VERSION 5.7 ;
  NOWIREEXTENSIONATPIN ON ;
  DIVIDERCHAR "/" ;
  BUSBITCHARS "[]" ;
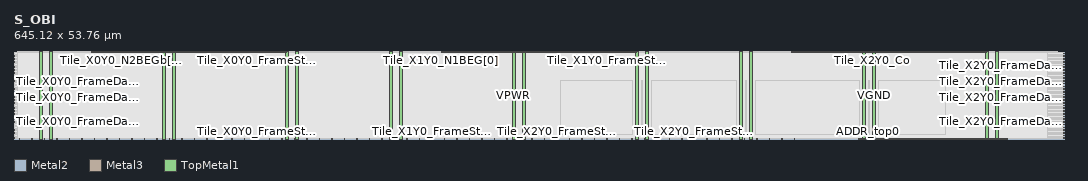
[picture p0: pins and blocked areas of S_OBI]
MACRO S_OBI
  CLASS BLOCK ;
  FOREIGN S_OBI ;
  ORIGIN 0.000 0.000 ;
  SIZE 645.120 BY 53.760 ;
  PIN ADDR_top0
    DIRECTION INPUT ;
    USE SIGNAL ;
    ANTENNAGATEAREA 1.684800 ;
    ANTENNADIFFAREA 4.030800 ;
    PORT
      LAYER Metal2 ;
        RECT 524.440 0.000 524.840 0.400 ;
    END
  END ADDR_top0
  PIN ADDR_top1
    DIRECTION INPUT ;
    USE SIGNAL ;
    ANTENNAGATEAREA 0.468000 ;
    PORT
      LAYER Metal2 ;
        RECT 525.400 0.000 525.800 0.400 ;
    END
  END ADDR_top1
  PIN ADDR_top10
    DIRECTION INPUT ;
    USE SIGNAL ;
    ANTENNAGATEAREA 0.468000 ;
    PORT
      LAYER Metal2 ;
        RECT 534.040 0.000 534.440 0.400 ;
    END
  END ADDR_top10
  PIN ADDR_top11
    DIRECTION INPUT ;
    USE SIGNAL ;
    ANTENNAGATEAREA 0.468000 ;
    PORT
      LAYER Metal2 ;
        RECT 535.000 0.000 535.400 0.400 ;
    END
  END ADDR_top11
  PIN ADDR_top12
    DIRECTION INPUT ;
    USE SIGNAL ;
    ANTENNAGATEAREA 0.468000 ;
    PORT
      LAYER Metal2 ;
        RECT 535.960 0.000 536.360 0.400 ;
    END
  END ADDR_top12
  PIN ADDR_top13
    DIRECTION INPUT ;
    USE SIGNAL ;
    ANTENNAGATEAREA 0.468000 ;
    PORT
      LAYER Metal2 ;
        RECT 536.920 0.000 537.320 0.400 ;
    END
  END ADDR_top13
  PIN ADDR_top14
    DIRECTION INPUT ;
    USE SIGNAL ;
    ANTENNAGATEAREA 0.452400 ;
    PORT
      LAYER Metal2 ;
        RECT 537.880 0.000 538.280 0.400 ;
    END
  END ADDR_top14
  PIN ADDR_top15
    DIRECTION INPUT ;
    USE SIGNAL ;
    ANTENNAGATEAREA 0.452400 ;
    PORT
      LAYER Metal2 ;
        RECT 538.840 0.000 539.240 0.400 ;
    END
  END ADDR_top15
  PIN ADDR_top16
    DIRECTION INPUT ;
    USE SIGNAL ;
    ANTENNAGATEAREA 0.452400 ;
    PORT
      LAYER Metal2 ;
        RECT 539.800 0.000 540.200 0.400 ;
    END
  END ADDR_top16
  PIN ADDR_top17
    DIRECTION INPUT ;
    USE SIGNAL ;
    ANTENNAGATEAREA 0.452400 ;
    PORT
      LAYER Metal2 ;
        RECT 540.760 0.000 541.160 0.400 ;
    END
  END ADDR_top17
  PIN ADDR_top18
    DIRECTION INPUT ;
    USE SIGNAL ;
    ANTENNAGATEAREA 0.452400 ;
    PORT
      LAYER Metal2 ;
        RECT 541.720 0.000 542.120 0.400 ;
    END
  END ADDR_top18
  PIN ADDR_top19
    DIRECTION INPUT ;
    USE SIGNAL ;
    ANTENNAGATEAREA 0.452400 ;
    PORT
      LAYER Metal2 ;
        RECT 542.680 0.000 543.080 0.400 ;
    END
  END ADDR_top19
  PIN ADDR_top2
    DIRECTION INPUT ;
    USE SIGNAL ;
    ANTENNAGATEAREA 0.468000 ;
    PORT
      LAYER Metal2 ;
        RECT 526.360 0.000 526.760 0.400 ;
    END
  END ADDR_top2
  PIN ADDR_top20
    DIRECTION INPUT ;
    USE SIGNAL ;
    ANTENNAGATEAREA 0.904800 ;
    PORT
      LAYER Metal2 ;
        RECT 543.640 0.000 544.040 0.400 ;
    END
  END ADDR_top20
  PIN ADDR_top21
    DIRECTION INPUT ;
    USE SIGNAL ;
    ANTENNAGATEAREA 0.904800 ;
    PORT
      LAYER Metal2 ;
        RECT 544.600 0.000 545.000 0.400 ;
    END
  END ADDR_top21
  PIN ADDR_top22
    DIRECTION INPUT ;
    USE SIGNAL ;
    ANTENNAGATEAREA 0.904800 ;
    PORT
      LAYER Metal2 ;
        RECT 545.560 0.000 545.960 0.400 ;
    END
  END ADDR_top22
  PIN ADDR_top23
    DIRECTION INPUT ;
    USE SIGNAL ;
    ANTENNAGATEAREA 3.946800 ;
    ANTENNADIFFAREA 10.077000 ;
    PORT
      LAYER Metal2 ;
        RECT 546.520 0.000 546.920 0.400 ;
    END
  END ADDR_top23
  PIN ADDR_top3
    DIRECTION INPUT ;
    USE SIGNAL ;
    ANTENNAGATEAREA 0.468000 ;
    PORT
      LAYER Metal2 ;
        RECT 527.320 0.000 527.720 0.400 ;
    END
  END ADDR_top3
  PIN ADDR_top4
    DIRECTION INPUT ;
    USE SIGNAL ;
    ANTENNAGATEAREA 0.452400 ;
    PORT
      LAYER Metal2 ;
        RECT 528.280 0.000 528.680 0.400 ;
    END
  END ADDR_top4
  PIN ADDR_top5
    DIRECTION INPUT ;
    USE SIGNAL ;
    ANTENNAGATEAREA 0.452400 ;
    PORT
      LAYER Metal2 ;
        RECT 529.240 0.000 529.640 0.400 ;
    END
  END ADDR_top5
  PIN ADDR_top6
    DIRECTION INPUT ;
    USE SIGNAL ;
    ANTENNAGATEAREA 0.452400 ;
    PORT
      LAYER Metal2 ;
        RECT 530.200 0.000 530.600 0.400 ;
    END
  END ADDR_top6
  PIN ADDR_top7
    DIRECTION INPUT ;
    USE SIGNAL ;
    ANTENNAGATEAREA 0.452400 ;
    PORT
      LAYER Metal2 ;
        RECT 531.160 0.000 531.560 0.400 ;
    END
  END ADDR_top7
  PIN ADDR_top8
    DIRECTION INPUT ;
    USE SIGNAL ;
    ANTENNAGATEAREA 0.452400 ;
    PORT
      LAYER Metal2 ;
        RECT 532.120 0.000 532.520 0.400 ;
    END
  END ADDR_top8
  PIN ADDR_top9
    DIRECTION INPUT ;
    USE SIGNAL ;
    ANTENNAGATEAREA 0.452400 ;
    PORT
      LAYER Metal2 ;
        RECT 533.080 0.000 533.480 0.400 ;
    END
  END ADDR_top9
  PIN BE_top0
    DIRECTION INPUT ;
    USE SIGNAL ;
    ANTENNAGATEAREA 0.665600 ;
    PORT
      LAYER Metal2 ;
        RECT 520.600 0.000 521.000 0.400 ;
    END
  END BE_top0
  PIN BE_top1
    DIRECTION INPUT ;
    USE SIGNAL ;
    ANTENNAGATEAREA 0.681200 ;
    PORT
      LAYER Metal2 ;
        RECT 521.560 0.000 521.960 0.400 ;
    END
  END BE_top1
  PIN BE_top2
    DIRECTION INPUT ;
    USE SIGNAL ;
    ANTENNAGATEAREA 0.665600 ;
    PORT
      LAYER Metal2 ;
        RECT 522.520 0.000 522.920 0.400 ;
    END
  END BE_top2
  PIN BE_top3
    DIRECTION INPUT ;
    USE SIGNAL ;
    ANTENNAGATEAREA 0.681200 ;
    PORT
      LAYER Metal2 ;
        RECT 523.480 0.000 523.880 0.400 ;
    END
  END BE_top3
  PIN GNT_top
    DIRECTION OUTPUT ;
    USE SIGNAL ;
    ANTENNADIFFAREA 0.615900 ;
    PORT
      LAYER Metal2 ;
        RECT 578.200 0.000 578.600 0.400 ;
    END
  END GNT_top
  PIN RDATA_top0
    DIRECTION OUTPUT ;
    USE SIGNAL ;
    ANTENNADIFFAREA 0.615900 ;
    PORT
      LAYER Metal2 ;
        RECT 580.120 0.000 580.520 0.400 ;
    END
  END RDATA_top0
  PIN RDATA_top1
    DIRECTION OUTPUT ;
    USE SIGNAL ;
    ANTENNADIFFAREA 0.615900 ;
    PORT
      LAYER Metal2 ;
        RECT 581.080 0.000 581.480 0.400 ;
    END
  END RDATA_top1
  PIN RDATA_top10
    DIRECTION OUTPUT ;
    USE SIGNAL ;
    ANTENNADIFFAREA 0.615900 ;
    PORT
      LAYER Metal2 ;
        RECT 589.720 0.000 590.120 0.400 ;
    END
  END RDATA_top10
  PIN RDATA_top11
    DIRECTION OUTPUT ;
    USE SIGNAL ;
    ANTENNADIFFAREA 0.615900 ;
    PORT
      LAYER Metal2 ;
        RECT 590.680 0.000 591.080 0.400 ;
    END
  END RDATA_top11
  PIN RDATA_top12
    DIRECTION OUTPUT ;
    USE SIGNAL ;
    ANTENNADIFFAREA 0.615900 ;
    PORT
      LAYER Metal2 ;
        RECT 591.640 0.000 592.040 0.400 ;
    END
  END RDATA_top12
  PIN RDATA_top13
    DIRECTION OUTPUT ;
    USE SIGNAL ;
    ANTENNADIFFAREA 0.615900 ;
    PORT
      LAYER Metal2 ;
        RECT 592.600 0.000 593.000 0.400 ;
    END
  END RDATA_top13
  PIN RDATA_top14
    DIRECTION OUTPUT ;
    USE SIGNAL ;
    ANTENNADIFFAREA 0.615900 ;
    PORT
      LAYER Metal2 ;
        RECT 593.560 0.000 593.960 0.400 ;
    END
  END RDATA_top14
  PIN RDATA_top15
    DIRECTION OUTPUT ;
    USE SIGNAL ;
    ANTENNADIFFAREA 0.615900 ;
    PORT
      LAYER Metal2 ;
        RECT 594.520 0.000 594.920 0.400 ;
    END
  END RDATA_top15
  PIN RDATA_top16
    DIRECTION OUTPUT ;
    USE SIGNAL ;
    ANTENNADIFFAREA 0.615900 ;
    PORT
      LAYER Metal2 ;
        RECT 595.480 0.000 595.880 0.400 ;
    END
  END RDATA_top16
  PIN RDATA_top17
    DIRECTION OUTPUT ;
    USE SIGNAL ;
    ANTENNADIFFAREA 0.615900 ;
    PORT
      LAYER Metal2 ;
        RECT 596.440 0.000 596.840 0.400 ;
    END
  END RDATA_top17
  PIN RDATA_top18
    DIRECTION OUTPUT ;
    USE SIGNAL ;
    ANTENNADIFFAREA 0.615900 ;
    PORT
      LAYER Metal2 ;
        RECT 597.400 0.000 597.800 0.400 ;
    END
  END RDATA_top18
  PIN RDATA_top19
    DIRECTION OUTPUT ;
    USE SIGNAL ;
    ANTENNADIFFAREA 0.615900 ;
    PORT
      LAYER Metal2 ;
        RECT 598.360 0.000 598.760 0.400 ;
    END
  END RDATA_top19
  PIN RDATA_top2
    DIRECTION OUTPUT ;
    USE SIGNAL ;
    ANTENNADIFFAREA 0.615900 ;
    PORT
      LAYER Metal2 ;
        RECT 582.040 0.000 582.440 0.400 ;
    END
  END RDATA_top2
  PIN RDATA_top20
    DIRECTION OUTPUT ;
    USE SIGNAL ;
    ANTENNADIFFAREA 0.677200 ;
    PORT
      LAYER Metal2 ;
        RECT 599.320 0.000 599.720 0.400 ;
    END
  END RDATA_top20
  PIN RDATA_top21
    DIRECTION OUTPUT ;
    USE SIGNAL ;
    ANTENNADIFFAREA 0.677200 ;
    PORT
      LAYER Metal2 ;
        RECT 600.280 0.000 600.680 0.400 ;
    END
  END RDATA_top21
  PIN RDATA_top22
    DIRECTION OUTPUT ;
    USE SIGNAL ;
    ANTENNADIFFAREA 0.677200 ;
    PORT
      LAYER Metal2 ;
        RECT 601.240 0.000 601.640 0.400 ;
    END
  END RDATA_top22
  PIN RDATA_top23
    DIRECTION OUTPUT ;
    USE SIGNAL ;
    ANTENNADIFFAREA 0.677200 ;
    PORT
      LAYER Metal2 ;
        RECT 602.200 0.000 602.600 0.400 ;
    END
  END RDATA_top23
  PIN RDATA_top24
    DIRECTION OUTPUT ;
    USE SIGNAL ;
    ANTENNADIFFAREA 0.677200 ;
    PORT
      LAYER Metal2 ;
        RECT 603.160 0.000 603.560 0.400 ;
    END
  END RDATA_top24
  PIN RDATA_top25
    DIRECTION OUTPUT ;
    USE SIGNAL ;
    ANTENNADIFFAREA 0.677200 ;
    PORT
      LAYER Metal2 ;
        RECT 604.120 0.000 604.520 0.400 ;
    END
  END RDATA_top25
  PIN RDATA_top26
    DIRECTION OUTPUT ;
    USE SIGNAL ;
    ANTENNADIFFAREA 0.677200 ;
    PORT
      LAYER Metal2 ;
        RECT 605.080 0.000 605.480 0.400 ;
    END
  END RDATA_top26
  PIN RDATA_top27
    DIRECTION OUTPUT ;
    USE SIGNAL ;
    ANTENNADIFFAREA 0.677200 ;
    PORT
      LAYER Metal2 ;
        RECT 606.040 0.000 606.440 0.400 ;
    END
  END RDATA_top27
  PIN RDATA_top28
    DIRECTION OUTPUT ;
    USE SIGNAL ;
    ANTENNADIFFAREA 0.677200 ;
    PORT
      LAYER Metal2 ;
        RECT 607.000 0.000 607.400 0.400 ;
    END
  END RDATA_top28
  PIN RDATA_top29
    DIRECTION OUTPUT ;
    USE SIGNAL ;
    ANTENNADIFFAREA 0.677200 ;
    PORT
      LAYER Metal2 ;
        RECT 607.960 0.000 608.360 0.400 ;
    END
  END RDATA_top29
  PIN RDATA_top3
    DIRECTION OUTPUT ;
    USE SIGNAL ;
    ANTENNADIFFAREA 0.615900 ;
    PORT
      LAYER Metal2 ;
        RECT 583.000 0.000 583.400 0.400 ;
    END
  END RDATA_top3
  PIN RDATA_top30
    DIRECTION OUTPUT ;
    USE SIGNAL ;
    ANTENNADIFFAREA 0.677200 ;
    PORT
      LAYER Metal2 ;
        RECT 608.920 0.000 609.320 0.400 ;
    END
  END RDATA_top30
  PIN RDATA_top31
    DIRECTION OUTPUT ;
    USE SIGNAL ;
    ANTENNADIFFAREA 0.677200 ;
    PORT
      LAYER Metal2 ;
        RECT 609.880 0.000 610.280 0.400 ;
    END
  END RDATA_top31
  PIN RDATA_top4
    DIRECTION OUTPUT ;
    USE SIGNAL ;
    ANTENNADIFFAREA 0.615900 ;
    PORT
      LAYER Metal2 ;
        RECT 583.960 0.000 584.360 0.400 ;
    END
  END RDATA_top4
  PIN RDATA_top5
    DIRECTION OUTPUT ;
    USE SIGNAL ;
    ANTENNADIFFAREA 0.615900 ;
    PORT
      LAYER Metal2 ;
        RECT 584.920 0.000 585.320 0.400 ;
    END
  END RDATA_top5
  PIN RDATA_top6
    DIRECTION OUTPUT ;
    USE SIGNAL ;
    ANTENNADIFFAREA 0.615900 ;
    PORT
      LAYER Metal2 ;
        RECT 585.880 0.000 586.280 0.400 ;
    END
  END RDATA_top6
  PIN RDATA_top7
    DIRECTION OUTPUT ;
    USE SIGNAL ;
    ANTENNADIFFAREA 0.615900 ;
    PORT
      LAYER Metal2 ;
        RECT 586.840 0.000 587.240 0.400 ;
    END
  END RDATA_top7
  PIN RDATA_top8
    DIRECTION OUTPUT ;
    USE SIGNAL ;
    ANTENNADIFFAREA 0.615900 ;
    PORT
      LAYER Metal2 ;
        RECT 587.800 0.000 588.200 0.400 ;
    END
  END RDATA_top8
  PIN RDATA_top9
    DIRECTION OUTPUT ;
    USE SIGNAL ;
    ANTENNADIFFAREA 0.615900 ;
    PORT
      LAYER Metal2 ;
        RECT 588.760 0.000 589.160 0.400 ;
    END
  END RDATA_top9
  PIN REQ_top
    DIRECTION INPUT ;
    USE SIGNAL ;
    ANTENNAGATEAREA 0.852800 ;
    PORT
      LAYER Metal2 ;
        RECT 518.680 0.000 519.080 0.400 ;
    END
  END REQ_top
  PIN RVALID_top
    DIRECTION OUTPUT ;
    USE SIGNAL ;
    ANTENNADIFFAREA 0.615900 ;
    PORT
      LAYER Metal2 ;
        RECT 579.160 0.000 579.560 0.400 ;
    END
  END RVALID_top
  PIN Tile_X0Y0_Co
    DIRECTION OUTPUT ;
    USE SIGNAL ;
    ANTENNADIFFAREA 0.299200 ;
    PORT
      LAYER Metal2 ;
        RECT 97.240 53.360 97.640 53.760 ;
    END
  END Tile_X0Y0_Co
  PIN Tile_X0Y0_FrameData[0]
    DIRECTION INPUT ;
    USE SIGNAL ;
    ANTENNAGATEAREA 5.523700 ;
    ANTENNADIFFAREA 14.107800 ;
    PORT
      LAYER Metal3 ;
        RECT 0.000 0.220 0.400 0.620 ;
    END
  END Tile_X0Y0_FrameData[0]
  PIN Tile_X0Y0_FrameData[10]
    DIRECTION INPUT ;
    USE SIGNAL ;
    ANTENNAGATEAREA 1.445600 ;
    PORT
      LAYER Metal3 ;
        RECT 0.000 17.020 0.400 17.420 ;
    END
  END Tile_X0Y0_FrameData[10]
  PIN Tile_X0Y0_FrameData[11]
    DIRECTION INPUT ;
    USE SIGNAL ;
    ANTENNAGATEAREA 1.445600 ;
    PORT
      LAYER Metal3 ;
        RECT 0.000 18.700 0.400 19.100 ;
    END
  END Tile_X0Y0_FrameData[11]
  PIN Tile_X0Y0_FrameData[12]
    DIRECTION INPUT ;
    USE SIGNAL ;
    ANTENNAGATEAREA 1.445600 ;
    PORT
      LAYER Metal3 ;
        RECT 0.000 20.380 0.400 20.780 ;
    END
  END Tile_X0Y0_FrameData[12]
  PIN Tile_X0Y0_FrameData[13]
    DIRECTION INPUT ;
    USE SIGNAL ;
    ANTENNAGATEAREA 1.445600 ;
    PORT
      LAYER Metal3 ;
        RECT 0.000 22.060 0.400 22.460 ;
    END
  END Tile_X0Y0_FrameData[13]
  PIN Tile_X0Y0_FrameData[14]
    DIRECTION INPUT ;
    USE SIGNAL ;
    ANTENNAGATEAREA 6.312800 ;
    ANTENNADIFFAREA 16.123199 ;
    PORT
      LAYER Metal3 ;
        RECT 0.000 23.740 0.400 24.140 ;
    END
  END Tile_X0Y0_FrameData[14]
  PIN Tile_X0Y0_FrameData[15]
    DIRECTION INPUT ;
    USE SIGNAL ;
    ANTENNAGATEAREA 1.445600 ;
    PORT
      LAYER Metal3 ;
        RECT 0.000 25.420 0.400 25.820 ;
    END
  END Tile_X0Y0_FrameData[15]
  PIN Tile_X0Y0_FrameData[16]
    DIRECTION INPUT ;
    USE SIGNAL ;
    ANTENNAGATEAREA 1.445600 ;
    PORT
      LAYER Metal3 ;
        RECT 0.000 27.100 0.400 27.500 ;
    END
  END Tile_X0Y0_FrameData[16]
  PIN Tile_X0Y0_FrameData[17]
    DIRECTION INPUT ;
    USE SIGNAL ;
    ANTENNAGATEAREA 1.445600 ;
    PORT
      LAYER Metal3 ;
        RECT 0.000 28.780 0.400 29.180 ;
    END
  END Tile_X0Y0_FrameData[17]
  PIN Tile_X0Y0_FrameData[18]
    DIRECTION INPUT ;
    USE SIGNAL ;
    ANTENNAGATEAREA 11.179999 ;
    ANTENNADIFFAREA 32.246399 ;
    PORT
      LAYER Metal3 ;
        RECT 0.000 30.460 0.400 30.860 ;
    END
  END Tile_X0Y0_FrameData[18]
  PIN Tile_X0Y0_FrameData[19]
    DIRECTION INPUT ;
    USE SIGNAL ;
    ANTENNAGATEAREA 1.445600 ;
    PORT
      LAYER Metal3 ;
        RECT 0.000 32.140 0.400 32.540 ;
    END
  END Tile_X0Y0_FrameData[19]
  PIN Tile_X0Y0_FrameData[1]
    DIRECTION INPUT ;
    USE SIGNAL ;
    ANTENNAGATEAREA 6.132100 ;
    ANTENNADIFFAREA 16.123199 ;
    PORT
      LAYER Metal3 ;
        RECT 0.000 1.900 0.400 2.300 ;
    END
  END Tile_X0Y0_FrameData[1]
  PIN Tile_X0Y0_FrameData[20]
    DIRECTION INPUT ;
    USE SIGNAL ;
    ANTENNAGATEAREA 8.138000 ;
    ANTENNADIFFAREA 22.169399 ;
    PORT
      LAYER Metal3 ;
        RECT 0.000 33.820 0.400 34.220 ;
    END
  END Tile_X0Y0_FrameData[20]
  PIN Tile_X0Y0_FrameData[21]
    DIRECTION INPUT ;
    USE SIGNAL ;
    ANTENNAGATEAREA 1.445600 ;
    PORT
      LAYER Metal3 ;
        RECT 0.000 35.500 0.400 35.900 ;
    END
  END Tile_X0Y0_FrameData[21]
  PIN Tile_X0Y0_FrameData[22]
    DIRECTION INPUT ;
    USE SIGNAL ;
    ANTENNAGATEAREA 6.312800 ;
    ANTENNADIFFAREA 16.123199 ;
    PORT
      LAYER Metal3 ;
        RECT 0.000 37.180 0.400 37.580 ;
    END
  END Tile_X0Y0_FrameData[22]
  PIN Tile_X0Y0_FrameData[23]
    DIRECTION INPUT ;
    USE SIGNAL ;
    ANTENNAGATEAREA 6.312800 ;
    ANTENNADIFFAREA 16.123199 ;
    PORT
      LAYER Metal3 ;
        RECT 0.000 38.860 0.400 39.260 ;
    END
  END Tile_X0Y0_FrameData[23]
  PIN Tile_X0Y0_FrameData[24]
    DIRECTION INPUT ;
    USE SIGNAL ;
    ANTENNAGATEAREA 1.445600 ;
    PORT
      LAYER Metal3 ;
        RECT 0.000 40.540 0.400 40.940 ;
    END
  END Tile_X0Y0_FrameData[24]
  PIN Tile_X0Y0_FrameData[25]
    DIRECTION INPUT ;
    USE SIGNAL ;
    ANTENNAGATEAREA 1.445600 ;
    PORT
      LAYER Metal3 ;
        RECT 0.000 42.220 0.400 42.620 ;
    END
  END Tile_X0Y0_FrameData[25]
  PIN Tile_X0Y0_FrameData[26]
    DIRECTION INPUT ;
    USE SIGNAL ;
    ANTENNAGATEAREA 1.807000 ;
    PORT
      LAYER Metal3 ;
        RECT 0.000 43.900 0.400 44.300 ;
    END
  END Tile_X0Y0_FrameData[26]
  PIN Tile_X0Y0_FrameData[27]
    DIRECTION INPUT ;
    USE SIGNAL ;
    ANTENNAGATEAREA 1.807000 ;
    PORT
      LAYER Metal3 ;
        RECT 0.000 45.580 0.400 45.980 ;
    END
  END Tile_X0Y0_FrameData[27]
  PIN Tile_X0Y0_FrameData[28]
    DIRECTION INPUT ;
    USE SIGNAL ;
    ANTENNAGATEAREA 1.807000 ;
    PORT
      LAYER Metal3 ;
        RECT 0.000 47.260 0.400 47.660 ;
    END
  END Tile_X0Y0_FrameData[28]
  PIN Tile_X0Y0_FrameData[29]
    DIRECTION INPUT ;
    USE SIGNAL ;
    ANTENNAGATEAREA 1.807000 ;
    PORT
      LAYER Metal3 ;
        RECT 0.000 48.940 0.400 49.340 ;
    END
  END Tile_X0Y0_FrameData[29]
  PIN Tile_X0Y0_FrameData[2]
    DIRECTION INPUT ;
    USE SIGNAL ;
    ANTENNAGATEAREA 7.957300 ;
    ANTENNADIFFAREA 22.169399 ;
    PORT
      LAYER Metal3 ;
        RECT 0.000 3.580 0.400 3.980 ;
    END
  END Tile_X0Y0_FrameData[2]
  PIN Tile_X0Y0_FrameData[30]
    DIRECTION INPUT ;
    USE SIGNAL ;
    ANTENNAGATEAREA 13.366600 ;
    ANTENNADIFFAREA 38.292599 ;
    PORT
      LAYER Metal3 ;
        RECT 0.000 50.620 0.400 51.020 ;
    END
  END Tile_X0Y0_FrameData[30]
  PIN Tile_X0Y0_FrameData[31]
    DIRECTION INPUT ;
    USE SIGNAL ;
    ANTENNAGATEAREA 1.807000 ;
    PORT
      LAYER Metal3 ;
        RECT 0.000 52.300 0.400 52.700 ;
    END
  END Tile_X0Y0_FrameData[31]
  PIN Tile_X0Y0_FrameData[3]
    DIRECTION INPUT ;
    USE SIGNAL ;
    ANTENNAGATEAREA 1.264900 ;
    PORT
      LAYER Metal3 ;
        RECT 0.000 5.260 0.400 5.660 ;
    END
  END Tile_X0Y0_FrameData[3]
  PIN Tile_X0Y0_FrameData[4]
    DIRECTION INPUT ;
    USE SIGNAL ;
    ANTENNAGATEAREA 1.264900 ;
    PORT
      LAYER Metal3 ;
        RECT 0.000 6.940 0.400 7.340 ;
    END
  END Tile_X0Y0_FrameData[4]
  PIN Tile_X0Y0_FrameData[5]
    DIRECTION INPUT ;
    USE SIGNAL ;
    ANTENNAGATEAREA 6.132100 ;
    ANTENNADIFFAREA 16.123199 ;
    PORT
      LAYER Metal3 ;
        RECT 0.000 8.620 0.400 9.020 ;
    END
  END Tile_X0Y0_FrameData[5]
  PIN Tile_X0Y0_FrameData[6]
    DIRECTION INPUT ;
    USE SIGNAL ;
    ANTENNAGATEAREA 5.523700 ;
    ANTENNADIFFAREA 14.107800 ;
    PORT
      LAYER Metal3 ;
        RECT 0.000 10.300 0.400 10.700 ;
    END
  END Tile_X0Y0_FrameData[6]
  PIN Tile_X0Y0_FrameData[7]
    DIRECTION INPUT ;
    USE SIGNAL ;
    ANTENNAGATEAREA 1.264900 ;
    PORT
      LAYER Metal3 ;
        RECT 0.000 11.980 0.400 12.380 ;
    END
  END Tile_X0Y0_FrameData[7]
  PIN Tile_X0Y0_FrameData[8]
    DIRECTION INPUT ;
    USE SIGNAL ;
    ANTENNAGATEAREA 1.264900 ;
    PORT
      LAYER Metal3 ;
        RECT 0.000 13.660 0.400 14.060 ;
    END
  END Tile_X0Y0_FrameData[8]
  PIN Tile_X0Y0_FrameData[9]
    DIRECTION INPUT ;
    USE SIGNAL ;
    ANTENNAGATEAREA 5.523700 ;
    ANTENNADIFFAREA 14.107800 ;
    PORT
      LAYER Metal3 ;
        RECT 0.000 15.340 0.400 15.740 ;
    END
  END Tile_X0Y0_FrameData[9]
  PIN Tile_X0Y0_FrameStrobe[0]
    DIRECTION INPUT ;
    USE SIGNAL ;
    ANTENNAGATEAREA 6.753500 ;
    PORT
      LAYER Metal2 ;
        RECT 10.840 0.000 11.240 0.400 ;
    END
  END Tile_X0Y0_FrameStrobe[0]
  PIN Tile_X0Y0_FrameStrobe[10]
    DIRECTION INPUT ;
    USE SIGNAL ;
    ANTENNAGATEAREA 0.180700 ;
    PORT
      LAYER Metal2 ;
        RECT 87.640 0.000 88.040 0.400 ;
    END
  END Tile_X0Y0_FrameStrobe[10]
  PIN Tile_X0Y0_FrameStrobe[11]
    DIRECTION INPUT ;
    USE SIGNAL ;
    ANTENNAGATEAREA 0.180700 ;
    PORT
      LAYER Metal2 ;
        RECT 95.320 0.000 95.720 0.400 ;
    END
  END Tile_X0Y0_FrameStrobe[11]
  PIN Tile_X0Y0_FrameStrobe[12]
    DIRECTION INPUT ;
    USE SIGNAL ;
    ANTENNAGATEAREA 0.180700 ;
    PORT
      LAYER Metal2 ;
        RECT 103.000 0.000 103.400 0.400 ;
    END
  END Tile_X0Y0_FrameStrobe[12]
  PIN Tile_X0Y0_FrameStrobe[13]
    DIRECTION INPUT ;
    USE SIGNAL ;
    ANTENNAGATEAREA 0.180700 ;
    PORT
      LAYER Metal2 ;
        RECT 110.680 0.000 111.080 0.400 ;
    END
  END Tile_X0Y0_FrameStrobe[13]
  PIN Tile_X0Y0_FrameStrobe[14]
    DIRECTION INPUT ;
    USE SIGNAL ;
    ANTENNAGATEAREA 0.180700 ;
    PORT
      LAYER Metal2 ;
        RECT 118.360 0.000 118.760 0.400 ;
    END
  END Tile_X0Y0_FrameStrobe[14]
  PIN Tile_X0Y0_FrameStrobe[15]
    DIRECTION INPUT ;
    USE SIGNAL ;
    ANTENNAGATEAREA 0.180700 ;
    PORT
      LAYER Metal2 ;
        RECT 126.040 0.000 126.440 0.400 ;
    END
  END Tile_X0Y0_FrameStrobe[15]
  PIN Tile_X0Y0_FrameStrobe[16]
    DIRECTION INPUT ;
    USE SIGNAL ;
    ANTENNAGATEAREA 0.180700 ;
    PORT
      LAYER Metal2 ;
        RECT 133.720 0.000 134.120 0.400 ;
    END
  END Tile_X0Y0_FrameStrobe[16]
  PIN Tile_X0Y0_FrameStrobe[17]
    DIRECTION INPUT ;
    USE SIGNAL ;
    ANTENNAGATEAREA 0.180700 ;
    PORT
      LAYER Metal2 ;
        RECT 141.400 0.000 141.800 0.400 ;
    END
  END Tile_X0Y0_FrameStrobe[17]
  PIN Tile_X0Y0_FrameStrobe[18]
    DIRECTION INPUT ;
    USE SIGNAL ;
    ANTENNAGATEAREA 0.180700 ;
    PORT
      LAYER Metal2 ;
        RECT 149.080 0.000 149.480 0.400 ;
    END
  END Tile_X0Y0_FrameStrobe[18]
  PIN Tile_X0Y0_FrameStrobe[19]
    DIRECTION INPUT ;
    USE SIGNAL ;
    ANTENNAGATEAREA 0.180700 ;
    PORT
      LAYER Metal2 ;
        RECT 156.760 0.000 157.160 0.400 ;
    END
  END Tile_X0Y0_FrameStrobe[19]
  PIN Tile_X0Y0_FrameStrobe[1]
    DIRECTION INPUT ;
    USE SIGNAL ;
    ANTENNAGATEAREA 6.753500 ;
    PORT
      LAYER Metal2 ;
        RECT 18.520 0.000 18.920 0.400 ;
    END
  END Tile_X0Y0_FrameStrobe[1]
  PIN Tile_X0Y0_FrameStrobe[2]
    DIRECTION INPUT ;
    USE SIGNAL ;
    ANTENNAGATEAREA 1.413100 ;
    PORT
      LAYER Metal2 ;
        RECT 26.200 0.000 26.600 0.400 ;
    END
  END Tile_X0Y0_FrameStrobe[2]
  PIN Tile_X0Y0_FrameStrobe[3]
    DIRECTION INPUT ;
    USE SIGNAL ;
    ANTENNAGATEAREA 0.180700 ;
    PORT
      LAYER Metal2 ;
        RECT 33.880 0.000 34.280 0.400 ;
    END
  END Tile_X0Y0_FrameStrobe[3]
  PIN Tile_X0Y0_FrameStrobe[4]
    DIRECTION INPUT ;
    USE SIGNAL ;
    ANTENNAGATEAREA 0.180700 ;
    PORT
      LAYER Metal2 ;
        RECT 41.560 0.000 41.960 0.400 ;
    END
  END Tile_X0Y0_FrameStrobe[4]
  PIN Tile_X0Y0_FrameStrobe[5]
    DIRECTION INPUT ;
    USE SIGNAL ;
    ANTENNAGATEAREA 0.180700 ;
    PORT
      LAYER Metal2 ;
        RECT 49.240 0.000 49.640 0.400 ;
    END
  END Tile_X0Y0_FrameStrobe[5]
  PIN Tile_X0Y0_FrameStrobe[6]
    DIRECTION INPUT ;
    USE SIGNAL ;
    ANTENNAGATEAREA 0.180700 ;
    PORT
      LAYER Metal2 ;
        RECT 56.920 0.000 57.320 0.400 ;
    END
  END Tile_X0Y0_FrameStrobe[6]
  PIN Tile_X0Y0_FrameStrobe[7]
    DIRECTION INPUT ;
    USE SIGNAL ;
    ANTENNAGATEAREA 0.180700 ;
    PORT
      LAYER Metal2 ;
        RECT 64.600 0.000 65.000 0.400 ;
    END
  END Tile_X0Y0_FrameStrobe[7]
  PIN Tile_X0Y0_FrameStrobe[8]
    DIRECTION INPUT ;
    USE SIGNAL ;
    ANTENNAGATEAREA 0.180700 ;
    PORT
      LAYER Metal2 ;
        RECT 72.280 0.000 72.680 0.400 ;
    END
  END Tile_X0Y0_FrameStrobe[8]
  PIN Tile_X0Y0_FrameStrobe[9]
    DIRECTION INPUT ;
    USE SIGNAL ;
    ANTENNAGATEAREA 0.180700 ;
    PORT
      LAYER Metal2 ;
        RECT 79.960 0.000 80.360 0.400 ;
    END
  END Tile_X0Y0_FrameStrobe[9]
  PIN Tile_X0Y0_FrameStrobe_O[0]
    DIRECTION OUTPUT ;
    USE SIGNAL ;
    ANTENNADIFFAREA 0.708600 ;
    PORT
      LAYER Metal2 ;
        RECT 149.080 53.360 149.480 53.760 ;
    END
  END Tile_X0Y0_FrameStrobe_O[0]
  PIN Tile_X0Y0_FrameStrobe_O[10]
    DIRECTION OUTPUT ;
    USE SIGNAL ;
    ANTENNADIFFAREA 0.708600 ;
    PORT
      LAYER Metal2 ;
        RECT 158.680 53.360 159.080 53.760 ;
    END
  END Tile_X0Y0_FrameStrobe_O[10]
  PIN Tile_X0Y0_FrameStrobe_O[11]
    DIRECTION OUTPUT ;
    USE SIGNAL ;
    ANTENNADIFFAREA 0.708600 ;
    PORT
      LAYER Metal2 ;
        RECT 159.640 53.360 160.040 53.760 ;
    END
  END Tile_X0Y0_FrameStrobe_O[11]
  PIN Tile_X0Y0_FrameStrobe_O[12]
    DIRECTION OUTPUT ;
    USE SIGNAL ;
    ANTENNADIFFAREA 0.708600 ;
    PORT
      LAYER Metal2 ;
        RECT 160.600 53.360 161.000 53.760 ;
    END
  END Tile_X0Y0_FrameStrobe_O[12]
  PIN Tile_X0Y0_FrameStrobe_O[13]
    DIRECTION OUTPUT ;
    USE SIGNAL ;
    ANTENNADIFFAREA 0.708600 ;
    PORT
      LAYER Metal2 ;
        RECT 161.560 53.360 161.960 53.760 ;
    END
  END Tile_X0Y0_FrameStrobe_O[13]
  PIN Tile_X0Y0_FrameStrobe_O[14]
    DIRECTION OUTPUT ;
    USE SIGNAL ;
    ANTENNADIFFAREA 0.708600 ;
    PORT
      LAYER Metal2 ;
        RECT 162.520 53.360 162.920 53.760 ;
    END
  END Tile_X0Y0_FrameStrobe_O[14]
  PIN Tile_X0Y0_FrameStrobe_O[15]
    DIRECTION OUTPUT ;
    USE SIGNAL ;
    ANTENNADIFFAREA 0.708600 ;
    PORT
      LAYER Metal2 ;
        RECT 163.480 53.360 163.880 53.760 ;
    END
  END Tile_X0Y0_FrameStrobe_O[15]
  PIN Tile_X0Y0_FrameStrobe_O[16]
    DIRECTION OUTPUT ;
    USE SIGNAL ;
    ANTENNADIFFAREA 0.708600 ;
    PORT
      LAYER Metal2 ;
        RECT 164.440 53.360 164.840 53.760 ;
    END
  END Tile_X0Y0_FrameStrobe_O[16]
  PIN Tile_X0Y0_FrameStrobe_O[17]
    DIRECTION OUTPUT ;
    USE SIGNAL ;
    ANTENNADIFFAREA 0.708600 ;
    PORT
      LAYER Metal2 ;
        RECT 165.400 53.360 165.800 53.760 ;
    END
  END Tile_X0Y0_FrameStrobe_O[17]
  PIN Tile_X0Y0_FrameStrobe_O[18]
    DIRECTION OUTPUT ;
    USE SIGNAL ;
    ANTENNADIFFAREA 0.708600 ;
    PORT
      LAYER Metal2 ;
        RECT 166.360 53.360 166.760 53.760 ;
    END
  END Tile_X0Y0_FrameStrobe_O[18]
  PIN Tile_X0Y0_FrameStrobe_O[19]
    DIRECTION OUTPUT ;
    USE SIGNAL ;
    ANTENNADIFFAREA 0.708600 ;
    PORT
      LAYER Metal2 ;
        RECT 167.320 53.360 167.720 53.760 ;
    END
  END Tile_X0Y0_FrameStrobe_O[19]
  PIN Tile_X0Y0_FrameStrobe_O[1]
    DIRECTION OUTPUT ;
    USE SIGNAL ;
    ANTENNADIFFAREA 0.708600 ;
    PORT
      LAYER Metal2 ;
        RECT 150.040 53.360 150.440 53.760 ;
    END
  END Tile_X0Y0_FrameStrobe_O[1]
  PIN Tile_X0Y0_FrameStrobe_O[2]
    DIRECTION OUTPUT ;
    USE SIGNAL ;
    ANTENNADIFFAREA 0.708600 ;
    PORT
      LAYER Metal2 ;
        RECT 151.000 53.360 151.400 53.760 ;
    END
  END Tile_X0Y0_FrameStrobe_O[2]
  PIN Tile_X0Y0_FrameStrobe_O[3]
    DIRECTION OUTPUT ;
    USE SIGNAL ;
    ANTENNADIFFAREA 0.708600 ;
    PORT
      LAYER Metal2 ;
        RECT 151.960 53.360 152.360 53.760 ;
    END
  END Tile_X0Y0_FrameStrobe_O[3]
  PIN Tile_X0Y0_FrameStrobe_O[4]
    DIRECTION OUTPUT ;
    USE SIGNAL ;
    ANTENNADIFFAREA 0.708600 ;
    PORT
      LAYER Metal2 ;
        RECT 152.920 53.360 153.320 53.760 ;
    END
  END Tile_X0Y0_FrameStrobe_O[4]
  PIN Tile_X0Y0_FrameStrobe_O[5]
    DIRECTION OUTPUT ;
    USE SIGNAL ;
    ANTENNADIFFAREA 0.708600 ;
    PORT
      LAYER Metal2 ;
        RECT 153.880 53.360 154.280 53.760 ;
    END
  END Tile_X0Y0_FrameStrobe_O[5]
  PIN Tile_X0Y0_FrameStrobe_O[6]
    DIRECTION OUTPUT ;
    USE SIGNAL ;
    ANTENNADIFFAREA 0.708600 ;
    PORT
      LAYER Metal2 ;
        RECT 154.840 53.360 155.240 53.760 ;
    END
  END Tile_X0Y0_FrameStrobe_O[6]
  PIN Tile_X0Y0_FrameStrobe_O[7]
    DIRECTION OUTPUT ;
    USE SIGNAL ;
    ANTENNADIFFAREA 0.708600 ;
    PORT
      LAYER Metal2 ;
        RECT 155.800 53.360 156.200 53.760 ;
    END
  END Tile_X0Y0_FrameStrobe_O[7]
  PIN Tile_X0Y0_FrameStrobe_O[8]
    DIRECTION OUTPUT ;
    USE SIGNAL ;
    ANTENNADIFFAREA 0.708600 ;
    PORT
      LAYER Metal2 ;
        RECT 156.760 53.360 157.160 53.760 ;
    END
  END Tile_X0Y0_FrameStrobe_O[8]
  PIN Tile_X0Y0_FrameStrobe_O[9]
    DIRECTION OUTPUT ;
    USE SIGNAL ;
    ANTENNADIFFAREA 0.708600 ;
    PORT
      LAYER Metal2 ;
        RECT 157.720 53.360 158.120 53.760 ;
    END
  END Tile_X0Y0_FrameStrobe_O[9]
  PIN Tile_X0Y0_N1BEG[0]
    DIRECTION OUTPUT ;
    USE SIGNAL ;
    ANTENNADIFFAREA 0.708600 ;
    PORT
      LAYER Metal2 ;
        RECT 47.320 53.360 47.720 53.760 ;
    END
  END Tile_X0Y0_N1BEG[0]
  PIN Tile_X0Y0_N1BEG[1]
    DIRECTION OUTPUT ;
    USE SIGNAL ;
    ANTENNADIFFAREA 0.708600 ;
    PORT
      LAYER Metal2 ;
        RECT 48.280 53.360 48.680 53.760 ;
    END
  END Tile_X0Y0_N1BEG[1]
  PIN Tile_X0Y0_N1BEG[2]
    DIRECTION OUTPUT ;
    USE SIGNAL ;
    ANTENNADIFFAREA 0.708600 ;
    PORT
      LAYER Metal2 ;
        RECT 49.240 53.360 49.640 53.760 ;
    END
  END Tile_X0Y0_N1BEG[2]
  PIN Tile_X0Y0_N1BEG[3]
    DIRECTION OUTPUT ;
    USE SIGNAL ;
    ANTENNADIFFAREA 0.708600 ;
    PORT
      LAYER Metal2 ;
        RECT 50.200 53.360 50.600 53.760 ;
    END
  END Tile_X0Y0_N1BEG[3]
  PIN Tile_X0Y0_N2BEG[0]
    DIRECTION OUTPUT ;
    USE SIGNAL ;
    ANTENNADIFFAREA 0.708600 ;
    PORT
      LAYER Metal2 ;
        RECT 51.160 53.360 51.560 53.760 ;
    END
  END Tile_X0Y0_N2BEG[0]
  PIN Tile_X0Y0_N2BEG[1]
    DIRECTION OUTPUT ;
    USE SIGNAL ;
    ANTENNADIFFAREA 0.708600 ;
    PORT
      LAYER Metal2 ;
        RECT 52.120 53.360 52.520 53.760 ;
    END
  END Tile_X0Y0_N2BEG[1]
  PIN Tile_X0Y0_N2BEG[2]
    DIRECTION OUTPUT ;
    USE SIGNAL ;
    ANTENNADIFFAREA 0.708600 ;
    PORT
      LAYER Metal2 ;
        RECT 53.080 53.360 53.480 53.760 ;
    END
  END Tile_X0Y0_N2BEG[2]
  PIN Tile_X0Y0_N2BEG[3]
    DIRECTION OUTPUT ;
    USE SIGNAL ;
    ANTENNADIFFAREA 0.708600 ;
    PORT
      LAYER Metal2 ;
        RECT 54.040 53.360 54.440 53.760 ;
    END
  END Tile_X0Y0_N2BEG[3]
  PIN Tile_X0Y0_N2BEG[4]
    DIRECTION OUTPUT ;
    USE SIGNAL ;
    ANTENNADIFFAREA 0.708600 ;
    PORT
      LAYER Metal2 ;
        RECT 55.000 53.360 55.400 53.760 ;
    END
  END Tile_X0Y0_N2BEG[4]
  PIN Tile_X0Y0_N2BEG[5]
    DIRECTION OUTPUT ;
    USE SIGNAL ;
    ANTENNADIFFAREA 0.708600 ;
    PORT
      LAYER Metal2 ;
        RECT 55.960 53.360 56.360 53.760 ;
    END
  END Tile_X0Y0_N2BEG[5]
  PIN Tile_X0Y0_N2BEG[6]
    DIRECTION OUTPUT ;
    USE SIGNAL ;
    ANTENNADIFFAREA 0.708600 ;
    PORT
      LAYER Metal2 ;
        RECT 56.920 53.360 57.320 53.760 ;
    END
  END Tile_X0Y0_N2BEG[6]
  PIN Tile_X0Y0_N2BEG[7]
    DIRECTION OUTPUT ;
    USE SIGNAL ;
    ANTENNADIFFAREA 0.708600 ;
    PORT
      LAYER Metal2 ;
        RECT 57.880 53.360 58.280 53.760 ;
    END
  END Tile_X0Y0_N2BEG[7]
  PIN Tile_X0Y0_N2BEGb[0]
    DIRECTION OUTPUT ;
    USE SIGNAL ;
    ANTENNADIFFAREA 0.708600 ;
    PORT
      LAYER Metal2 ;
        RECT 58.840 53.360 59.240 53.760 ;
    END
  END Tile_X0Y0_N2BEGb[0]
  PIN Tile_X0Y0_N2BEGb[1]
    DIRECTION OUTPUT ;
    USE SIGNAL ;
    ANTENNADIFFAREA 0.708600 ;
    PORT
      LAYER Metal2 ;
        RECT 59.800 53.360 60.200 53.760 ;
    END
  END Tile_X0Y0_N2BEGb[1]
  PIN Tile_X0Y0_N2BEGb[2]
    DIRECTION OUTPUT ;
    USE SIGNAL ;
    ANTENNADIFFAREA 0.708600 ;
    PORT
      LAYER Metal2 ;
        RECT 60.760 53.360 61.160 53.760 ;
    END
  END Tile_X0Y0_N2BEGb[2]
  PIN Tile_X0Y0_N2BEGb[3]
    DIRECTION OUTPUT ;
    USE SIGNAL ;
    ANTENNADIFFAREA 0.708600 ;
    PORT
      LAYER Metal2 ;
        RECT 61.720 53.360 62.120 53.760 ;
    END
  END Tile_X0Y0_N2BEGb[3]
  PIN Tile_X0Y0_N2BEGb[4]
    DIRECTION OUTPUT ;
    USE SIGNAL ;
    ANTENNADIFFAREA 0.708600 ;
    PORT
      LAYER Metal2 ;
        RECT 62.680 53.360 63.080 53.760 ;
    END
  END Tile_X0Y0_N2BEGb[4]
  PIN Tile_X0Y0_N2BEGb[5]
    DIRECTION OUTPUT ;
    USE SIGNAL ;
    ANTENNADIFFAREA 0.708600 ;
    PORT
      LAYER Metal2 ;
        RECT 63.640 53.360 64.040 53.760 ;
    END
  END Tile_X0Y0_N2BEGb[5]
  PIN Tile_X0Y0_N2BEGb[6]
    DIRECTION OUTPUT ;
    USE SIGNAL ;
    ANTENNADIFFAREA 0.708600 ;
    PORT
      LAYER Metal2 ;
        RECT 64.600 53.360 65.000 53.760 ;
    END
  END Tile_X0Y0_N2BEGb[6]
  PIN Tile_X0Y0_N2BEGb[7]
    DIRECTION OUTPUT ;
    USE SIGNAL ;
    ANTENNADIFFAREA 0.708600 ;
    PORT
      LAYER Metal2 ;
        RECT 65.560 53.360 65.960 53.760 ;
    END
  END Tile_X0Y0_N2BEGb[7]
  PIN Tile_X0Y0_N4BEG[0]
    DIRECTION OUTPUT ;
    USE SIGNAL ;
    ANTENNADIFFAREA 0.708600 ;
    PORT
      LAYER Metal2 ;
        RECT 66.520 53.360 66.920 53.760 ;
    END
  END Tile_X0Y0_N4BEG[0]
  PIN Tile_X0Y0_N4BEG[10]
    DIRECTION OUTPUT ;
    USE SIGNAL ;
    ANTENNADIFFAREA 0.708600 ;
    PORT
      LAYER Metal2 ;
        RECT 76.120 53.360 76.520 53.760 ;
    END
  END Tile_X0Y0_N4BEG[10]
  PIN Tile_X0Y0_N4BEG[11]
    DIRECTION OUTPUT ;
    USE SIGNAL ;
    ANTENNADIFFAREA 0.708600 ;
    PORT
      LAYER Metal2 ;
        RECT 77.080 53.360 77.480 53.760 ;
    END
  END Tile_X0Y0_N4BEG[11]
  PIN Tile_X0Y0_N4BEG[12]
    DIRECTION OUTPUT ;
    USE SIGNAL ;
    ANTENNADIFFAREA 0.708600 ;
    PORT
      LAYER Metal2 ;
        RECT 78.040 53.360 78.440 53.760 ;
    END
  END Tile_X0Y0_N4BEG[12]
  PIN Tile_X0Y0_N4BEG[13]
    DIRECTION OUTPUT ;
    USE SIGNAL ;
    ANTENNADIFFAREA 0.708600 ;
    PORT
      LAYER Metal2 ;
        RECT 79.000 53.360 79.400 53.760 ;
    END
  END Tile_X0Y0_N4BEG[13]
  PIN Tile_X0Y0_N4BEG[14]
    DIRECTION OUTPUT ;
    USE SIGNAL ;
    ANTENNADIFFAREA 0.708600 ;
    PORT
      LAYER Metal2 ;
        RECT 79.960 53.360 80.360 53.760 ;
    END
  END Tile_X0Y0_N4BEG[14]
  PIN Tile_X0Y0_N4BEG[15]
    DIRECTION OUTPUT ;
    USE SIGNAL ;
    ANTENNADIFFAREA 0.708600 ;
    PORT
      LAYER Metal2 ;
        RECT 80.920 53.360 81.320 53.760 ;
    END
  END Tile_X0Y0_N4BEG[15]
  PIN Tile_X0Y0_N4BEG[1]
    DIRECTION OUTPUT ;
    USE SIGNAL ;
    ANTENNADIFFAREA 0.708600 ;
    PORT
      LAYER Metal2 ;
        RECT 67.480 53.360 67.880 53.760 ;
    END
  END Tile_X0Y0_N4BEG[1]
  PIN Tile_X0Y0_N4BEG[2]
    DIRECTION OUTPUT ;
    USE SIGNAL ;
    ANTENNADIFFAREA 0.708600 ;
    PORT
      LAYER Metal2 ;
        RECT 68.440 53.360 68.840 53.760 ;
    END
  END Tile_X0Y0_N4BEG[2]
  PIN Tile_X0Y0_N4BEG[3]
    DIRECTION OUTPUT ;
    USE SIGNAL ;
    ANTENNADIFFAREA 0.708600 ;
    PORT
      LAYER Metal2 ;
        RECT 69.400 53.360 69.800 53.760 ;
    END
  END Tile_X0Y0_N4BEG[3]
  PIN Tile_X0Y0_N4BEG[4]
    DIRECTION OUTPUT ;
    USE SIGNAL ;
    ANTENNADIFFAREA 0.708600 ;
    PORT
      LAYER Metal2 ;
        RECT 70.360 53.360 70.760 53.760 ;
    END
  END Tile_X0Y0_N4BEG[4]
  PIN Tile_X0Y0_N4BEG[5]
    DIRECTION OUTPUT ;
    USE SIGNAL ;
    ANTENNADIFFAREA 0.708600 ;
    PORT
      LAYER Metal2 ;
        RECT 71.320 53.360 71.720 53.760 ;
    END
  END Tile_X0Y0_N4BEG[5]
  PIN Tile_X0Y0_N4BEG[6]
    DIRECTION OUTPUT ;
    USE SIGNAL ;
    ANTENNADIFFAREA 0.708600 ;
    PORT
      LAYER Metal2 ;
        RECT 72.280 53.360 72.680 53.760 ;
    END
  END Tile_X0Y0_N4BEG[6]
  PIN Tile_X0Y0_N4BEG[7]
    DIRECTION OUTPUT ;
    USE SIGNAL ;
    ANTENNADIFFAREA 0.708600 ;
    PORT
      LAYER Metal2 ;
        RECT 73.240 53.360 73.640 53.760 ;
    END
  END Tile_X0Y0_N4BEG[7]
  PIN Tile_X0Y0_N4BEG[8]
    DIRECTION OUTPUT ;
    USE SIGNAL ;
    ANTENNADIFFAREA 0.708600 ;
    PORT
      LAYER Metal2 ;
        RECT 74.200 53.360 74.600 53.760 ;
    END
  END Tile_X0Y0_N4BEG[8]
  PIN Tile_X0Y0_N4BEG[9]
    DIRECTION OUTPUT ;
    USE SIGNAL ;
    ANTENNADIFFAREA 0.708600 ;
    PORT
      LAYER Metal2 ;
        RECT 75.160 53.360 75.560 53.760 ;
    END
  END Tile_X0Y0_N4BEG[9]
  PIN Tile_X0Y0_NN4BEG[0]
    DIRECTION OUTPUT ;
    USE SIGNAL ;
    ANTENNADIFFAREA 0.708600 ;
    PORT
      LAYER Metal2 ;
        RECT 81.880 53.360 82.280 53.760 ;
    END
  END Tile_X0Y0_NN4BEG[0]
  PIN Tile_X0Y0_NN4BEG[10]
    DIRECTION OUTPUT ;
    USE SIGNAL ;
    ANTENNADIFFAREA 0.708600 ;
    PORT
      LAYER Metal2 ;
        RECT 91.480 53.360 91.880 53.760 ;
    END
  END Tile_X0Y0_NN4BEG[10]
  PIN Tile_X0Y0_NN4BEG[11]
    DIRECTION OUTPUT ;
    USE SIGNAL ;
    ANTENNADIFFAREA 0.708600 ;
    PORT
      LAYER Metal2 ;
        RECT 92.440 53.360 92.840 53.760 ;
    END
  END Tile_X0Y0_NN4BEG[11]
  PIN Tile_X0Y0_NN4BEG[12]
    DIRECTION OUTPUT ;
    USE SIGNAL ;
    ANTENNADIFFAREA 0.708600 ;
    PORT
      LAYER Metal2 ;
        RECT 93.400 53.360 93.800 53.760 ;
    END
  END Tile_X0Y0_NN4BEG[12]
  PIN Tile_X0Y0_NN4BEG[13]
    DIRECTION OUTPUT ;
    USE SIGNAL ;
    ANTENNADIFFAREA 0.708600 ;
    PORT
      LAYER Metal2 ;
        RECT 94.360 53.360 94.760 53.760 ;
    END
  END Tile_X0Y0_NN4BEG[13]
  PIN Tile_X0Y0_NN4BEG[14]
    DIRECTION OUTPUT ;
    USE SIGNAL ;
    ANTENNADIFFAREA 0.708600 ;
    PORT
      LAYER Metal2 ;
        RECT 95.320 53.360 95.720 53.760 ;
    END
  END Tile_X0Y0_NN4BEG[14]
  PIN Tile_X0Y0_NN4BEG[15]
    DIRECTION OUTPUT ;
    USE SIGNAL ;
    ANTENNADIFFAREA 0.708600 ;
    PORT
      LAYER Metal2 ;
        RECT 96.280 53.360 96.680 53.760 ;
    END
  END Tile_X0Y0_NN4BEG[15]
  PIN Tile_X0Y0_NN4BEG[1]
    DIRECTION OUTPUT ;
    USE SIGNAL ;
    ANTENNADIFFAREA 0.708600 ;
    PORT
      LAYER Metal2 ;
        RECT 82.840 53.360 83.240 53.760 ;
    END
  END Tile_X0Y0_NN4BEG[1]
  PIN Tile_X0Y0_NN4BEG[2]
    DIRECTION OUTPUT ;
    USE SIGNAL ;
    ANTENNADIFFAREA 0.708600 ;
    PORT
      LAYER Metal2 ;
        RECT 83.800 53.360 84.200 53.760 ;
    END
  END Tile_X0Y0_NN4BEG[2]
  PIN Tile_X0Y0_NN4BEG[3]
    DIRECTION OUTPUT ;
    USE SIGNAL ;
    ANTENNADIFFAREA 0.708600 ;
    PORT
      LAYER Metal2 ;
        RECT 84.760 53.360 85.160 53.760 ;
    END
  END Tile_X0Y0_NN4BEG[3]
  PIN Tile_X0Y0_NN4BEG[4]
    DIRECTION OUTPUT ;
    USE SIGNAL ;
    ANTENNADIFFAREA 0.708600 ;
    PORT
      LAYER Metal2 ;
        RECT 85.720 53.360 86.120 53.760 ;
    END
  END Tile_X0Y0_NN4BEG[4]
  PIN Tile_X0Y0_NN4BEG[5]
    DIRECTION OUTPUT ;
    USE SIGNAL ;
    ANTENNADIFFAREA 0.708600 ;
    PORT
      LAYER Metal2 ;
        RECT 86.680 53.360 87.080 53.760 ;
    END
  END Tile_X0Y0_NN4BEG[5]
  PIN Tile_X0Y0_NN4BEG[6]
    DIRECTION OUTPUT ;
    USE SIGNAL ;
    ANTENNADIFFAREA 0.708600 ;
    PORT
      LAYER Metal2 ;
        RECT 87.640 53.360 88.040 53.760 ;
    END
  END Tile_X0Y0_NN4BEG[6]
  PIN Tile_X0Y0_NN4BEG[7]
    DIRECTION OUTPUT ;
    USE SIGNAL ;
    ANTENNADIFFAREA 0.708600 ;
    PORT
      LAYER Metal2 ;
        RECT 88.600 53.360 89.000 53.760 ;
    END
  END Tile_X0Y0_NN4BEG[7]
  PIN Tile_X0Y0_NN4BEG[8]
    DIRECTION OUTPUT ;
    USE SIGNAL ;
    ANTENNADIFFAREA 0.708600 ;
    PORT
      LAYER Metal2 ;
        RECT 89.560 53.360 89.960 53.760 ;
    END
  END Tile_X0Y0_NN4BEG[8]
  PIN Tile_X0Y0_NN4BEG[9]
    DIRECTION OUTPUT ;
    USE SIGNAL ;
    ANTENNADIFFAREA 0.708600 ;
    PORT
      LAYER Metal2 ;
        RECT 90.520 53.360 90.920 53.760 ;
    END
  END Tile_X0Y0_NN4BEG[9]
  PIN Tile_X0Y0_S1END[0]
    DIRECTION INPUT ;
    USE SIGNAL ;
    ANTENNAGATEAREA 0.471900 ;
    PORT
      LAYER Metal2 ;
        RECT 98.200 53.360 98.600 53.760 ;
    END
  END Tile_X0Y0_S1END[0]
  PIN Tile_X0Y0_S1END[1]
    DIRECTION INPUT ;
    USE SIGNAL ;
    ANTENNAGATEAREA 0.471900 ;
    PORT
      LAYER Metal2 ;
        RECT 99.160 53.360 99.560 53.760 ;
    END
  END Tile_X0Y0_S1END[1]
  PIN Tile_X0Y0_S1END[2]
    DIRECTION INPUT ;
    USE SIGNAL ;
    ANTENNAGATEAREA 0.468000 ;
    PORT
      LAYER Metal2 ;
        RECT 100.120 53.360 100.520 53.760 ;
    END
  END Tile_X0Y0_S1END[2]
  PIN Tile_X0Y0_S1END[3]
    DIRECTION INPUT ;
    USE SIGNAL ;
    ANTENNAGATEAREA 0.468000 ;
    PORT
      LAYER Metal2 ;
        RECT 101.080 53.360 101.480 53.760 ;
    END
  END Tile_X0Y0_S1END[3]
  PIN Tile_X0Y0_S2END[0]
    DIRECTION INPUT ;
    USE SIGNAL ;
    ANTENNAGATEAREA 0.468000 ;
    PORT
      LAYER Metal2 ;
        RECT 109.720 53.360 110.120 53.760 ;
    END
  END Tile_X0Y0_S2END[0]
  PIN Tile_X0Y0_S2END[1]
    DIRECTION INPUT ;
    USE SIGNAL ;
    ANTENNAGATEAREA 0.468000 ;
    PORT
      LAYER Metal2 ;
        RECT 110.680 53.360 111.080 53.760 ;
    END
  END Tile_X0Y0_S2END[1]
  PIN Tile_X0Y0_S2END[2]
    DIRECTION INPUT ;
    USE SIGNAL ;
    ANTENNAGATEAREA 0.468000 ;
    PORT
      LAYER Metal2 ;
        RECT 111.640 53.360 112.040 53.760 ;
    END
  END Tile_X0Y0_S2END[2]
  PIN Tile_X0Y0_S2END[3]
    DIRECTION INPUT ;
    USE SIGNAL ;
    ANTENNAGATEAREA 0.468000 ;
    PORT
      LAYER Metal2 ;
        RECT 112.600 53.360 113.000 53.760 ;
    END
  END Tile_X0Y0_S2END[3]
  PIN Tile_X0Y0_S2END[4]
    DIRECTION INPUT ;
    USE SIGNAL ;
    ANTENNAGATEAREA 0.468000 ;
    PORT
      LAYER Metal2 ;
        RECT 113.560 53.360 113.960 53.760 ;
    END
  END Tile_X0Y0_S2END[4]
  PIN Tile_X0Y0_S2END[5]
    DIRECTION INPUT ;
    USE SIGNAL ;
    ANTENNAGATEAREA 0.468000 ;
    PORT
      LAYER Metal2 ;
        RECT 114.520 53.360 114.920 53.760 ;
    END
  END Tile_X0Y0_S2END[5]
  PIN Tile_X0Y0_S2END[6]
    DIRECTION INPUT ;
    USE SIGNAL ;
    ANTENNAGATEAREA 0.468000 ;
    PORT
      LAYER Metal2 ;
        RECT 115.480 53.360 115.880 53.760 ;
    END
  END Tile_X0Y0_S2END[6]
  PIN Tile_X0Y0_S2END[7]
    DIRECTION INPUT ;
    USE SIGNAL ;
    ANTENNAGATEAREA 0.468000 ;
    PORT
      LAYER Metal2 ;
        RECT 116.440 53.360 116.840 53.760 ;
    END
  END Tile_X0Y0_S2END[7]
  PIN Tile_X0Y0_S2MID[0]
    DIRECTION INPUT ;
    USE SIGNAL ;
    ANTENNAGATEAREA 0.471900 ;
    PORT
      LAYER Metal2 ;
        RECT 102.040 53.360 102.440 53.760 ;
    END
  END Tile_X0Y0_S2MID[0]
  PIN Tile_X0Y0_S2MID[1]
    DIRECTION INPUT ;
    USE SIGNAL ;
    ANTENNAGATEAREA 0.471900 ;
    PORT
      LAYER Metal2 ;
        RECT 103.000 53.360 103.400 53.760 ;
    END
  END Tile_X0Y0_S2MID[1]
  PIN Tile_X0Y0_S2MID[2]
    DIRECTION INPUT ;
    USE SIGNAL ;
    ANTENNAGATEAREA 0.471900 ;
    PORT
      LAYER Metal2 ;
        RECT 103.960 53.360 104.360 53.760 ;
    END
  END Tile_X0Y0_S2MID[2]
  PIN Tile_X0Y0_S2MID[3]
    DIRECTION INPUT ;
    USE SIGNAL ;
    ANTENNAGATEAREA 0.471900 ;
    PORT
      LAYER Metal2 ;
        RECT 104.920 53.360 105.320 53.760 ;
    END
  END Tile_X0Y0_S2MID[3]
  PIN Tile_X0Y0_S2MID[4]
    DIRECTION INPUT ;
    USE SIGNAL ;
    ANTENNAGATEAREA 0.471900 ;
    PORT
      LAYER Metal2 ;
        RECT 105.880 53.360 106.280 53.760 ;
    END
  END Tile_X0Y0_S2MID[4]
  PIN Tile_X0Y0_S2MID[5]
    DIRECTION INPUT ;
    USE SIGNAL ;
    ANTENNAGATEAREA 0.471900 ;
    PORT
      LAYER Metal2 ;
        RECT 106.840 53.360 107.240 53.760 ;
    END
  END Tile_X0Y0_S2MID[5]
  PIN Tile_X0Y0_S2MID[6]
    DIRECTION INPUT ;
    USE SIGNAL ;
    ANTENNAGATEAREA 0.471900 ;
    PORT
      LAYER Metal2 ;
        RECT 107.800 53.360 108.200 53.760 ;
    END
  END Tile_X0Y0_S2MID[6]
  PIN Tile_X0Y0_S2MID[7]
    DIRECTION INPUT ;
    USE SIGNAL ;
    ANTENNAGATEAREA 0.471900 ;
    PORT
      LAYER Metal2 ;
        RECT 108.760 53.360 109.160 53.760 ;
    END
  END Tile_X0Y0_S2MID[7]
  PIN Tile_X0Y0_S4END[0]
    DIRECTION INPUT ;
    USE SIGNAL ;
    ANTENNAGATEAREA 0.422500 ;
    PORT
      LAYER Metal2 ;
        RECT 117.400 53.360 117.800 53.760 ;
    END
  END Tile_X0Y0_S4END[0]
  PIN Tile_X0Y0_S4END[10]
    DIRECTION INPUT ;
    USE SIGNAL ;
    ANTENNAGATEAREA 0.468000 ;
    PORT
      LAYER Metal2 ;
        RECT 127.000 53.360 127.400 53.760 ;
    END
  END Tile_X0Y0_S4END[10]
  PIN Tile_X0Y0_S4END[11]
    DIRECTION INPUT ;
    USE SIGNAL ;
    ANTENNAGATEAREA 0.468000 ;
    PORT
      LAYER Metal2 ;
        RECT 127.960 53.360 128.360 53.760 ;
    END
  END Tile_X0Y0_S4END[11]
  PIN Tile_X0Y0_S4END[12]
    DIRECTION INPUT ;
    USE SIGNAL ;
    ANTENNAGATEAREA 0.468000 ;
    PORT
      LAYER Metal2 ;
        RECT 128.920 53.360 129.320 53.760 ;
    END
  END Tile_X0Y0_S4END[12]
  PIN Tile_X0Y0_S4END[13]
    DIRECTION INPUT ;
    USE SIGNAL ;
    ANTENNAGATEAREA 0.468000 ;
    PORT
      LAYER Metal2 ;
        RECT 129.880 53.360 130.280 53.760 ;
    END
  END Tile_X0Y0_S4END[13]
  PIN Tile_X0Y0_S4END[14]
    DIRECTION INPUT ;
    USE SIGNAL ;
    ANTENNAGATEAREA 0.468000 ;
    PORT
      LAYER Metal2 ;
        RECT 130.840 53.360 131.240 53.760 ;
    END
  END Tile_X0Y0_S4END[14]
  PIN Tile_X0Y0_S4END[15]
    DIRECTION INPUT ;
    USE SIGNAL ;
    ANTENNAGATEAREA 0.468000 ;
    PORT
      LAYER Metal2 ;
        RECT 131.800 53.360 132.200 53.760 ;
    END
  END Tile_X0Y0_S4END[15]
  PIN Tile_X0Y0_S4END[1]
    DIRECTION INPUT ;
    USE SIGNAL ;
    ANTENNAGATEAREA 0.422500 ;
    PORT
      LAYER Metal2 ;
        RECT 118.360 53.360 118.760 53.760 ;
    END
  END Tile_X0Y0_S4END[1]
  PIN Tile_X0Y0_S4END[2]
    DIRECTION INPUT ;
    USE SIGNAL ;
    ANTENNAGATEAREA 0.422500 ;
    PORT
      LAYER Metal2 ;
        RECT 119.320 53.360 119.720 53.760 ;
    END
  END Tile_X0Y0_S4END[2]
  PIN Tile_X0Y0_S4END[3]
    DIRECTION INPUT ;
    USE SIGNAL ;
    ANTENNAGATEAREA 0.422500 ;
    PORT
      LAYER Metal2 ;
        RECT 120.280 53.360 120.680 53.760 ;
    END
  END Tile_X0Y0_S4END[3]
  PIN Tile_X0Y0_S4END[4]
    DIRECTION INPUT ;
    USE SIGNAL ;
    ANTENNAGATEAREA 0.422500 ;
    PORT
      LAYER Metal2 ;
        RECT 121.240 53.360 121.640 53.760 ;
    END
  END Tile_X0Y0_S4END[4]
  PIN Tile_X0Y0_S4END[5]
    DIRECTION INPUT ;
    USE SIGNAL ;
    ANTENNAGATEAREA 0.422500 ;
    PORT
      LAYER Metal2 ;
        RECT 122.200 53.360 122.600 53.760 ;
    END
  END Tile_X0Y0_S4END[5]
  PIN Tile_X0Y0_S4END[6]
    DIRECTION INPUT ;
    USE SIGNAL ;
    ANTENNAGATEAREA 0.709800 ;
    PORT
      LAYER Metal2 ;
        RECT 123.160 53.360 123.560 53.760 ;
    END
  END Tile_X0Y0_S4END[6]
  PIN Tile_X0Y0_S4END[7]
    DIRECTION INPUT ;
    USE SIGNAL ;
    ANTENNAGATEAREA 0.709800 ;
    PORT
      LAYER Metal2 ;
        RECT 124.120 53.360 124.520 53.760 ;
    END
  END Tile_X0Y0_S4END[7]
  PIN Tile_X0Y0_S4END[8]
    DIRECTION INPUT ;
    USE SIGNAL ;
    ANTENNAGATEAREA 0.709800 ;
    PORT
      LAYER Metal2 ;
        RECT 125.080 53.360 125.480 53.760 ;
    END
  END Tile_X0Y0_S4END[8]
  PIN Tile_X0Y0_S4END[9]
    DIRECTION INPUT ;
    USE SIGNAL ;
    ANTENNAGATEAREA 0.709800 ;
    PORT
      LAYER Metal2 ;
        RECT 126.040 53.360 126.440 53.760 ;
    END
  END Tile_X0Y0_S4END[9]
  PIN Tile_X0Y0_SS4END[0]
    DIRECTION INPUT ;
    USE SIGNAL ;
    ANTENNAGATEAREA 0.422500 ;
    PORT
      LAYER Metal2 ;
        RECT 132.760 53.360 133.160 53.760 ;
    END
  END Tile_X0Y0_SS4END[0]
  PIN Tile_X0Y0_SS4END[10]
    DIRECTION INPUT ;
    USE SIGNAL ;
    ANTENNAGATEAREA 0.468000 ;
    PORT
      LAYER Metal2 ;
        RECT 142.360 53.360 142.760 53.760 ;
    END
  END Tile_X0Y0_SS4END[10]
  PIN Tile_X0Y0_SS4END[11]
    DIRECTION INPUT ;
    USE SIGNAL ;
    ANTENNAGATEAREA 0.468000 ;
    PORT
      LAYER Metal2 ;
        RECT 143.320 53.360 143.720 53.760 ;
    END
  END Tile_X0Y0_SS4END[11]
  PIN Tile_X0Y0_SS4END[12]
    DIRECTION INPUT ;
    USE SIGNAL ;
    ANTENNAGATEAREA 0.468000 ;
    PORT
      LAYER Metal2 ;
        RECT 144.280 53.360 144.680 53.760 ;
    END
  END Tile_X0Y0_SS4END[12]
  PIN Tile_X0Y0_SS4END[13]
    DIRECTION INPUT ;
    USE SIGNAL ;
    ANTENNAGATEAREA 0.468000 ;
    PORT
      LAYER Metal2 ;
        RECT 145.240 53.360 145.640 53.760 ;
    END
  END Tile_X0Y0_SS4END[13]
  PIN Tile_X0Y0_SS4END[14]
    DIRECTION INPUT ;
    USE SIGNAL ;
    ANTENNAGATEAREA 0.468000 ;
    PORT
      LAYER Metal2 ;
        RECT 146.200 53.360 146.600 53.760 ;
    END
  END Tile_X0Y0_SS4END[14]
  PIN Tile_X0Y0_SS4END[15]
    DIRECTION INPUT ;
    USE SIGNAL ;
    ANTENNAGATEAREA 0.468000 ;
    PORT
      LAYER Metal2 ;
        RECT 147.160 53.360 147.560 53.760 ;
    END
  END Tile_X0Y0_SS4END[15]
  PIN Tile_X0Y0_SS4END[1]
    DIRECTION INPUT ;
    USE SIGNAL ;
    ANTENNAGATEAREA 0.422500 ;
    PORT
      LAYER Metal2 ;
        RECT 133.720 53.360 134.120 53.760 ;
    END
  END Tile_X0Y0_SS4END[1]
  PIN Tile_X0Y0_SS4END[2]
    DIRECTION INPUT ;
    USE SIGNAL ;
    ANTENNAGATEAREA 0.422500 ;
    PORT
      LAYER Metal2 ;
        RECT 134.680 53.360 135.080 53.760 ;
    END
  END Tile_X0Y0_SS4END[2]
  PIN Tile_X0Y0_SS4END[3]
    DIRECTION INPUT ;
    USE SIGNAL ;
    ANTENNAGATEAREA 0.422500 ;
    PORT
      LAYER Metal2 ;
        RECT 135.640 53.360 136.040 53.760 ;
    END
  END Tile_X0Y0_SS4END[3]
  PIN Tile_X0Y0_SS4END[4]
    DIRECTION INPUT ;
    USE SIGNAL ;
    ANTENNAGATEAREA 0.422500 ;
    PORT
      LAYER Metal2 ;
        RECT 136.600 53.360 137.000 53.760 ;
    END
  END Tile_X0Y0_SS4END[4]
  PIN Tile_X0Y0_SS4END[5]
    DIRECTION INPUT ;
    USE SIGNAL ;
    ANTENNAGATEAREA 0.422500 ;
    PORT
      LAYER Metal2 ;
        RECT 137.560 53.360 137.960 53.760 ;
    END
  END Tile_X0Y0_SS4END[5]
  PIN Tile_X0Y0_SS4END[6]
    DIRECTION INPUT ;
    USE SIGNAL ;
    ANTENNAGATEAREA 0.483600 ;
    PORT
      LAYER Metal2 ;
        RECT 138.520 53.360 138.920 53.760 ;
    END
  END Tile_X0Y0_SS4END[6]
  PIN Tile_X0Y0_SS4END[7]
    DIRECTION INPUT ;
    USE SIGNAL ;
    ANTENNAGATEAREA 0.483600 ;
    PORT
      LAYER Metal2 ;
        RECT 139.480 53.360 139.880 53.760 ;
    END
  END Tile_X0Y0_SS4END[7]
  PIN Tile_X0Y0_SS4END[8]
    DIRECTION INPUT ;
    USE SIGNAL ;
    ANTENNAGATEAREA 0.483600 ;
    PORT
      LAYER Metal2 ;
        RECT 140.440 53.360 140.840 53.760 ;
    END
  END Tile_X0Y0_SS4END[8]
  PIN Tile_X0Y0_SS4END[9]
    DIRECTION INPUT ;
    USE SIGNAL ;
    ANTENNAGATEAREA 0.483600 ;
    PORT
      LAYER Metal2 ;
        RECT 141.400 53.360 141.800 53.760 ;
    END
  END Tile_X0Y0_SS4END[9]
  PIN Tile_X0Y0_UserCLK
    DIRECTION INPUT ;
    USE SIGNAL ;
    ANTENNAGATEAREA 0.180700 ;
    PORT
      LAYER Metal2 ;
        RECT 3.160 0.000 3.560 0.400 ;
    END
  END Tile_X0Y0_UserCLK
  PIN Tile_X0Y0_UserCLKo
    DIRECTION OUTPUT ;
    USE SIGNAL ;
    ANTENNADIFFAREA 0.708600 ;
    PORT
      LAYER Metal2 ;
        RECT 148.120 53.360 148.520 53.760 ;
    END
  END Tile_X0Y0_UserCLKo
  PIN Tile_X1Y0_Co
    DIRECTION OUTPUT ;
    USE SIGNAL ;
    ANTENNADIFFAREA 0.299200 ;
    PORT
      LAYER Metal2 ;
        RECT 312.280 53.360 312.680 53.760 ;
    END
  END Tile_X1Y0_Co
  PIN Tile_X1Y0_FrameStrobe[0]
    DIRECTION INPUT ;
    USE SIGNAL ;
    ANTENNAGATEAREA 6.753500 ;
    PORT
      LAYER Metal2 ;
        RECT 172.120 0.000 172.520 0.400 ;
    END
  END Tile_X1Y0_FrameStrobe[0]
  PIN Tile_X1Y0_FrameStrobe[10]
    DIRECTION INPUT ;
    USE SIGNAL ;
    ANTENNAGATEAREA 0.180700 ;
    PORT
      LAYER Metal2 ;
        RECT 248.920 0.000 249.320 0.400 ;
    END
  END Tile_X1Y0_FrameStrobe[10]
  PIN Tile_X1Y0_FrameStrobe[11]
    DIRECTION INPUT ;
    USE SIGNAL ;
    ANTENNAGATEAREA 0.180700 ;
    PORT
      LAYER Metal2 ;
        RECT 256.600 0.000 257.000 0.400 ;
    END
  END Tile_X1Y0_FrameStrobe[11]
  PIN Tile_X1Y0_FrameStrobe[12]
    DIRECTION INPUT ;
    USE SIGNAL ;
    ANTENNAGATEAREA 0.180700 ;
    PORT
      LAYER Metal2 ;
        RECT 264.280 0.000 264.680 0.400 ;
    END
  END Tile_X1Y0_FrameStrobe[12]
  PIN Tile_X1Y0_FrameStrobe[13]
    DIRECTION INPUT ;
    USE SIGNAL ;
    ANTENNAGATEAREA 0.180700 ;
    PORT
      LAYER Metal2 ;
        RECT 271.960 0.000 272.360 0.400 ;
    END
  END Tile_X1Y0_FrameStrobe[13]
  PIN Tile_X1Y0_FrameStrobe[14]
    DIRECTION INPUT ;
    USE SIGNAL ;
    ANTENNAGATEAREA 0.180700 ;
    PORT
      LAYER Metal2 ;
        RECT 279.640 0.000 280.040 0.400 ;
    END
  END Tile_X1Y0_FrameStrobe[14]
  PIN Tile_X1Y0_FrameStrobe[15]
    DIRECTION INPUT ;
    USE SIGNAL ;
    ANTENNAGATEAREA 0.180700 ;
    PORT
      LAYER Metal2 ;
        RECT 287.320 0.000 287.720 0.400 ;
    END
  END Tile_X1Y0_FrameStrobe[15]
  PIN Tile_X1Y0_FrameStrobe[16]
    DIRECTION INPUT ;
    USE SIGNAL ;
    ANTENNAGATEAREA 0.180700 ;
    PORT
      LAYER Metal2 ;
        RECT 295.000 0.000 295.400 0.400 ;
    END
  END Tile_X1Y0_FrameStrobe[16]
  PIN Tile_X1Y0_FrameStrobe[17]
    DIRECTION INPUT ;
    USE SIGNAL ;
    ANTENNAGATEAREA 0.180700 ;
    PORT
      LAYER Metal2 ;
        RECT 302.680 0.000 303.080 0.400 ;
    END
  END Tile_X1Y0_FrameStrobe[17]
  PIN Tile_X1Y0_FrameStrobe[18]
    DIRECTION INPUT ;
    USE SIGNAL ;
    ANTENNAGATEAREA 0.180700 ;
    PORT
      LAYER Metal2 ;
        RECT 310.360 0.000 310.760 0.400 ;
    END
  END Tile_X1Y0_FrameStrobe[18]
  PIN Tile_X1Y0_FrameStrobe[19]
    DIRECTION INPUT ;
    USE SIGNAL ;
    ANTENNAGATEAREA 0.180700 ;
    PORT
      LAYER Metal2 ;
        RECT 318.040 0.000 318.440 0.400 ;
    END
  END Tile_X1Y0_FrameStrobe[19]
  PIN Tile_X1Y0_FrameStrobe[1]
    DIRECTION INPUT ;
    USE SIGNAL ;
    ANTENNAGATEAREA 6.753500 ;
    PORT
      LAYER Metal2 ;
        RECT 179.800 0.000 180.200 0.400 ;
    END
  END Tile_X1Y0_FrameStrobe[1]
  PIN Tile_X1Y0_FrameStrobe[2]
    DIRECTION INPUT ;
    USE SIGNAL ;
    ANTENNAGATEAREA 4.699500 ;
    PORT
      LAYER Metal2 ;
        RECT 187.480 0.000 187.880 0.400 ;
    END
  END Tile_X1Y0_FrameStrobe[2]
  PIN Tile_X1Y0_FrameStrobe[3]
    DIRECTION INPUT ;
    USE SIGNAL ;
    ANTENNAGATEAREA 0.180700 ;
    PORT
      LAYER Metal2 ;
        RECT 195.160 0.000 195.560 0.400 ;
    END
  END Tile_X1Y0_FrameStrobe[3]
  PIN Tile_X1Y0_FrameStrobe[4]
    DIRECTION INPUT ;
    USE SIGNAL ;
    ANTENNAGATEAREA 0.180700 ;
    PORT
      LAYER Metal2 ;
        RECT 202.840 0.000 203.240 0.400 ;
    END
  END Tile_X1Y0_FrameStrobe[4]
  PIN Tile_X1Y0_FrameStrobe[5]
    DIRECTION INPUT ;
    USE SIGNAL ;
    ANTENNAGATEAREA 0.180700 ;
    PORT
      LAYER Metal2 ;
        RECT 210.520 0.000 210.920 0.400 ;
    END
  END Tile_X1Y0_FrameStrobe[5]
  PIN Tile_X1Y0_FrameStrobe[6]
    DIRECTION INPUT ;
    USE SIGNAL ;
    ANTENNAGATEAREA 0.180700 ;
    PORT
      LAYER Metal2 ;
        RECT 218.200 0.000 218.600 0.400 ;
    END
  END Tile_X1Y0_FrameStrobe[6]
  PIN Tile_X1Y0_FrameStrobe[7]
    DIRECTION INPUT ;
    USE SIGNAL ;
    ANTENNAGATEAREA 0.180700 ;
    PORT
      LAYER Metal2 ;
        RECT 225.880 0.000 226.280 0.400 ;
    END
  END Tile_X1Y0_FrameStrobe[7]
  PIN Tile_X1Y0_FrameStrobe[8]
    DIRECTION INPUT ;
    USE SIGNAL ;
    ANTENNAGATEAREA 0.180700 ;
    PORT
      LAYER Metal2 ;
        RECT 233.560 0.000 233.960 0.400 ;
    END
  END Tile_X1Y0_FrameStrobe[8]
  PIN Tile_X1Y0_FrameStrobe[9]
    DIRECTION INPUT ;
    USE SIGNAL ;
    ANTENNAGATEAREA 0.180700 ;
    PORT
      LAYER Metal2 ;
        RECT 241.240 0.000 241.640 0.400 ;
    END
  END Tile_X1Y0_FrameStrobe[9]
  PIN Tile_X1Y0_FrameStrobe_O[0]
    DIRECTION OUTPUT ;
    USE SIGNAL ;
    ANTENNADIFFAREA 0.708600 ;
    PORT
      LAYER Metal2 ;
        RECT 364.120 53.360 364.520 53.760 ;
    END
  END Tile_X1Y0_FrameStrobe_O[0]
  PIN Tile_X1Y0_FrameStrobe_O[10]
    DIRECTION OUTPUT ;
    USE SIGNAL ;
    ANTENNADIFFAREA 0.708600 ;
    PORT
      LAYER Metal2 ;
        RECT 373.720 53.360 374.120 53.760 ;
    END
  END Tile_X1Y0_FrameStrobe_O[10]
  PIN Tile_X1Y0_FrameStrobe_O[11]
    DIRECTION OUTPUT ;
    USE SIGNAL ;
    ANTENNADIFFAREA 0.708600 ;
    PORT
      LAYER Metal2 ;
        RECT 374.680 53.360 375.080 53.760 ;
    END
  END Tile_X1Y0_FrameStrobe_O[11]
  PIN Tile_X1Y0_FrameStrobe_O[12]
    DIRECTION OUTPUT ;
    USE SIGNAL ;
    ANTENNADIFFAREA 0.708600 ;
    PORT
      LAYER Metal2 ;
        RECT 375.640 53.360 376.040 53.760 ;
    END
  END Tile_X1Y0_FrameStrobe_O[12]
  PIN Tile_X1Y0_FrameStrobe_O[13]
    DIRECTION OUTPUT ;
    USE SIGNAL ;
    ANTENNADIFFAREA 0.708600 ;
    PORT
      LAYER Metal2 ;
        RECT 376.600 53.360 377.000 53.760 ;
    END
  END Tile_X1Y0_FrameStrobe_O[13]
  PIN Tile_X1Y0_FrameStrobe_O[14]
    DIRECTION OUTPUT ;
    USE SIGNAL ;
    ANTENNADIFFAREA 0.708600 ;
    PORT
      LAYER Metal2 ;
        RECT 377.560 53.360 377.960 53.760 ;
    END
  END Tile_X1Y0_FrameStrobe_O[14]
  PIN Tile_X1Y0_FrameStrobe_O[15]
    DIRECTION OUTPUT ;
    USE SIGNAL ;
    ANTENNADIFFAREA 0.708600 ;
    PORT
      LAYER Metal2 ;
        RECT 378.520 53.360 378.920 53.760 ;
    END
  END Tile_X1Y0_FrameStrobe_O[15]
  PIN Tile_X1Y0_FrameStrobe_O[16]
    DIRECTION OUTPUT ;
    USE SIGNAL ;
    ANTENNADIFFAREA 0.708600 ;
    PORT
      LAYER Metal2 ;
        RECT 379.480 53.360 379.880 53.760 ;
    END
  END Tile_X1Y0_FrameStrobe_O[16]
  PIN Tile_X1Y0_FrameStrobe_O[17]
    DIRECTION OUTPUT ;
    USE SIGNAL ;
    ANTENNADIFFAREA 0.708600 ;
    PORT
      LAYER Metal2 ;
        RECT 380.440 53.360 380.840 53.760 ;
    END
  END Tile_X1Y0_FrameStrobe_O[17]
  PIN Tile_X1Y0_FrameStrobe_O[18]
    DIRECTION OUTPUT ;
    USE SIGNAL ;
    ANTENNADIFFAREA 0.708600 ;
    PORT
      LAYER Metal2 ;
        RECT 381.400 53.360 381.800 53.760 ;
    END
  END Tile_X1Y0_FrameStrobe_O[18]
  PIN Tile_X1Y0_FrameStrobe_O[19]
    DIRECTION OUTPUT ;
    USE SIGNAL ;
    ANTENNADIFFAREA 0.708600 ;
    PORT
      LAYER Metal2 ;
        RECT 382.360 53.360 382.760 53.760 ;
    END
  END Tile_X1Y0_FrameStrobe_O[19]
  PIN Tile_X1Y0_FrameStrobe_O[1]
    DIRECTION OUTPUT ;
    USE SIGNAL ;
    ANTENNADIFFAREA 0.708600 ;
    PORT
      LAYER Metal2 ;
        RECT 365.080 53.360 365.480 53.760 ;
    END
  END Tile_X1Y0_FrameStrobe_O[1]
  PIN Tile_X1Y0_FrameStrobe_O[2]
    DIRECTION OUTPUT ;
    USE SIGNAL ;
    ANTENNADIFFAREA 0.708600 ;
    PORT
      LAYER Metal2 ;
        RECT 366.040 53.360 366.440 53.760 ;
    END
  END Tile_X1Y0_FrameStrobe_O[2]
  PIN Tile_X1Y0_FrameStrobe_O[3]
    DIRECTION OUTPUT ;
    USE SIGNAL ;
    ANTENNADIFFAREA 0.708600 ;
    PORT
      LAYER Metal2 ;
        RECT 367.000 53.360 367.400 53.760 ;
    END
  END Tile_X1Y0_FrameStrobe_O[3]
  PIN Tile_X1Y0_FrameStrobe_O[4]
    DIRECTION OUTPUT ;
    USE SIGNAL ;
    ANTENNADIFFAREA 0.708600 ;
    PORT
      LAYER Metal2 ;
        RECT 367.960 53.360 368.360 53.760 ;
    END
  END Tile_X1Y0_FrameStrobe_O[4]
  PIN Tile_X1Y0_FrameStrobe_O[5]
    DIRECTION OUTPUT ;
    USE SIGNAL ;
    ANTENNADIFFAREA 0.708600 ;
    PORT
      LAYER Metal2 ;
        RECT 368.920 53.360 369.320 53.760 ;
    END
  END Tile_X1Y0_FrameStrobe_O[5]
  PIN Tile_X1Y0_FrameStrobe_O[6]
    DIRECTION OUTPUT ;
    USE SIGNAL ;
    ANTENNADIFFAREA 0.708600 ;
    PORT
      LAYER Metal2 ;
        RECT 369.880 53.360 370.280 53.760 ;
    END
  END Tile_X1Y0_FrameStrobe_O[6]
  PIN Tile_X1Y0_FrameStrobe_O[7]
    DIRECTION OUTPUT ;
    USE SIGNAL ;
    ANTENNADIFFAREA 0.708600 ;
    PORT
      LAYER Metal2 ;
        RECT 370.840 53.360 371.240 53.760 ;
    END
  END Tile_X1Y0_FrameStrobe_O[7]
  PIN Tile_X1Y0_FrameStrobe_O[8]
    DIRECTION OUTPUT ;
    USE SIGNAL ;
    ANTENNADIFFAREA 0.708600 ;
    PORT
      LAYER Metal2 ;
        RECT 371.800 53.360 372.200 53.760 ;
    END
  END Tile_X1Y0_FrameStrobe_O[8]
  PIN Tile_X1Y0_FrameStrobe_O[9]
    DIRECTION OUTPUT ;
    USE SIGNAL ;
    ANTENNADIFFAREA 0.708600 ;
    PORT
      LAYER Metal2 ;
        RECT 372.760 53.360 373.160 53.760 ;
    END
  END Tile_X1Y0_FrameStrobe_O[9]
  PIN Tile_X1Y0_N1BEG[0]
    DIRECTION OUTPUT ;
    USE SIGNAL ;
    ANTENNADIFFAREA 0.708600 ;
    PORT
      LAYER Metal2 ;
        RECT 262.360 53.360 262.760 53.760 ;
    END
  END Tile_X1Y0_N1BEG[0]
  PIN Tile_X1Y0_N1BEG[1]
    DIRECTION OUTPUT ;
    USE SIGNAL ;
    ANTENNADIFFAREA 0.708600 ;
    PORT
      LAYER Metal2 ;
        RECT 263.320 53.360 263.720 53.760 ;
    END
  END Tile_X1Y0_N1BEG[1]
  PIN Tile_X1Y0_N1BEG[2]
    DIRECTION OUTPUT ;
    USE SIGNAL ;
    ANTENNADIFFAREA 0.708600 ;
    PORT
      LAYER Metal2 ;
        RECT 264.280 53.360 264.680 53.760 ;
    END
  END Tile_X1Y0_N1BEG[2]
  PIN Tile_X1Y0_N1BEG[3]
    DIRECTION OUTPUT ;
    USE SIGNAL ;
    ANTENNADIFFAREA 0.708600 ;
    PORT
      LAYER Metal2 ;
        RECT 265.240 53.360 265.640 53.760 ;
    END
  END Tile_X1Y0_N1BEG[3]
  PIN Tile_X1Y0_N2BEG[0]
    DIRECTION OUTPUT ;
    USE SIGNAL ;
    ANTENNADIFFAREA 0.708600 ;
    PORT
      LAYER Metal2 ;
        RECT 266.200 53.360 266.600 53.760 ;
    END
  END Tile_X1Y0_N2BEG[0]
  PIN Tile_X1Y0_N2BEG[1]
    DIRECTION OUTPUT ;
    USE SIGNAL ;
    ANTENNADIFFAREA 0.708600 ;
    PORT
      LAYER Metal2 ;
        RECT 267.160 53.360 267.560 53.760 ;
    END
  END Tile_X1Y0_N2BEG[1]
  PIN Tile_X1Y0_N2BEG[2]
    DIRECTION OUTPUT ;
    USE SIGNAL ;
    ANTENNADIFFAREA 0.708600 ;
    PORT
      LAYER Metal2 ;
        RECT 268.120 53.360 268.520 53.760 ;
    END
  END Tile_X1Y0_N2BEG[2]
  PIN Tile_X1Y0_N2BEG[3]
    DIRECTION OUTPUT ;
    USE SIGNAL ;
    ANTENNADIFFAREA 0.708600 ;
    PORT
      LAYER Metal2 ;
        RECT 269.080 53.360 269.480 53.760 ;
    END
  END Tile_X1Y0_N2BEG[3]
  PIN Tile_X1Y0_N2BEG[4]
    DIRECTION OUTPUT ;
    USE SIGNAL ;
    ANTENNADIFFAREA 0.708600 ;
    PORT
      LAYER Metal2 ;
        RECT 270.040 53.360 270.440 53.760 ;
    END
  END Tile_X1Y0_N2BEG[4]
  PIN Tile_X1Y0_N2BEG[5]
    DIRECTION OUTPUT ;
    USE SIGNAL ;
    ANTENNADIFFAREA 0.708600 ;
    PORT
      LAYER Metal2 ;
        RECT 271.000 53.360 271.400 53.760 ;
    END
  END Tile_X1Y0_N2BEG[5]
  PIN Tile_X1Y0_N2BEG[6]
    DIRECTION OUTPUT ;
    USE SIGNAL ;
    ANTENNADIFFAREA 0.708600 ;
    PORT
      LAYER Metal2 ;
        RECT 271.960 53.360 272.360 53.760 ;
    END
  END Tile_X1Y0_N2BEG[6]
  PIN Tile_X1Y0_N2BEG[7]
    DIRECTION OUTPUT ;
    USE SIGNAL ;
    ANTENNADIFFAREA 0.708600 ;
    PORT
      LAYER Metal2 ;
        RECT 272.920 53.360 273.320 53.760 ;
    END
  END Tile_X1Y0_N2BEG[7]
  PIN Tile_X1Y0_N2BEGb[0]
    DIRECTION OUTPUT ;
    USE SIGNAL ;
    ANTENNADIFFAREA 0.708600 ;
    PORT
      LAYER Metal2 ;
        RECT 273.880 53.360 274.280 53.760 ;
    END
  END Tile_X1Y0_N2BEGb[0]
  PIN Tile_X1Y0_N2BEGb[1]
    DIRECTION OUTPUT ;
    USE SIGNAL ;
    ANTENNADIFFAREA 0.708600 ;
    PORT
      LAYER Metal2 ;
        RECT 274.840 53.360 275.240 53.760 ;
    END
  END Tile_X1Y0_N2BEGb[1]
  PIN Tile_X1Y0_N2BEGb[2]
    DIRECTION OUTPUT ;
    USE SIGNAL ;
    ANTENNADIFFAREA 0.708600 ;
    PORT
      LAYER Metal2 ;
        RECT 275.800 53.360 276.200 53.760 ;
    END
  END Tile_X1Y0_N2BEGb[2]
  PIN Tile_X1Y0_N2BEGb[3]
    DIRECTION OUTPUT ;
    USE SIGNAL ;
    ANTENNADIFFAREA 0.708600 ;
    PORT
      LAYER Metal2 ;
        RECT 276.760 53.360 277.160 53.760 ;
    END
  END Tile_X1Y0_N2BEGb[3]
  PIN Tile_X1Y0_N2BEGb[4]
    DIRECTION OUTPUT ;
    USE SIGNAL ;
    ANTENNADIFFAREA 0.708600 ;
    PORT
      LAYER Metal2 ;
        RECT 277.720 53.360 278.120 53.760 ;
    END
  END Tile_X1Y0_N2BEGb[4]
  PIN Tile_X1Y0_N2BEGb[5]
    DIRECTION OUTPUT ;
    USE SIGNAL ;
    ANTENNADIFFAREA 0.708600 ;
    PORT
      LAYER Metal2 ;
        RECT 278.680 53.360 279.080 53.760 ;
    END
  END Tile_X1Y0_N2BEGb[5]
  PIN Tile_X1Y0_N2BEGb[6]
    DIRECTION OUTPUT ;
    USE SIGNAL ;
    ANTENNADIFFAREA 0.708600 ;
    PORT
      LAYER Metal2 ;
        RECT 279.640 53.360 280.040 53.760 ;
    END
  END Tile_X1Y0_N2BEGb[6]
  PIN Tile_X1Y0_N2BEGb[7]
    DIRECTION OUTPUT ;
    USE SIGNAL ;
    ANTENNADIFFAREA 0.708600 ;
    PORT
      LAYER Metal2 ;
        RECT 280.600 53.360 281.000 53.760 ;
    END
  END Tile_X1Y0_N2BEGb[7]
  PIN Tile_X1Y0_N4BEG[0]
    DIRECTION OUTPUT ;
    USE SIGNAL ;
    ANTENNADIFFAREA 0.708600 ;
    PORT
      LAYER Metal2 ;
        RECT 281.560 53.360 281.960 53.760 ;
    END
  END Tile_X1Y0_N4BEG[0]
  PIN Tile_X1Y0_N4BEG[10]
    DIRECTION OUTPUT ;
    USE SIGNAL ;
    ANTENNADIFFAREA 0.708600 ;
    PORT
      LAYER Metal2 ;
        RECT 291.160 53.360 291.560 53.760 ;
    END
  END Tile_X1Y0_N4BEG[10]
  PIN Tile_X1Y0_N4BEG[11]
    DIRECTION OUTPUT ;
    USE SIGNAL ;
    ANTENNADIFFAREA 0.708600 ;
    PORT
      LAYER Metal2 ;
        RECT 292.120 53.360 292.520 53.760 ;
    END
  END Tile_X1Y0_N4BEG[11]
  PIN Tile_X1Y0_N4BEG[12]
    DIRECTION OUTPUT ;
    USE SIGNAL ;
    ANTENNADIFFAREA 0.708600 ;
    PORT
      LAYER Metal2 ;
        RECT 293.080 53.360 293.480 53.760 ;
    END
  END Tile_X1Y0_N4BEG[12]
  PIN Tile_X1Y0_N4BEG[13]
    DIRECTION OUTPUT ;
    USE SIGNAL ;
    ANTENNADIFFAREA 0.708600 ;
    PORT
      LAYER Metal2 ;
        RECT 294.040 53.360 294.440 53.760 ;
    END
  END Tile_X1Y0_N4BEG[13]
  PIN Tile_X1Y0_N4BEG[14]
    DIRECTION OUTPUT ;
    USE SIGNAL ;
    ANTENNADIFFAREA 0.708600 ;
    PORT
      LAYER Metal2 ;
        RECT 295.000 53.360 295.400 53.760 ;
    END
  END Tile_X1Y0_N4BEG[14]
  PIN Tile_X1Y0_N4BEG[15]
    DIRECTION OUTPUT ;
    USE SIGNAL ;
    ANTENNADIFFAREA 0.708600 ;
    PORT
      LAYER Metal2 ;
        RECT 295.960 53.360 296.360 53.760 ;
    END
  END Tile_X1Y0_N4BEG[15]
  PIN Tile_X1Y0_N4BEG[1]
    DIRECTION OUTPUT ;
    USE SIGNAL ;
    ANTENNADIFFAREA 0.708600 ;
    PORT
      LAYER Metal2 ;
        RECT 282.520 53.360 282.920 53.760 ;
    END
  END Tile_X1Y0_N4BEG[1]
  PIN Tile_X1Y0_N4BEG[2]
    DIRECTION OUTPUT ;
    USE SIGNAL ;
    ANTENNADIFFAREA 0.708600 ;
    PORT
      LAYER Metal2 ;
        RECT 283.480 53.360 283.880 53.760 ;
    END
  END Tile_X1Y0_N4BEG[2]
  PIN Tile_X1Y0_N4BEG[3]
    DIRECTION OUTPUT ;
    USE SIGNAL ;
    ANTENNADIFFAREA 0.708600 ;
    PORT
      LAYER Metal2 ;
        RECT 284.440 53.360 284.840 53.760 ;
    END
  END Tile_X1Y0_N4BEG[3]
  PIN Tile_X1Y0_N4BEG[4]
    DIRECTION OUTPUT ;
    USE SIGNAL ;
    ANTENNADIFFAREA 0.708600 ;
    PORT
      LAYER Metal2 ;
        RECT 285.400 53.360 285.800 53.760 ;
    END
  END Tile_X1Y0_N4BEG[4]
  PIN Tile_X1Y0_N4BEG[5]
    DIRECTION OUTPUT ;
    USE SIGNAL ;
    ANTENNADIFFAREA 0.708600 ;
    PORT
      LAYER Metal2 ;
        RECT 286.360 53.360 286.760 53.760 ;
    END
  END Tile_X1Y0_N4BEG[5]
  PIN Tile_X1Y0_N4BEG[6]
    DIRECTION OUTPUT ;
    USE SIGNAL ;
    ANTENNADIFFAREA 0.708600 ;
    PORT
      LAYER Metal2 ;
        RECT 287.320 53.360 287.720 53.760 ;
    END
  END Tile_X1Y0_N4BEG[6]
  PIN Tile_X1Y0_N4BEG[7]
    DIRECTION OUTPUT ;
    USE SIGNAL ;
    ANTENNADIFFAREA 0.708600 ;
    PORT
      LAYER Metal2 ;
        RECT 288.280 53.360 288.680 53.760 ;
    END
  END Tile_X1Y0_N4BEG[7]
  PIN Tile_X1Y0_N4BEG[8]
    DIRECTION OUTPUT ;
    USE SIGNAL ;
    ANTENNADIFFAREA 0.708600 ;
    PORT
      LAYER Metal2 ;
        RECT 289.240 53.360 289.640 53.760 ;
    END
  END Tile_X1Y0_N4BEG[8]
  PIN Tile_X1Y0_N4BEG[9]
    DIRECTION OUTPUT ;
    USE SIGNAL ;
    ANTENNADIFFAREA 0.708600 ;
    PORT
      LAYER Metal2 ;
        RECT 290.200 53.360 290.600 53.760 ;
    END
  END Tile_X1Y0_N4BEG[9]
  PIN Tile_X1Y0_NN4BEG[0]
    DIRECTION OUTPUT ;
    USE SIGNAL ;
    ANTENNADIFFAREA 0.708600 ;
    PORT
      LAYER Metal2 ;
        RECT 296.920 53.360 297.320 53.760 ;
    END
  END Tile_X1Y0_NN4BEG[0]
  PIN Tile_X1Y0_NN4BEG[10]
    DIRECTION OUTPUT ;
    USE SIGNAL ;
    ANTENNADIFFAREA 0.708600 ;
    PORT
      LAYER Metal2 ;
        RECT 306.520 53.360 306.920 53.760 ;
    END
  END Tile_X1Y0_NN4BEG[10]
  PIN Tile_X1Y0_NN4BEG[11]
    DIRECTION OUTPUT ;
    USE SIGNAL ;
    ANTENNADIFFAREA 0.708600 ;
    PORT
      LAYER Metal2 ;
        RECT 307.480 53.360 307.880 53.760 ;
    END
  END Tile_X1Y0_NN4BEG[11]
  PIN Tile_X1Y0_NN4BEG[12]
    DIRECTION OUTPUT ;
    USE SIGNAL ;
    ANTENNADIFFAREA 0.708600 ;
    PORT
      LAYER Metal2 ;
        RECT 308.440 53.360 308.840 53.760 ;
    END
  END Tile_X1Y0_NN4BEG[12]
  PIN Tile_X1Y0_NN4BEG[13]
    DIRECTION OUTPUT ;
    USE SIGNAL ;
    ANTENNADIFFAREA 0.708600 ;
    PORT
      LAYER Metal2 ;
        RECT 309.400 53.360 309.800 53.760 ;
    END
  END Tile_X1Y0_NN4BEG[13]
  PIN Tile_X1Y0_NN4BEG[14]
    DIRECTION OUTPUT ;
    USE SIGNAL ;
    ANTENNADIFFAREA 0.708600 ;
    PORT
      LAYER Metal2 ;
        RECT 310.360 53.360 310.760 53.760 ;
    END
  END Tile_X1Y0_NN4BEG[14]
  PIN Tile_X1Y0_NN4BEG[15]
    DIRECTION OUTPUT ;
    USE SIGNAL ;
    ANTENNADIFFAREA 0.708600 ;
    PORT
      LAYER Metal2 ;
        RECT 311.320 53.360 311.720 53.760 ;
    END
  END Tile_X1Y0_NN4BEG[15]
  PIN Tile_X1Y0_NN4BEG[1]
    DIRECTION OUTPUT ;
    USE SIGNAL ;
    ANTENNADIFFAREA 0.708600 ;
    PORT
      LAYER Metal2 ;
        RECT 297.880 53.360 298.280 53.760 ;
    END
  END Tile_X1Y0_NN4BEG[1]
  PIN Tile_X1Y0_NN4BEG[2]
    DIRECTION OUTPUT ;
    USE SIGNAL ;
    ANTENNADIFFAREA 0.708600 ;
    PORT
      LAYER Metal2 ;
        RECT 298.840 53.360 299.240 53.760 ;
    END
  END Tile_X1Y0_NN4BEG[2]
  PIN Tile_X1Y0_NN4BEG[3]
    DIRECTION OUTPUT ;
    USE SIGNAL ;
    ANTENNADIFFAREA 0.708600 ;
    PORT
      LAYER Metal2 ;
        RECT 299.800 53.360 300.200 53.760 ;
    END
  END Tile_X1Y0_NN4BEG[3]
  PIN Tile_X1Y0_NN4BEG[4]
    DIRECTION OUTPUT ;
    USE SIGNAL ;
    ANTENNADIFFAREA 0.708600 ;
    PORT
      LAYER Metal2 ;
        RECT 300.760 53.360 301.160 53.760 ;
    END
  END Tile_X1Y0_NN4BEG[4]
  PIN Tile_X1Y0_NN4BEG[5]
    DIRECTION OUTPUT ;
    USE SIGNAL ;
    ANTENNADIFFAREA 0.708600 ;
    PORT
      LAYER Metal2 ;
        RECT 301.720 53.360 302.120 53.760 ;
    END
  END Tile_X1Y0_NN4BEG[5]
  PIN Tile_X1Y0_NN4BEG[6]
    DIRECTION OUTPUT ;
    USE SIGNAL ;
    ANTENNADIFFAREA 0.708600 ;
    PORT
      LAYER Metal2 ;
        RECT 302.680 53.360 303.080 53.760 ;
    END
  END Tile_X1Y0_NN4BEG[6]
  PIN Tile_X1Y0_NN4BEG[7]
    DIRECTION OUTPUT ;
    USE SIGNAL ;
    ANTENNADIFFAREA 0.708600 ;
    PORT
      LAYER Metal2 ;
        RECT 303.640 53.360 304.040 53.760 ;
    END
  END Tile_X1Y0_NN4BEG[7]
  PIN Tile_X1Y0_NN4BEG[8]
    DIRECTION OUTPUT ;
    USE SIGNAL ;
    ANTENNADIFFAREA 0.708600 ;
    PORT
      LAYER Metal2 ;
        RECT 304.600 53.360 305.000 53.760 ;
    END
  END Tile_X1Y0_NN4BEG[8]
  PIN Tile_X1Y0_NN4BEG[9]
    DIRECTION OUTPUT ;
    USE SIGNAL ;
    ANTENNADIFFAREA 0.708600 ;
    PORT
      LAYER Metal2 ;
        RECT 305.560 53.360 305.960 53.760 ;
    END
  END Tile_X1Y0_NN4BEG[9]
  PIN Tile_X1Y0_S1END[0]
    DIRECTION INPUT ;
    USE SIGNAL ;
    ANTENNAGATEAREA 0.704600 ;
    PORT
      LAYER Metal2 ;
        RECT 313.240 53.360 313.640 53.760 ;
    END
  END Tile_X1Y0_S1END[0]
  PIN Tile_X1Y0_S1END[1]
    DIRECTION INPUT ;
    USE SIGNAL ;
    ANTENNAGATEAREA 0.696800 ;
    PORT
      LAYER Metal2 ;
        RECT 314.200 53.360 314.600 53.760 ;
    END
  END Tile_X1Y0_S1END[1]
  PIN Tile_X1Y0_S1END[2]
    DIRECTION INPUT ;
    USE SIGNAL ;
    ANTENNAGATEAREA 0.696800 ;
    PORT
      LAYER Metal2 ;
        RECT 315.160 53.360 315.560 53.760 ;
    END
  END Tile_X1Y0_S1END[2]
  PIN Tile_X1Y0_S1END[3]
    DIRECTION INPUT ;
    USE SIGNAL ;
    ANTENNAGATEAREA 0.696800 ;
    PORT
      LAYER Metal2 ;
        RECT 316.120 53.360 316.520 53.760 ;
    END
  END Tile_X1Y0_S1END[3]
  PIN Tile_X1Y0_S2END[0]
    DIRECTION INPUT ;
    USE SIGNAL ;
    ANTENNAGATEAREA 0.226200 ;
    PORT
      LAYER Metal2 ;
        RECT 324.760 53.360 325.160 53.760 ;
    END
  END Tile_X1Y0_S2END[0]
  PIN Tile_X1Y0_S2END[1]
    DIRECTION INPUT ;
    USE SIGNAL ;
    ANTENNAGATEAREA 0.226200 ;
    PORT
      LAYER Metal2 ;
        RECT 325.720 53.360 326.120 53.760 ;
    END
  END Tile_X1Y0_S2END[1]
  PIN Tile_X1Y0_S2END[2]
    DIRECTION INPUT ;
    USE SIGNAL ;
    ANTENNAGATEAREA 0.226200 ;
    PORT
      LAYER Metal2 ;
        RECT 326.680 53.360 327.080 53.760 ;
    END
  END Tile_X1Y0_S2END[2]
  PIN Tile_X1Y0_S2END[3]
    DIRECTION INPUT ;
    USE SIGNAL ;
    ANTENNAGATEAREA 0.226200 ;
    PORT
      LAYER Metal2 ;
        RECT 327.640 53.360 328.040 53.760 ;
    END
  END Tile_X1Y0_S2END[3]
  PIN Tile_X1Y0_S2END[4]
    DIRECTION INPUT ;
    USE SIGNAL ;
    ANTENNAGATEAREA 0.226200 ;
    PORT
      LAYER Metal2 ;
        RECT 328.600 53.360 329.000 53.760 ;
    END
  END Tile_X1Y0_S2END[4]
  PIN Tile_X1Y0_S2END[5]
    DIRECTION INPUT ;
    USE SIGNAL ;
    ANTENNAGATEAREA 0.226200 ;
    PORT
      LAYER Metal2 ;
        RECT 329.560 53.360 329.960 53.760 ;
    END
  END Tile_X1Y0_S2END[5]
  PIN Tile_X1Y0_S2END[6]
    DIRECTION INPUT ;
    USE SIGNAL ;
    ANTENNAGATEAREA 0.226200 ;
    PORT
      LAYER Metal2 ;
        RECT 330.520 53.360 330.920 53.760 ;
    END
  END Tile_X1Y0_S2END[6]
  PIN Tile_X1Y0_S2END[7]
    DIRECTION INPUT ;
    USE SIGNAL ;
    ANTENNAGATEAREA 0.226200 ;
    PORT
      LAYER Metal2 ;
        RECT 331.480 53.360 331.880 53.760 ;
    END
  END Tile_X1Y0_S2END[7]
  PIN Tile_X1Y0_S2MID[0]
    DIRECTION INPUT ;
    USE SIGNAL ;
    ANTENNAGATEAREA 0.241800 ;
    PORT
      LAYER Metal2 ;
        RECT 317.080 53.360 317.480 53.760 ;
    END
  END Tile_X1Y0_S2MID[0]
  PIN Tile_X1Y0_S2MID[1]
    DIRECTION INPUT ;
    USE SIGNAL ;
    ANTENNAGATEAREA 0.468000 ;
    PORT
      LAYER Metal2 ;
        RECT 318.040 53.360 318.440 53.760 ;
    END
  END Tile_X1Y0_S2MID[1]
  PIN Tile_X1Y0_S2MID[2]
    DIRECTION INPUT ;
    USE SIGNAL ;
    ANTENNAGATEAREA 0.241800 ;
    PORT
      LAYER Metal2 ;
        RECT 319.000 53.360 319.400 53.760 ;
    END
  END Tile_X1Y0_S2MID[2]
  PIN Tile_X1Y0_S2MID[3]
    DIRECTION INPUT ;
    USE SIGNAL ;
    ANTENNAGATEAREA 0.468000 ;
    PORT
      LAYER Metal2 ;
        RECT 319.960 53.360 320.360 53.760 ;
    END
  END Tile_X1Y0_S2MID[3]
  PIN Tile_X1Y0_S2MID[4]
    DIRECTION INPUT ;
    USE SIGNAL ;
    ANTENNAGATEAREA 0.226200 ;
    PORT
      LAYER Metal2 ;
        RECT 320.920 53.360 321.320 53.760 ;
    END
  END Tile_X1Y0_S2MID[4]
  PIN Tile_X1Y0_S2MID[5]
    DIRECTION INPUT ;
    USE SIGNAL ;
    ANTENNAGATEAREA 0.226200 ;
    PORT
      LAYER Metal2 ;
        RECT 321.880 53.360 322.280 53.760 ;
    END
  END Tile_X1Y0_S2MID[5]
  PIN Tile_X1Y0_S2MID[6]
    DIRECTION INPUT ;
    USE SIGNAL ;
    ANTENNAGATEAREA 0.226200 ;
    PORT
      LAYER Metal2 ;
        RECT 322.840 53.360 323.240 53.760 ;
    END
  END Tile_X1Y0_S2MID[6]
  PIN Tile_X1Y0_S2MID[7]
    DIRECTION INPUT ;
    USE SIGNAL ;
    ANTENNAGATEAREA 0.226200 ;
    PORT
      LAYER Metal2 ;
        RECT 323.800 53.360 324.200 53.760 ;
    END
  END Tile_X1Y0_S2MID[7]
  PIN Tile_X1Y0_S4END[0]
    DIRECTION INPUT ;
    USE SIGNAL ;
    ANTENNAGATEAREA 0.468000 ;
    PORT
      LAYER Metal2 ;
        RECT 332.440 53.360 332.840 53.760 ;
    END
  END Tile_X1Y0_S4END[0]
  PIN Tile_X1Y0_S4END[10]
    DIRECTION INPUT ;
    USE SIGNAL ;
    ANTENNAGATEAREA 0.468000 ;
    PORT
      LAYER Metal2 ;
        RECT 342.040 53.360 342.440 53.760 ;
    END
  END Tile_X1Y0_S4END[10]
  PIN Tile_X1Y0_S4END[11]
    DIRECTION INPUT ;
    USE SIGNAL ;
    ANTENNAGATEAREA 0.468000 ;
    PORT
      LAYER Metal2 ;
        RECT 343.000 53.360 343.400 53.760 ;
    END
  END Tile_X1Y0_S4END[11]
  PIN Tile_X1Y0_S4END[12]
    DIRECTION INPUT ;
    USE SIGNAL ;
    ANTENNAGATEAREA 0.226200 ;
    PORT
      LAYER Metal2 ;
        RECT 343.960 53.360 344.360 53.760 ;
    END
  END Tile_X1Y0_S4END[12]
  PIN Tile_X1Y0_S4END[13]
    DIRECTION INPUT ;
    USE SIGNAL ;
    ANTENNAGATEAREA 0.226200 ;
    PORT
      LAYER Metal2 ;
        RECT 344.920 53.360 345.320 53.760 ;
    END
  END Tile_X1Y0_S4END[13]
  PIN Tile_X1Y0_S4END[14]
    DIRECTION INPUT ;
    USE SIGNAL ;
    ANTENNAGATEAREA 0.226200 ;
    PORT
      LAYER Metal2 ;
        RECT 345.880 53.360 346.280 53.760 ;
    END
  END Tile_X1Y0_S4END[14]
  PIN Tile_X1Y0_S4END[15]
    DIRECTION INPUT ;
    USE SIGNAL ;
    ANTENNAGATEAREA 0.226200 ;
    PORT
      LAYER Metal2 ;
        RECT 346.840 53.360 347.240 53.760 ;
    END
  END Tile_X1Y0_S4END[15]
  PIN Tile_X1Y0_S4END[1]
    DIRECTION INPUT ;
    USE SIGNAL ;
    ANTENNAGATEAREA 0.468000 ;
    PORT
      LAYER Metal2 ;
        RECT 333.400 53.360 333.800 53.760 ;
    END
  END Tile_X1Y0_S4END[1]
  PIN Tile_X1Y0_S4END[2]
    DIRECTION INPUT ;
    USE SIGNAL ;
    ANTENNAGATEAREA 0.468000 ;
    PORT
      LAYER Metal2 ;
        RECT 334.360 53.360 334.760 53.760 ;
    END
  END Tile_X1Y0_S4END[2]
  PIN Tile_X1Y0_S4END[3]
    DIRECTION INPUT ;
    USE SIGNAL ;
    ANTENNAGATEAREA 0.468000 ;
    PORT
      LAYER Metal2 ;
        RECT 335.320 53.360 335.720 53.760 ;
    END
  END Tile_X1Y0_S4END[3]
  PIN Tile_X1Y0_S4END[4]
    DIRECTION INPUT ;
    USE SIGNAL ;
    ANTENNAGATEAREA 0.468000 ;
    PORT
      LAYER Metal2 ;
        RECT 336.280 53.360 336.680 53.760 ;
    END
  END Tile_X1Y0_S4END[4]
  PIN Tile_X1Y0_S4END[5]
    DIRECTION INPUT ;
    USE SIGNAL ;
    ANTENNAGATEAREA 0.468000 ;
    PORT
      LAYER Metal2 ;
        RECT 337.240 53.360 337.640 53.760 ;
    END
  END Tile_X1Y0_S4END[5]
  PIN Tile_X1Y0_S4END[6]
    DIRECTION INPUT ;
    USE SIGNAL ;
    ANTENNAGATEAREA 0.468000 ;
    PORT
      LAYER Metal2 ;
        RECT 338.200 53.360 338.600 53.760 ;
    END
  END Tile_X1Y0_S4END[6]
  PIN Tile_X1Y0_S4END[7]
    DIRECTION INPUT ;
    USE SIGNAL ;
    ANTENNAGATEAREA 0.468000 ;
    PORT
      LAYER Metal2 ;
        RECT 339.160 53.360 339.560 53.760 ;
    END
  END Tile_X1Y0_S4END[7]
  PIN Tile_X1Y0_S4END[8]
    DIRECTION INPUT ;
    USE SIGNAL ;
    ANTENNAGATEAREA 0.468000 ;
    PORT
      LAYER Metal2 ;
        RECT 340.120 53.360 340.520 53.760 ;
    END
  END Tile_X1Y0_S4END[8]
  PIN Tile_X1Y0_S4END[9]
    DIRECTION INPUT ;
    USE SIGNAL ;
    ANTENNAGATEAREA 0.468000 ;
    PORT
      LAYER Metal2 ;
        RECT 341.080 53.360 341.480 53.760 ;
    END
  END Tile_X1Y0_S4END[9]
  PIN Tile_X1Y0_SS4END[0]
    DIRECTION INPUT ;
    USE SIGNAL ;
    ANTENNAGATEAREA 0.505200 ;
    PORT
      LAYER Metal2 ;
        RECT 347.800 53.360 348.200 53.760 ;
    END
  END Tile_X1Y0_SS4END[0]
  PIN Tile_X1Y0_SS4END[10]
    DIRECTION INPUT ;
    USE SIGNAL ;
    ANTENNAGATEAREA 0.505200 ;
    PORT
      LAYER Metal2 ;
        RECT 357.400 53.360 357.800 53.760 ;
    END
  END Tile_X1Y0_SS4END[10]
  PIN Tile_X1Y0_SS4END[11]
    DIRECTION INPUT ;
    USE SIGNAL ;
    ANTENNAGATEAREA 0.505200 ;
    PORT
      LAYER Metal2 ;
        RECT 358.360 53.360 358.760 53.760 ;
    END
  END Tile_X1Y0_SS4END[11]
  PIN Tile_X1Y0_SS4END[12]
    DIRECTION INPUT ;
    USE SIGNAL ;
    ANTENNAGATEAREA 0.226200 ;
    PORT
      LAYER Metal2 ;
        RECT 359.320 53.360 359.720 53.760 ;
    END
  END Tile_X1Y0_SS4END[12]
  PIN Tile_X1Y0_SS4END[13]
    DIRECTION INPUT ;
    USE SIGNAL ;
    ANTENNAGATEAREA 0.226200 ;
    PORT
      LAYER Metal2 ;
        RECT 360.280 53.360 360.680 53.760 ;
    END
  END Tile_X1Y0_SS4END[13]
  PIN Tile_X1Y0_SS4END[14]
    DIRECTION INPUT ;
    USE SIGNAL ;
    ANTENNAGATEAREA 0.226200 ;
    PORT
      LAYER Metal2 ;
        RECT 361.240 53.360 361.640 53.760 ;
    END
  END Tile_X1Y0_SS4END[14]
  PIN Tile_X1Y0_SS4END[15]
    DIRECTION INPUT ;
    USE SIGNAL ;
    ANTENNAGATEAREA 0.226200 ;
    PORT
      LAYER Metal2 ;
        RECT 362.200 53.360 362.600 53.760 ;
    END
  END Tile_X1Y0_SS4END[15]
  PIN Tile_X1Y0_SS4END[1]
    DIRECTION INPUT ;
    USE SIGNAL ;
    ANTENNAGATEAREA 0.505200 ;
    PORT
      LAYER Metal2 ;
        RECT 348.760 53.360 349.160 53.760 ;
    END
  END Tile_X1Y0_SS4END[1]
  PIN Tile_X1Y0_SS4END[2]
    DIRECTION INPUT ;
    USE SIGNAL ;
    ANTENNAGATEAREA 0.505200 ;
    PORT
      LAYER Metal2 ;
        RECT 349.720 53.360 350.120 53.760 ;
    END
  END Tile_X1Y0_SS4END[2]
  PIN Tile_X1Y0_SS4END[3]
    DIRECTION INPUT ;
    USE SIGNAL ;
    ANTENNAGATEAREA 0.505200 ;
    PORT
      LAYER Metal2 ;
        RECT 350.680 53.360 351.080 53.760 ;
    END
  END Tile_X1Y0_SS4END[3]
  PIN Tile_X1Y0_SS4END[4]
    DIRECTION INPUT ;
    USE SIGNAL ;
    ANTENNAGATEAREA 0.505200 ;
    PORT
      LAYER Metal2 ;
        RECT 351.640 53.360 352.040 53.760 ;
    END
  END Tile_X1Y0_SS4END[4]
  PIN Tile_X1Y0_SS4END[5]
    DIRECTION INPUT ;
    USE SIGNAL ;
    ANTENNAGATEAREA 0.505200 ;
    PORT
      LAYER Metal2 ;
        RECT 352.600 53.360 353.000 53.760 ;
    END
  END Tile_X1Y0_SS4END[5]
  PIN Tile_X1Y0_SS4END[6]
    DIRECTION INPUT ;
    USE SIGNAL ;
    ANTENNAGATEAREA 0.505200 ;
    PORT
      LAYER Metal2 ;
        RECT 353.560 53.360 353.960 53.760 ;
    END
  END Tile_X1Y0_SS4END[6]
  PIN Tile_X1Y0_SS4END[7]
    DIRECTION INPUT ;
    USE SIGNAL ;
    ANTENNAGATEAREA 0.505200 ;
    PORT
      LAYER Metal2 ;
        RECT 354.520 53.360 354.920 53.760 ;
    END
  END Tile_X1Y0_SS4END[7]
  PIN Tile_X1Y0_SS4END[8]
    DIRECTION INPUT ;
    USE SIGNAL ;
    ANTENNAGATEAREA 0.505200 ;
    PORT
      LAYER Metal2 ;
        RECT 355.480 53.360 355.880 53.760 ;
    END
  END Tile_X1Y0_SS4END[8]
  PIN Tile_X1Y0_SS4END[9]
    DIRECTION INPUT ;
    USE SIGNAL ;
    ANTENNAGATEAREA 0.505200 ;
    PORT
      LAYER Metal2 ;
        RECT 356.440 53.360 356.840 53.760 ;
    END
  END Tile_X1Y0_SS4END[9]
  PIN Tile_X1Y0_UserCLK
    DIRECTION INPUT ;
    USE SIGNAL ;
    ANTENNAGATEAREA 0.180700 ;
    PORT
      LAYER Metal2 ;
        RECT 164.440 0.000 164.840 0.400 ;
    END
  END Tile_X1Y0_UserCLK
  PIN Tile_X1Y0_UserCLKo
    DIRECTION OUTPUT ;
    USE SIGNAL ;
    ANTENNADIFFAREA 0.708600 ;
    PORT
      LAYER Metal2 ;
        RECT 363.160 53.360 363.560 53.760 ;
    END
  END Tile_X1Y0_UserCLKo
  PIN Tile_X2Y0_Co
    DIRECTION OUTPUT ;
    USE SIGNAL ;
    ANTENNADIFFAREA 0.299200 ;
    PORT
      LAYER Metal2 ;
        RECT 527.320 53.360 527.720 53.760 ;
    END
  END Tile_X2Y0_Co
  PIN Tile_X2Y0_FrameData_O[0]
    DIRECTION OUTPUT ;
    USE SIGNAL ;
    ANTENNADIFFAREA 0.708600 ;
    PORT
      LAYER Metal3 ;
        RECT 644.720 0.220 645.120 0.620 ;
    END
  END Tile_X2Y0_FrameData_O[0]
  PIN Tile_X2Y0_FrameData_O[10]
    DIRECTION OUTPUT ;
    USE SIGNAL ;
    ANTENNADIFFAREA 0.708600 ;
    PORT
      LAYER Metal3 ;
        RECT 644.720 17.020 645.120 17.420 ;
    END
  END Tile_X2Y0_FrameData_O[10]
  PIN Tile_X2Y0_FrameData_O[11]
    DIRECTION OUTPUT ;
    USE SIGNAL ;
    ANTENNADIFFAREA 0.708600 ;
    PORT
      LAYER Metal3 ;
        RECT 644.720 18.700 645.120 19.100 ;
    END
  END Tile_X2Y0_FrameData_O[11]
  PIN Tile_X2Y0_FrameData_O[12]
    DIRECTION OUTPUT ;
    USE SIGNAL ;
    ANTENNADIFFAREA 0.708600 ;
    PORT
      LAYER Metal3 ;
        RECT 644.720 20.380 645.120 20.780 ;
    END
  END Tile_X2Y0_FrameData_O[12]
  PIN Tile_X2Y0_FrameData_O[13]
    DIRECTION OUTPUT ;
    USE SIGNAL ;
    ANTENNADIFFAREA 0.708600 ;
    PORT
      LAYER Metal3 ;
        RECT 644.720 22.060 645.120 22.460 ;
    END
  END Tile_X2Y0_FrameData_O[13]
  PIN Tile_X2Y0_FrameData_O[14]
    DIRECTION OUTPUT ;
    USE SIGNAL ;
    ANTENNADIFFAREA 0.708600 ;
    PORT
      LAYER Metal3 ;
        RECT 644.720 23.740 645.120 24.140 ;
    END
  END Tile_X2Y0_FrameData_O[14]
  PIN Tile_X2Y0_FrameData_O[15]
    DIRECTION OUTPUT ;
    USE SIGNAL ;
    ANTENNADIFFAREA 0.708600 ;
    PORT
      LAYER Metal3 ;
        RECT 644.720 25.420 645.120 25.820 ;
    END
  END Tile_X2Y0_FrameData_O[15]
  PIN Tile_X2Y0_FrameData_O[16]
    DIRECTION OUTPUT ;
    USE SIGNAL ;
    ANTENNADIFFAREA 0.708600 ;
    PORT
      LAYER Metal3 ;
        RECT 644.720 27.100 645.120 27.500 ;
    END
  END Tile_X2Y0_FrameData_O[16]
  PIN Tile_X2Y0_FrameData_O[17]
    DIRECTION OUTPUT ;
    USE SIGNAL ;
    ANTENNADIFFAREA 0.708600 ;
    PORT
      LAYER Metal3 ;
        RECT 644.720 28.780 645.120 29.180 ;
    END
  END Tile_X2Y0_FrameData_O[17]
  PIN Tile_X2Y0_FrameData_O[18]
    DIRECTION OUTPUT ;
    USE SIGNAL ;
    ANTENNADIFFAREA 0.708600 ;
    PORT
      LAYER Metal3 ;
        RECT 644.720 30.460 645.120 30.860 ;
    END
  END Tile_X2Y0_FrameData_O[18]
  PIN Tile_X2Y0_FrameData_O[19]
    DIRECTION OUTPUT ;
    USE SIGNAL ;
    ANTENNADIFFAREA 0.708600 ;
    PORT
      LAYER Metal3 ;
        RECT 644.720 32.140 645.120 32.540 ;
    END
  END Tile_X2Y0_FrameData_O[19]
  PIN Tile_X2Y0_FrameData_O[1]
    DIRECTION OUTPUT ;
    USE SIGNAL ;
    ANTENNADIFFAREA 0.708600 ;
    PORT
      LAYER Metal3 ;
        RECT 644.720 1.900 645.120 2.300 ;
    END
  END Tile_X2Y0_FrameData_O[1]
  PIN Tile_X2Y0_FrameData_O[20]
    DIRECTION OUTPUT ;
    USE SIGNAL ;
    ANTENNADIFFAREA 0.708600 ;
    PORT
      LAYER Metal3 ;
        RECT 644.720 33.820 645.120 34.220 ;
    END
  END Tile_X2Y0_FrameData_O[20]
  PIN Tile_X2Y0_FrameData_O[21]
    DIRECTION OUTPUT ;
    USE SIGNAL ;
    ANTENNADIFFAREA 0.708600 ;
    PORT
      LAYER Metal3 ;
        RECT 644.720 35.500 645.120 35.900 ;
    END
  END Tile_X2Y0_FrameData_O[21]
  PIN Tile_X2Y0_FrameData_O[22]
    DIRECTION OUTPUT ;
    USE SIGNAL ;
    ANTENNADIFFAREA 0.708600 ;
    PORT
      LAYER Metal3 ;
        RECT 644.720 37.180 645.120 37.580 ;
    END
  END Tile_X2Y0_FrameData_O[22]
  PIN Tile_X2Y0_FrameData_O[23]
    DIRECTION OUTPUT ;
    USE SIGNAL ;
    ANTENNADIFFAREA 0.708600 ;
    PORT
      LAYER Metal3 ;
        RECT 644.720 38.860 645.120 39.260 ;
    END
  END Tile_X2Y0_FrameData_O[23]
  PIN Tile_X2Y0_FrameData_O[24]
    DIRECTION OUTPUT ;
    USE SIGNAL ;
    ANTENNADIFFAREA 0.708600 ;
    PORT
      LAYER Metal3 ;
        RECT 644.720 40.540 645.120 40.940 ;
    END
  END Tile_X2Y0_FrameData_O[24]
  PIN Tile_X2Y0_FrameData_O[25]
    DIRECTION OUTPUT ;
    USE SIGNAL ;
    ANTENNADIFFAREA 0.708600 ;
    PORT
      LAYER Metal3 ;
        RECT 644.720 42.220 645.120 42.620 ;
    END
  END Tile_X2Y0_FrameData_O[25]
  PIN Tile_X2Y0_FrameData_O[26]
    DIRECTION OUTPUT ;
    USE SIGNAL ;
    ANTENNADIFFAREA 0.708600 ;
    PORT
      LAYER Metal3 ;
        RECT 644.720 43.900 645.120 44.300 ;
    END
  END Tile_X2Y0_FrameData_O[26]
  PIN Tile_X2Y0_FrameData_O[27]
    DIRECTION OUTPUT ;
    USE SIGNAL ;
    ANTENNADIFFAREA 0.708600 ;
    PORT
      LAYER Metal3 ;
        RECT 644.720 45.580 645.120 45.980 ;
    END
  END Tile_X2Y0_FrameData_O[27]
  PIN Tile_X2Y0_FrameData_O[28]
    DIRECTION OUTPUT ;
    USE SIGNAL ;
    ANTENNADIFFAREA 0.708600 ;
    PORT
      LAYER Metal3 ;
        RECT 644.720 47.260 645.120 47.660 ;
    END
  END Tile_X2Y0_FrameData_O[28]
  PIN Tile_X2Y0_FrameData_O[29]
    DIRECTION OUTPUT ;
    USE SIGNAL ;
    ANTENNADIFFAREA 0.708600 ;
    PORT
      LAYER Metal3 ;
        RECT 644.720 48.940 645.120 49.340 ;
    END
  END Tile_X2Y0_FrameData_O[29]
  PIN Tile_X2Y0_FrameData_O[2]
    DIRECTION OUTPUT ;
    USE SIGNAL ;
    ANTENNADIFFAREA 0.708600 ;
    PORT
      LAYER Metal3 ;
        RECT 644.720 3.580 645.120 3.980 ;
    END
  END Tile_X2Y0_FrameData_O[2]
  PIN Tile_X2Y0_FrameData_O[30]
    DIRECTION OUTPUT ;
    USE SIGNAL ;
    ANTENNADIFFAREA 0.708600 ;
    PORT
      LAYER Metal3 ;
        RECT 644.720 50.620 645.120 51.020 ;
    END
  END Tile_X2Y0_FrameData_O[30]
  PIN Tile_X2Y0_FrameData_O[31]
    DIRECTION OUTPUT ;
    USE SIGNAL ;
    ANTENNADIFFAREA 0.708600 ;
    PORT
      LAYER Metal3 ;
        RECT 644.720 52.300 645.120 52.700 ;
    END
  END Tile_X2Y0_FrameData_O[31]
  PIN Tile_X2Y0_FrameData_O[3]
    DIRECTION OUTPUT ;
    USE SIGNAL ;
    ANTENNADIFFAREA 0.708600 ;
    PORT
      LAYER Metal3 ;
        RECT 644.720 5.260 645.120 5.660 ;
    END
  END Tile_X2Y0_FrameData_O[3]
  PIN Tile_X2Y0_FrameData_O[4]
    DIRECTION OUTPUT ;
    USE SIGNAL ;
    ANTENNADIFFAREA 0.708600 ;
    PORT
      LAYER Metal3 ;
        RECT 644.720 6.940 645.120 7.340 ;
    END
  END Tile_X2Y0_FrameData_O[4]
  PIN Tile_X2Y0_FrameData_O[5]
    DIRECTION OUTPUT ;
    USE SIGNAL ;
    ANTENNADIFFAREA 0.708600 ;
    PORT
      LAYER Metal3 ;
        RECT 644.720 8.620 645.120 9.020 ;
    END
  END Tile_X2Y0_FrameData_O[5]
  PIN Tile_X2Y0_FrameData_O[6]
    DIRECTION OUTPUT ;
    USE SIGNAL ;
    ANTENNADIFFAREA 0.708600 ;
    PORT
      LAYER Metal3 ;
        RECT 644.720 10.300 645.120 10.700 ;
    END
  END Tile_X2Y0_FrameData_O[6]
  PIN Tile_X2Y0_FrameData_O[7]
    DIRECTION OUTPUT ;
    USE SIGNAL ;
    ANTENNADIFFAREA 0.708600 ;
    PORT
      LAYER Metal3 ;
        RECT 644.720 11.980 645.120 12.380 ;
    END
  END Tile_X2Y0_FrameData_O[7]
  PIN Tile_X2Y0_FrameData_O[8]
    DIRECTION OUTPUT ;
    USE SIGNAL ;
    ANTENNADIFFAREA 0.708600 ;
    PORT
      LAYER Metal3 ;
        RECT 644.720 13.660 645.120 14.060 ;
    END
  END Tile_X2Y0_FrameData_O[8]
  PIN Tile_X2Y0_FrameData_O[9]
    DIRECTION OUTPUT ;
    USE SIGNAL ;
    ANTENNADIFFAREA 0.708600 ;
    PORT
      LAYER Metal3 ;
        RECT 644.720 15.340 645.120 15.740 ;
    END
  END Tile_X2Y0_FrameData_O[9]
  PIN Tile_X2Y0_FrameStrobe[0]
    DIRECTION INPUT ;
    USE SIGNAL ;
    ANTENNAGATEAREA 6.753500 ;
    PORT
      LAYER Metal2 ;
        RECT 333.400 0.000 333.800 0.400 ;
    END
  END Tile_X2Y0_FrameStrobe[0]
  PIN Tile_X2Y0_FrameStrobe[10]
    DIRECTION INPUT ;
    USE SIGNAL ;
    ANTENNAGATEAREA 0.180700 ;
    PORT
      LAYER Metal2 ;
        RECT 410.200 0.000 410.600 0.400 ;
    END
  END Tile_X2Y0_FrameStrobe[10]
  PIN Tile_X2Y0_FrameStrobe[11]
    DIRECTION INPUT ;
    USE SIGNAL ;
    ANTENNAGATEAREA 0.180700 ;
    PORT
      LAYER Metal2 ;
        RECT 417.880 0.000 418.280 0.400 ;
    END
  END Tile_X2Y0_FrameStrobe[11]
  PIN Tile_X2Y0_FrameStrobe[12]
    DIRECTION INPUT ;
    USE SIGNAL ;
    ANTENNAGATEAREA 0.180700 ;
    PORT
      LAYER Metal2 ;
        RECT 425.560 0.000 425.960 0.400 ;
    END
  END Tile_X2Y0_FrameStrobe[12]
  PIN Tile_X2Y0_FrameStrobe[13]
    DIRECTION INPUT ;
    USE SIGNAL ;
    ANTENNAGATEAREA 0.180700 ;
    PORT
      LAYER Metal2 ;
        RECT 433.240 0.000 433.640 0.400 ;
    END
  END Tile_X2Y0_FrameStrobe[13]
  PIN Tile_X2Y0_FrameStrobe[14]
    DIRECTION INPUT ;
    USE SIGNAL ;
    ANTENNAGATEAREA 0.180700 ;
    PORT
      LAYER Metal2 ;
        RECT 440.920 0.000 441.320 0.400 ;
    END
  END Tile_X2Y0_FrameStrobe[14]
  PIN Tile_X2Y0_FrameStrobe[15]
    DIRECTION INPUT ;
    USE SIGNAL ;
    ANTENNAGATEAREA 0.180700 ;
    PORT
      LAYER Metal2 ;
        RECT 448.600 0.000 449.000 0.400 ;
    END
  END Tile_X2Y0_FrameStrobe[15]
  PIN Tile_X2Y0_FrameStrobe[16]
    DIRECTION INPUT ;
    USE SIGNAL ;
    ANTENNAGATEAREA 0.180700 ;
    PORT
      LAYER Metal2 ;
        RECT 456.280 0.000 456.680 0.400 ;
    END
  END Tile_X2Y0_FrameStrobe[16]
  PIN Tile_X2Y0_FrameStrobe[17]
    DIRECTION INPUT ;
    USE SIGNAL ;
    ANTENNAGATEAREA 0.180700 ;
    PORT
      LAYER Metal2 ;
        RECT 463.960 0.000 464.360 0.400 ;
    END
  END Tile_X2Y0_FrameStrobe[17]
  PIN Tile_X2Y0_FrameStrobe[18]
    DIRECTION INPUT ;
    USE SIGNAL ;
    ANTENNAGATEAREA 0.180700 ;
    PORT
      LAYER Metal2 ;
        RECT 471.640 0.000 472.040 0.400 ;
    END
  END Tile_X2Y0_FrameStrobe[18]
  PIN Tile_X2Y0_FrameStrobe[19]
    DIRECTION INPUT ;
    USE SIGNAL ;
    ANTENNAGATEAREA 0.180700 ;
    PORT
      LAYER Metal2 ;
        RECT 479.320 0.000 479.720 0.400 ;
    END
  END Tile_X2Y0_FrameStrobe[19]
  PIN Tile_X2Y0_FrameStrobe[1]
    DIRECTION INPUT ;
    USE SIGNAL ;
    ANTENNAGATEAREA 6.753500 ;
    PORT
      LAYER Metal2 ;
        RECT 341.080 0.000 341.480 0.400 ;
    END
  END Tile_X2Y0_FrameStrobe[1]
  PIN Tile_X2Y0_FrameStrobe[2]
    DIRECTION INPUT ;
    USE SIGNAL ;
    ANTENNAGATEAREA 1.413100 ;
    PORT
      LAYER Metal2 ;
        RECT 348.760 0.000 349.160 0.400 ;
    END
  END Tile_X2Y0_FrameStrobe[2]
  PIN Tile_X2Y0_FrameStrobe[3]
    DIRECTION INPUT ;
    USE SIGNAL ;
    ANTENNAGATEAREA 0.180700 ;
    PORT
      LAYER Metal2 ;
        RECT 356.440 0.000 356.840 0.400 ;
    END
  END Tile_X2Y0_FrameStrobe[3]
  PIN Tile_X2Y0_FrameStrobe[4]
    DIRECTION INPUT ;
    USE SIGNAL ;
    ANTENNAGATEAREA 0.180700 ;
    PORT
      LAYER Metal2 ;
        RECT 364.120 0.000 364.520 0.400 ;
    END
  END Tile_X2Y0_FrameStrobe[4]
  PIN Tile_X2Y0_FrameStrobe[5]
    DIRECTION INPUT ;
    USE SIGNAL ;
    ANTENNAGATEAREA 0.180700 ;
    PORT
      LAYER Metal2 ;
        RECT 371.800 0.000 372.200 0.400 ;
    END
  END Tile_X2Y0_FrameStrobe[5]
  PIN Tile_X2Y0_FrameStrobe[6]
    DIRECTION INPUT ;
    USE SIGNAL ;
    ANTENNAGATEAREA 0.180700 ;
    PORT
      LAYER Metal2 ;
        RECT 379.480 0.000 379.880 0.400 ;
    END
  END Tile_X2Y0_FrameStrobe[6]
  PIN Tile_X2Y0_FrameStrobe[7]
    DIRECTION INPUT ;
    USE SIGNAL ;
    ANTENNAGATEAREA 0.180700 ;
    PORT
      LAYER Metal2 ;
        RECT 387.160 0.000 387.560 0.400 ;
    END
  END Tile_X2Y0_FrameStrobe[7]
  PIN Tile_X2Y0_FrameStrobe[8]
    DIRECTION INPUT ;
    USE SIGNAL ;
    ANTENNAGATEAREA 0.180700 ;
    PORT
      LAYER Metal2 ;
        RECT 394.840 0.000 395.240 0.400 ;
    END
  END Tile_X2Y0_FrameStrobe[8]
  PIN Tile_X2Y0_FrameStrobe[9]
    DIRECTION INPUT ;
    USE SIGNAL ;
    ANTENNAGATEAREA 0.180700 ;
    PORT
      LAYER Metal2 ;
        RECT 402.520 0.000 402.920 0.400 ;
    END
  END Tile_X2Y0_FrameStrobe[9]
  PIN Tile_X2Y0_FrameStrobe_O[0]
    DIRECTION OUTPUT ;
    USE SIGNAL ;
    ANTENNADIFFAREA 0.708600 ;
    PORT
      LAYER Metal2 ;
        RECT 579.160 53.360 579.560 53.760 ;
    END
  END Tile_X2Y0_FrameStrobe_O[0]
  PIN Tile_X2Y0_FrameStrobe_O[10]
    DIRECTION OUTPUT ;
    USE SIGNAL ;
    ANTENNADIFFAREA 0.708600 ;
    PORT
      LAYER Metal2 ;
        RECT 588.760 53.360 589.160 53.760 ;
    END
  END Tile_X2Y0_FrameStrobe_O[10]
  PIN Tile_X2Y0_FrameStrobe_O[11]
    DIRECTION OUTPUT ;
    USE SIGNAL ;
    ANTENNADIFFAREA 0.708600 ;
    PORT
      LAYER Metal2 ;
        RECT 589.720 53.360 590.120 53.760 ;
    END
  END Tile_X2Y0_FrameStrobe_O[11]
  PIN Tile_X2Y0_FrameStrobe_O[12]
    DIRECTION OUTPUT ;
    USE SIGNAL ;
    ANTENNADIFFAREA 0.708600 ;
    PORT
      LAYER Metal2 ;
        RECT 590.680 53.360 591.080 53.760 ;
    END
  END Tile_X2Y0_FrameStrobe_O[12]
  PIN Tile_X2Y0_FrameStrobe_O[13]
    DIRECTION OUTPUT ;
    USE SIGNAL ;
    ANTENNADIFFAREA 0.708600 ;
    PORT
      LAYER Metal2 ;
        RECT 591.640 53.360 592.040 53.760 ;
    END
  END Tile_X2Y0_FrameStrobe_O[13]
  PIN Tile_X2Y0_FrameStrobe_O[14]
    DIRECTION OUTPUT ;
    USE SIGNAL ;
    ANTENNADIFFAREA 0.708600 ;
    PORT
      LAYER Metal2 ;
        RECT 592.600 53.360 593.000 53.760 ;
    END
  END Tile_X2Y0_FrameStrobe_O[14]
  PIN Tile_X2Y0_FrameStrobe_O[15]
    DIRECTION OUTPUT ;
    USE SIGNAL ;
    ANTENNADIFFAREA 0.708600 ;
    PORT
      LAYER Metal2 ;
        RECT 593.560 53.360 593.960 53.760 ;
    END
  END Tile_X2Y0_FrameStrobe_O[15]
  PIN Tile_X2Y0_FrameStrobe_O[16]
    DIRECTION OUTPUT ;
    USE SIGNAL ;
    ANTENNADIFFAREA 0.708600 ;
    PORT
      LAYER Metal2 ;
        RECT 594.520 53.360 594.920 53.760 ;
    END
  END Tile_X2Y0_FrameStrobe_O[16]
  PIN Tile_X2Y0_FrameStrobe_O[17]
    DIRECTION OUTPUT ;
    USE SIGNAL ;
    ANTENNADIFFAREA 0.708600 ;
    PORT
      LAYER Metal2 ;
        RECT 595.480 53.360 595.880 53.760 ;
    END
  END Tile_X2Y0_FrameStrobe_O[17]
  PIN Tile_X2Y0_FrameStrobe_O[18]
    DIRECTION OUTPUT ;
    USE SIGNAL ;
    ANTENNADIFFAREA 0.708600 ;
    PORT
      LAYER Metal2 ;
        RECT 596.440 53.360 596.840 53.760 ;
    END
  END Tile_X2Y0_FrameStrobe_O[18]
  PIN Tile_X2Y0_FrameStrobe_O[19]
    DIRECTION OUTPUT ;
    USE SIGNAL ;
    ANTENNADIFFAREA 0.708600 ;
    PORT
      LAYER Metal2 ;
        RECT 597.400 53.360 597.800 53.760 ;
    END
  END Tile_X2Y0_FrameStrobe_O[19]
  PIN Tile_X2Y0_FrameStrobe_O[1]
    DIRECTION OUTPUT ;
    USE SIGNAL ;
    ANTENNADIFFAREA 0.708600 ;
    PORT
      LAYER Metal2 ;
        RECT 580.120 53.360 580.520 53.760 ;
    END
  END Tile_X2Y0_FrameStrobe_O[1]
  PIN Tile_X2Y0_FrameStrobe_O[2]
    DIRECTION OUTPUT ;
    USE SIGNAL ;
    ANTENNADIFFAREA 0.708600 ;
    PORT
      LAYER Metal2 ;
        RECT 581.080 53.360 581.480 53.760 ;
    END
  END Tile_X2Y0_FrameStrobe_O[2]
  PIN Tile_X2Y0_FrameStrobe_O[3]
    DIRECTION OUTPUT ;
    USE SIGNAL ;
    ANTENNADIFFAREA 0.708600 ;
    PORT
      LAYER Metal2 ;
        RECT 582.040 53.360 582.440 53.760 ;
    END
  END Tile_X2Y0_FrameStrobe_O[3]
  PIN Tile_X2Y0_FrameStrobe_O[4]
    DIRECTION OUTPUT ;
    USE SIGNAL ;
    ANTENNADIFFAREA 0.708600 ;
    PORT
      LAYER Metal2 ;
        RECT 583.000 53.360 583.400 53.760 ;
    END
  END Tile_X2Y0_FrameStrobe_O[4]
  PIN Tile_X2Y0_FrameStrobe_O[5]
    DIRECTION OUTPUT ;
    USE SIGNAL ;
    ANTENNADIFFAREA 0.708600 ;
    PORT
      LAYER Metal2 ;
        RECT 583.960 53.360 584.360 53.760 ;
    END
  END Tile_X2Y0_FrameStrobe_O[5]
  PIN Tile_X2Y0_FrameStrobe_O[6]
    DIRECTION OUTPUT ;
    USE SIGNAL ;
    ANTENNADIFFAREA 0.708600 ;
    PORT
      LAYER Metal2 ;
        RECT 584.920 53.360 585.320 53.760 ;
    END
  END Tile_X2Y0_FrameStrobe_O[6]
  PIN Tile_X2Y0_FrameStrobe_O[7]
    DIRECTION OUTPUT ;
    USE SIGNAL ;
    ANTENNADIFFAREA 0.708600 ;
    PORT
      LAYER Metal2 ;
        RECT 585.880 53.360 586.280 53.760 ;
    END
  END Tile_X2Y0_FrameStrobe_O[7]
  PIN Tile_X2Y0_FrameStrobe_O[8]
    DIRECTION OUTPUT ;
    USE SIGNAL ;
    ANTENNADIFFAREA 0.708600 ;
    PORT
      LAYER Metal2 ;
        RECT 586.840 53.360 587.240 53.760 ;
    END
  END Tile_X2Y0_FrameStrobe_O[8]
  PIN Tile_X2Y0_FrameStrobe_O[9]
    DIRECTION OUTPUT ;
    USE SIGNAL ;
    ANTENNADIFFAREA 0.708600 ;
    PORT
      LAYER Metal2 ;
        RECT 587.800 53.360 588.200 53.760 ;
    END
  END Tile_X2Y0_FrameStrobe_O[9]
  PIN Tile_X2Y0_N1BEG[0]
    DIRECTION OUTPUT ;
    USE SIGNAL ;
    ANTENNADIFFAREA 0.708600 ;
    PORT
      LAYER Metal2 ;
        RECT 477.400 53.360 477.800 53.760 ;
    END
  END Tile_X2Y0_N1BEG[0]
  PIN Tile_X2Y0_N1BEG[1]
    DIRECTION OUTPUT ;
    USE SIGNAL ;
    ANTENNADIFFAREA 0.708600 ;
    PORT
      LAYER Metal2 ;
        RECT 478.360 53.360 478.760 53.760 ;
    END
  END Tile_X2Y0_N1BEG[1]
  PIN Tile_X2Y0_N1BEG[2]
    DIRECTION OUTPUT ;
    USE SIGNAL ;
    ANTENNADIFFAREA 0.708600 ;
    PORT
      LAYER Metal2 ;
        RECT 479.320 53.360 479.720 53.760 ;
    END
  END Tile_X2Y0_N1BEG[2]
  PIN Tile_X2Y0_N1BEG[3]
    DIRECTION OUTPUT ;
    USE SIGNAL ;
    ANTENNADIFFAREA 0.708600 ;
    PORT
      LAYER Metal2 ;
        RECT 480.280 53.360 480.680 53.760 ;
    END
  END Tile_X2Y0_N1BEG[3]
  PIN Tile_X2Y0_N2BEG[0]
    DIRECTION OUTPUT ;
    USE SIGNAL ;
    ANTENNADIFFAREA 0.708600 ;
    PORT
      LAYER Metal2 ;
        RECT 481.240 53.360 481.640 53.760 ;
    END
  END Tile_X2Y0_N2BEG[0]
  PIN Tile_X2Y0_N2BEG[1]
    DIRECTION OUTPUT ;
    USE SIGNAL ;
    ANTENNADIFFAREA 0.708600 ;
    PORT
      LAYER Metal2 ;
        RECT 482.200 53.360 482.600 53.760 ;
    END
  END Tile_X2Y0_N2BEG[1]
  PIN Tile_X2Y0_N2BEG[2]
    DIRECTION OUTPUT ;
    USE SIGNAL ;
    ANTENNADIFFAREA 0.708600 ;
    PORT
      LAYER Metal2 ;
        RECT 483.160 53.360 483.560 53.760 ;
    END
  END Tile_X2Y0_N2BEG[2]
  PIN Tile_X2Y0_N2BEG[3]
    DIRECTION OUTPUT ;
    USE SIGNAL ;
    ANTENNADIFFAREA 0.708600 ;
    PORT
      LAYER Metal2 ;
        RECT 484.120 53.360 484.520 53.760 ;
    END
  END Tile_X2Y0_N2BEG[3]
  PIN Tile_X2Y0_N2BEG[4]
    DIRECTION OUTPUT ;
    USE SIGNAL ;
    ANTENNADIFFAREA 0.708600 ;
    PORT
      LAYER Metal2 ;
        RECT 485.080 53.360 485.480 53.760 ;
    END
  END Tile_X2Y0_N2BEG[4]
  PIN Tile_X2Y0_N2BEG[5]
    DIRECTION OUTPUT ;
    USE SIGNAL ;
    ANTENNADIFFAREA 0.708600 ;
    PORT
      LAYER Metal2 ;
        RECT 486.040 53.360 486.440 53.760 ;
    END
  END Tile_X2Y0_N2BEG[5]
  PIN Tile_X2Y0_N2BEG[6]
    DIRECTION OUTPUT ;
    USE SIGNAL ;
    ANTENNADIFFAREA 0.708600 ;
    PORT
      LAYER Metal2 ;
        RECT 487.000 53.360 487.400 53.760 ;
    END
  END Tile_X2Y0_N2BEG[6]
  PIN Tile_X2Y0_N2BEG[7]
    DIRECTION OUTPUT ;
    USE SIGNAL ;
    ANTENNADIFFAREA 0.708600 ;
    PORT
      LAYER Metal2 ;
        RECT 487.960 53.360 488.360 53.760 ;
    END
  END Tile_X2Y0_N2BEG[7]
  PIN Tile_X2Y0_N2BEGb[0]
    DIRECTION OUTPUT ;
    USE SIGNAL ;
    ANTENNADIFFAREA 0.708600 ;
    PORT
      LAYER Metal2 ;
        RECT 488.920 53.360 489.320 53.760 ;
    END
  END Tile_X2Y0_N2BEGb[0]
  PIN Tile_X2Y0_N2BEGb[1]
    DIRECTION OUTPUT ;
    USE SIGNAL ;
    ANTENNADIFFAREA 0.708600 ;
    PORT
      LAYER Metal2 ;
        RECT 489.880 53.360 490.280 53.760 ;
    END
  END Tile_X2Y0_N2BEGb[1]
  PIN Tile_X2Y0_N2BEGb[2]
    DIRECTION OUTPUT ;
    USE SIGNAL ;
    ANTENNADIFFAREA 0.708600 ;
    PORT
      LAYER Metal2 ;
        RECT 490.840 53.360 491.240 53.760 ;
    END
  END Tile_X2Y0_N2BEGb[2]
  PIN Tile_X2Y0_N2BEGb[3]
    DIRECTION OUTPUT ;
    USE SIGNAL ;
    ANTENNADIFFAREA 0.708600 ;
    PORT
      LAYER Metal2 ;
        RECT 491.800 53.360 492.200 53.760 ;
    END
  END Tile_X2Y0_N2BEGb[3]
  PIN Tile_X2Y0_N2BEGb[4]
    DIRECTION OUTPUT ;
    USE SIGNAL ;
    ANTENNADIFFAREA 0.708600 ;
    PORT
      LAYER Metal2 ;
        RECT 492.760 53.360 493.160 53.760 ;
    END
  END Tile_X2Y0_N2BEGb[4]
  PIN Tile_X2Y0_N2BEGb[5]
    DIRECTION OUTPUT ;
    USE SIGNAL ;
    ANTENNADIFFAREA 0.708600 ;
    PORT
      LAYER Metal2 ;
        RECT 493.720 53.360 494.120 53.760 ;
    END
  END Tile_X2Y0_N2BEGb[5]
  PIN Tile_X2Y0_N2BEGb[6]
    DIRECTION OUTPUT ;
    USE SIGNAL ;
    ANTENNADIFFAREA 0.708600 ;
    PORT
      LAYER Metal2 ;
        RECT 494.680 53.360 495.080 53.760 ;
    END
  END Tile_X2Y0_N2BEGb[6]
  PIN Tile_X2Y0_N2BEGb[7]
    DIRECTION OUTPUT ;
    USE SIGNAL ;
    ANTENNADIFFAREA 0.708600 ;
    PORT
      LAYER Metal2 ;
        RECT 495.640 53.360 496.040 53.760 ;
    END
  END Tile_X2Y0_N2BEGb[7]
  PIN Tile_X2Y0_N4BEG[0]
    DIRECTION OUTPUT ;
    USE SIGNAL ;
    ANTENNADIFFAREA 0.708600 ;
    PORT
      LAYER Metal2 ;
        RECT 496.600 53.360 497.000 53.760 ;
    END
  END Tile_X2Y0_N4BEG[0]
  PIN Tile_X2Y0_N4BEG[10]
    DIRECTION OUTPUT ;
    USE SIGNAL ;
    ANTENNADIFFAREA 0.708600 ;
    PORT
      LAYER Metal2 ;
        RECT 506.200 53.360 506.600 53.760 ;
    END
  END Tile_X2Y0_N4BEG[10]
  PIN Tile_X2Y0_N4BEG[11]
    DIRECTION OUTPUT ;
    USE SIGNAL ;
    ANTENNADIFFAREA 0.708600 ;
    PORT
      LAYER Metal2 ;
        RECT 507.160 53.360 507.560 53.760 ;
    END
  END Tile_X2Y0_N4BEG[11]
  PIN Tile_X2Y0_N4BEG[12]
    DIRECTION OUTPUT ;
    USE SIGNAL ;
    ANTENNADIFFAREA 0.708600 ;
    PORT
      LAYER Metal2 ;
        RECT 508.120 53.360 508.520 53.760 ;
    END
  END Tile_X2Y0_N4BEG[12]
  PIN Tile_X2Y0_N4BEG[13]
    DIRECTION OUTPUT ;
    USE SIGNAL ;
    ANTENNADIFFAREA 0.708600 ;
    PORT
      LAYER Metal2 ;
        RECT 509.080 53.360 509.480 53.760 ;
    END
  END Tile_X2Y0_N4BEG[13]
  PIN Tile_X2Y0_N4BEG[14]
    DIRECTION OUTPUT ;
    USE SIGNAL ;
    ANTENNADIFFAREA 0.708600 ;
    PORT
      LAYER Metal2 ;
        RECT 510.040 53.360 510.440 53.760 ;
    END
  END Tile_X2Y0_N4BEG[14]
  PIN Tile_X2Y0_N4BEG[15]
    DIRECTION OUTPUT ;
    USE SIGNAL ;
    ANTENNADIFFAREA 0.708600 ;
    PORT
      LAYER Metal2 ;
        RECT 511.000 53.360 511.400 53.760 ;
    END
  END Tile_X2Y0_N4BEG[15]
  PIN Tile_X2Y0_N4BEG[1]
    DIRECTION OUTPUT ;
    USE SIGNAL ;
    ANTENNADIFFAREA 0.708600 ;
    PORT
      LAYER Metal2 ;
        RECT 497.560 53.360 497.960 53.760 ;
    END
  END Tile_X2Y0_N4BEG[1]
  PIN Tile_X2Y0_N4BEG[2]
    DIRECTION OUTPUT ;
    USE SIGNAL ;
    ANTENNADIFFAREA 0.708600 ;
    PORT
      LAYER Metal2 ;
        RECT 498.520 53.360 498.920 53.760 ;
    END
  END Tile_X2Y0_N4BEG[2]
  PIN Tile_X2Y0_N4BEG[3]
    DIRECTION OUTPUT ;
    USE SIGNAL ;
    ANTENNADIFFAREA 0.708600 ;
    PORT
      LAYER Metal2 ;
        RECT 499.480 53.360 499.880 53.760 ;
    END
  END Tile_X2Y0_N4BEG[3]
  PIN Tile_X2Y0_N4BEG[4]
    DIRECTION OUTPUT ;
    USE SIGNAL ;
    ANTENNADIFFAREA 0.708600 ;
    PORT
      LAYER Metal2 ;
        RECT 500.440 53.360 500.840 53.760 ;
    END
  END Tile_X2Y0_N4BEG[4]
  PIN Tile_X2Y0_N4BEG[5]
    DIRECTION OUTPUT ;
    USE SIGNAL ;
    ANTENNADIFFAREA 0.708600 ;
    PORT
      LAYER Metal2 ;
        RECT 501.400 53.360 501.800 53.760 ;
    END
  END Tile_X2Y0_N4BEG[5]
  PIN Tile_X2Y0_N4BEG[6]
    DIRECTION OUTPUT ;
    USE SIGNAL ;
    ANTENNADIFFAREA 0.708600 ;
    PORT
      LAYER Metal2 ;
        RECT 502.360 53.360 502.760 53.760 ;
    END
  END Tile_X2Y0_N4BEG[6]
  PIN Tile_X2Y0_N4BEG[7]
    DIRECTION OUTPUT ;
    USE SIGNAL ;
    ANTENNADIFFAREA 0.708600 ;
    PORT
      LAYER Metal2 ;
        RECT 503.320 53.360 503.720 53.760 ;
    END
  END Tile_X2Y0_N4BEG[7]
  PIN Tile_X2Y0_N4BEG[8]
    DIRECTION OUTPUT ;
    USE SIGNAL ;
    ANTENNADIFFAREA 0.708600 ;
    PORT
      LAYER Metal2 ;
        RECT 504.280 53.360 504.680 53.760 ;
    END
  END Tile_X2Y0_N4BEG[8]
  PIN Tile_X2Y0_N4BEG[9]
    DIRECTION OUTPUT ;
    USE SIGNAL ;
    ANTENNADIFFAREA 0.708600 ;
    PORT
      LAYER Metal2 ;
        RECT 505.240 53.360 505.640 53.760 ;
    END
  END Tile_X2Y0_N4BEG[9]
  PIN Tile_X2Y0_NN4BEG[0]
    DIRECTION OUTPUT ;
    USE SIGNAL ;
    ANTENNADIFFAREA 0.708600 ;
    PORT
      LAYER Metal2 ;
        RECT 511.960 53.360 512.360 53.760 ;
    END
  END Tile_X2Y0_NN4BEG[0]
  PIN Tile_X2Y0_NN4BEG[10]
    DIRECTION OUTPUT ;
    USE SIGNAL ;
    ANTENNADIFFAREA 0.708600 ;
    PORT
      LAYER Metal2 ;
        RECT 521.560 53.360 521.960 53.760 ;
    END
  END Tile_X2Y0_NN4BEG[10]
  PIN Tile_X2Y0_NN4BEG[11]
    DIRECTION OUTPUT ;
    USE SIGNAL ;
    ANTENNADIFFAREA 0.708600 ;
    PORT
      LAYER Metal2 ;
        RECT 522.520 53.360 522.920 53.760 ;
    END
  END Tile_X2Y0_NN4BEG[11]
  PIN Tile_X2Y0_NN4BEG[12]
    DIRECTION OUTPUT ;
    USE SIGNAL ;
    ANTENNADIFFAREA 0.708600 ;
    PORT
      LAYER Metal2 ;
        RECT 523.480 53.360 523.880 53.760 ;
    END
  END Tile_X2Y0_NN4BEG[12]
  PIN Tile_X2Y0_NN4BEG[13]
    DIRECTION OUTPUT ;
    USE SIGNAL ;
    ANTENNADIFFAREA 0.708600 ;
    PORT
      LAYER Metal2 ;
        RECT 524.440 53.360 524.840 53.760 ;
    END
  END Tile_X2Y0_NN4BEG[13]
  PIN Tile_X2Y0_NN4BEG[14]
    DIRECTION OUTPUT ;
    USE SIGNAL ;
    ANTENNADIFFAREA 0.708600 ;
    PORT
      LAYER Metal2 ;
        RECT 525.400 53.360 525.800 53.760 ;
    END
  END Tile_X2Y0_NN4BEG[14]
  PIN Tile_X2Y0_NN4BEG[15]
    DIRECTION OUTPUT ;
    USE SIGNAL ;
    ANTENNADIFFAREA 0.708600 ;
    PORT
      LAYER Metal2 ;
        RECT 526.360 53.360 526.760 53.760 ;
    END
  END Tile_X2Y0_NN4BEG[15]
  PIN Tile_X2Y0_NN4BEG[1]
    DIRECTION OUTPUT ;
    USE SIGNAL ;
    ANTENNADIFFAREA 0.708600 ;
    PORT
      LAYER Metal2 ;
        RECT 512.920 53.360 513.320 53.760 ;
    END
  END Tile_X2Y0_NN4BEG[1]
  PIN Tile_X2Y0_NN4BEG[2]
    DIRECTION OUTPUT ;
    USE SIGNAL ;
    ANTENNADIFFAREA 0.708600 ;
    PORT
      LAYER Metal2 ;
        RECT 513.880 53.360 514.280 53.760 ;
    END
  END Tile_X2Y0_NN4BEG[2]
  PIN Tile_X2Y0_NN4BEG[3]
    DIRECTION OUTPUT ;
    USE SIGNAL ;
    ANTENNADIFFAREA 0.708600 ;
    PORT
      LAYER Metal2 ;
        RECT 514.840 53.360 515.240 53.760 ;
    END
  END Tile_X2Y0_NN4BEG[3]
  PIN Tile_X2Y0_NN4BEG[4]
    DIRECTION OUTPUT ;
    USE SIGNAL ;
    ANTENNADIFFAREA 0.708600 ;
    PORT
      LAYER Metal2 ;
        RECT 515.800 53.360 516.200 53.760 ;
    END
  END Tile_X2Y0_NN4BEG[4]
  PIN Tile_X2Y0_NN4BEG[5]
    DIRECTION OUTPUT ;
    USE SIGNAL ;
    ANTENNADIFFAREA 0.708600 ;
    PORT
      LAYER Metal2 ;
        RECT 516.760 53.360 517.160 53.760 ;
    END
  END Tile_X2Y0_NN4BEG[5]
  PIN Tile_X2Y0_NN4BEG[6]
    DIRECTION OUTPUT ;
    USE SIGNAL ;
    ANTENNADIFFAREA 0.708600 ;
    PORT
      LAYER Metal2 ;
        RECT 517.720 53.360 518.120 53.760 ;
    END
  END Tile_X2Y0_NN4BEG[6]
  PIN Tile_X2Y0_NN4BEG[7]
    DIRECTION OUTPUT ;
    USE SIGNAL ;
    ANTENNADIFFAREA 0.708600 ;
    PORT
      LAYER Metal2 ;
        RECT 518.680 53.360 519.080 53.760 ;
    END
  END Tile_X2Y0_NN4BEG[7]
  PIN Tile_X2Y0_NN4BEG[8]
    DIRECTION OUTPUT ;
    USE SIGNAL ;
    ANTENNADIFFAREA 0.708600 ;
    PORT
      LAYER Metal2 ;
        RECT 519.640 53.360 520.040 53.760 ;
    END
  END Tile_X2Y0_NN4BEG[8]
  PIN Tile_X2Y0_NN4BEG[9]
    DIRECTION OUTPUT ;
    USE SIGNAL ;
    ANTENNADIFFAREA 0.708600 ;
    PORT
      LAYER Metal2 ;
        RECT 520.600 53.360 521.000 53.760 ;
    END
  END Tile_X2Y0_NN4BEG[9]
  PIN Tile_X2Y0_S1END[0]
    DIRECTION INPUT ;
    USE SIGNAL ;
    ANTENNAGATEAREA 0.471900 ;
    PORT
      LAYER Metal2 ;
        RECT 528.280 53.360 528.680 53.760 ;
    END
  END Tile_X2Y0_S1END[0]
  PIN Tile_X2Y0_S1END[1]
    DIRECTION INPUT ;
    USE SIGNAL ;
    ANTENNAGATEAREA 0.471900 ;
    PORT
      LAYER Metal2 ;
        RECT 529.240 53.360 529.640 53.760 ;
    END
  END Tile_X2Y0_S1END[1]
  PIN Tile_X2Y0_S1END[2]
    DIRECTION INPUT ;
    USE SIGNAL ;
    ANTENNAGATEAREA 0.468000 ;
    PORT
      LAYER Metal2 ;
        RECT 530.200 53.360 530.600 53.760 ;
    END
  END Tile_X2Y0_S1END[2]
  PIN Tile_X2Y0_S1END[3]
    DIRECTION INPUT ;
    USE SIGNAL ;
    ANTENNAGATEAREA 0.468000 ;
    PORT
      LAYER Metal2 ;
        RECT 531.160 53.360 531.560 53.760 ;
    END
  END Tile_X2Y0_S1END[3]
  PIN Tile_X2Y0_S2END[0]
    DIRECTION INPUT ;
    USE SIGNAL ;
    ANTENNAGATEAREA 0.468000 ;
    PORT
      LAYER Metal2 ;
        RECT 539.800 53.360 540.200 53.760 ;
    END
  END Tile_X2Y0_S2END[0]
  PIN Tile_X2Y0_S2END[1]
    DIRECTION INPUT ;
    USE SIGNAL ;
    ANTENNAGATEAREA 0.468000 ;
    PORT
      LAYER Metal2 ;
        RECT 540.760 53.360 541.160 53.760 ;
    END
  END Tile_X2Y0_S2END[1]
  PIN Tile_X2Y0_S2END[2]
    DIRECTION INPUT ;
    USE SIGNAL ;
    ANTENNAGATEAREA 0.468000 ;
    PORT
      LAYER Metal2 ;
        RECT 541.720 53.360 542.120 53.760 ;
    END
  END Tile_X2Y0_S2END[2]
  PIN Tile_X2Y0_S2END[3]
    DIRECTION INPUT ;
    USE SIGNAL ;
    ANTENNAGATEAREA 0.468000 ;
    PORT
      LAYER Metal2 ;
        RECT 542.680 53.360 543.080 53.760 ;
    END
  END Tile_X2Y0_S2END[3]
  PIN Tile_X2Y0_S2END[4]
    DIRECTION INPUT ;
    USE SIGNAL ;
    ANTENNAGATEAREA 0.468000 ;
    PORT
      LAYER Metal2 ;
        RECT 543.640 53.360 544.040 53.760 ;
    END
  END Tile_X2Y0_S2END[4]
  PIN Tile_X2Y0_S2END[5]
    DIRECTION INPUT ;
    USE SIGNAL ;
    ANTENNAGATEAREA 0.468000 ;
    PORT
      LAYER Metal2 ;
        RECT 544.600 53.360 545.000 53.760 ;
    END
  END Tile_X2Y0_S2END[5]
  PIN Tile_X2Y0_S2END[6]
    DIRECTION INPUT ;
    USE SIGNAL ;
    ANTENNAGATEAREA 0.468000 ;
    PORT
      LAYER Metal2 ;
        RECT 545.560 53.360 545.960 53.760 ;
    END
  END Tile_X2Y0_S2END[6]
  PIN Tile_X2Y0_S2END[7]
    DIRECTION INPUT ;
    USE SIGNAL ;
    ANTENNAGATEAREA 0.468000 ;
    PORT
      LAYER Metal2 ;
        RECT 546.520 53.360 546.920 53.760 ;
    END
  END Tile_X2Y0_S2END[7]
  PIN Tile_X2Y0_S2MID[0]
    DIRECTION INPUT ;
    USE SIGNAL ;
    ANTENNAGATEAREA 0.471900 ;
    PORT
      LAYER Metal2 ;
        RECT 532.120 53.360 532.520 53.760 ;
    END
  END Tile_X2Y0_S2MID[0]
  PIN Tile_X2Y0_S2MID[1]
    DIRECTION INPUT ;
    USE SIGNAL ;
    ANTENNAGATEAREA 0.471900 ;
    PORT
      LAYER Metal2 ;
        RECT 533.080 53.360 533.480 53.760 ;
    END
  END Tile_X2Y0_S2MID[1]
  PIN Tile_X2Y0_S2MID[2]
    DIRECTION INPUT ;
    USE SIGNAL ;
    ANTENNAGATEAREA 0.471900 ;
    PORT
      LAYER Metal2 ;
        RECT 534.040 53.360 534.440 53.760 ;
    END
  END Tile_X2Y0_S2MID[2]
  PIN Tile_X2Y0_S2MID[3]
    DIRECTION INPUT ;
    USE SIGNAL ;
    ANTENNAGATEAREA 0.471900 ;
    PORT
      LAYER Metal2 ;
        RECT 535.000 53.360 535.400 53.760 ;
    END
  END Tile_X2Y0_S2MID[3]
  PIN Tile_X2Y0_S2MID[4]
    DIRECTION INPUT ;
    USE SIGNAL ;
    ANTENNAGATEAREA 0.471900 ;
    PORT
      LAYER Metal2 ;
        RECT 535.960 53.360 536.360 53.760 ;
    END
  END Tile_X2Y0_S2MID[4]
  PIN Tile_X2Y0_S2MID[5]
    DIRECTION INPUT ;
    USE SIGNAL ;
    ANTENNAGATEAREA 0.471900 ;
    PORT
      LAYER Metal2 ;
        RECT 536.920 53.360 537.320 53.760 ;
    END
  END Tile_X2Y0_S2MID[5]
  PIN Tile_X2Y0_S2MID[6]
    DIRECTION INPUT ;
    USE SIGNAL ;
    ANTENNAGATEAREA 0.471900 ;
    PORT
      LAYER Metal2 ;
        RECT 537.880 53.360 538.280 53.760 ;
    END
  END Tile_X2Y0_S2MID[6]
  PIN Tile_X2Y0_S2MID[7]
    DIRECTION INPUT ;
    USE SIGNAL ;
    ANTENNAGATEAREA 0.471900 ;
    PORT
      LAYER Metal2 ;
        RECT 538.840 53.360 539.240 53.760 ;
    END
  END Tile_X2Y0_S2MID[7]
  PIN Tile_X2Y0_S4END[0]
    DIRECTION INPUT ;
    USE SIGNAL ;
    ANTENNAGATEAREA 0.422500 ;
    PORT
      LAYER Metal2 ;
        RECT 547.480 53.360 547.880 53.760 ;
    END
  END Tile_X2Y0_S4END[0]
  PIN Tile_X2Y0_S4END[10]
    DIRECTION INPUT ;
    USE SIGNAL ;
    ANTENNAGATEAREA 0.468000 ;
    PORT
      LAYER Metal2 ;
        RECT 557.080 53.360 557.480 53.760 ;
    END
  END Tile_X2Y0_S4END[10]
  PIN Tile_X2Y0_S4END[11]
    DIRECTION INPUT ;
    USE SIGNAL ;
    ANTENNAGATEAREA 0.468000 ;
    PORT
      LAYER Metal2 ;
        RECT 558.040 53.360 558.440 53.760 ;
    END
  END Tile_X2Y0_S4END[11]
  PIN Tile_X2Y0_S4END[12]
    DIRECTION INPUT ;
    USE SIGNAL ;
    ANTENNAGATEAREA 0.468000 ;
    PORT
      LAYER Metal2 ;
        RECT 559.000 53.360 559.400 53.760 ;
    END
  END Tile_X2Y0_S4END[12]
  PIN Tile_X2Y0_S4END[13]
    DIRECTION INPUT ;
    USE SIGNAL ;
    ANTENNAGATEAREA 0.468000 ;
    PORT
      LAYER Metal2 ;
        RECT 559.960 53.360 560.360 53.760 ;
    END
  END Tile_X2Y0_S4END[13]
  PIN Tile_X2Y0_S4END[14]
    DIRECTION INPUT ;
    USE SIGNAL ;
    ANTENNAGATEAREA 0.468000 ;
    PORT
      LAYER Metal2 ;
        RECT 560.920 53.360 561.320 53.760 ;
    END
  END Tile_X2Y0_S4END[14]
  PIN Tile_X2Y0_S4END[15]
    DIRECTION INPUT ;
    USE SIGNAL ;
    ANTENNAGATEAREA 0.468000 ;
    PORT
      LAYER Metal2 ;
        RECT 561.880 53.360 562.280 53.760 ;
    END
  END Tile_X2Y0_S4END[15]
  PIN Tile_X2Y0_S4END[1]
    DIRECTION INPUT ;
    USE SIGNAL ;
    ANTENNAGATEAREA 0.422500 ;
    PORT
      LAYER Metal2 ;
        RECT 548.440 53.360 548.840 53.760 ;
    END
  END Tile_X2Y0_S4END[1]
  PIN Tile_X2Y0_S4END[2]
    DIRECTION INPUT ;
    USE SIGNAL ;
    ANTENNAGATEAREA 0.422500 ;
    PORT
      LAYER Metal2 ;
        RECT 549.400 53.360 549.800 53.760 ;
    END
  END Tile_X2Y0_S4END[2]
  PIN Tile_X2Y0_S4END[3]
    DIRECTION INPUT ;
    USE SIGNAL ;
    ANTENNAGATEAREA 0.422500 ;
    PORT
      LAYER Metal2 ;
        RECT 550.360 53.360 550.760 53.760 ;
    END
  END Tile_X2Y0_S4END[3]
  PIN Tile_X2Y0_S4END[4]
    DIRECTION INPUT ;
    USE SIGNAL ;
    ANTENNAGATEAREA 0.422500 ;
    PORT
      LAYER Metal2 ;
        RECT 551.320 53.360 551.720 53.760 ;
    END
  END Tile_X2Y0_S4END[4]
  PIN Tile_X2Y0_S4END[5]
    DIRECTION INPUT ;
    USE SIGNAL ;
    ANTENNAGATEAREA 0.422500 ;
    PORT
      LAYER Metal2 ;
        RECT 552.280 53.360 552.680 53.760 ;
    END
  END Tile_X2Y0_S4END[5]
  PIN Tile_X2Y0_S4END[6]
    DIRECTION INPUT ;
    USE SIGNAL ;
    ANTENNAGATEAREA 0.709800 ;
    PORT
      LAYER Metal2 ;
        RECT 553.240 53.360 553.640 53.760 ;
    END
  END Tile_X2Y0_S4END[6]
  PIN Tile_X2Y0_S4END[7]
    DIRECTION INPUT ;
    USE SIGNAL ;
    ANTENNAGATEAREA 0.709800 ;
    PORT
      LAYER Metal2 ;
        RECT 554.200 53.360 554.600 53.760 ;
    END
  END Tile_X2Y0_S4END[7]
  PIN Tile_X2Y0_S4END[8]
    DIRECTION INPUT ;
    USE SIGNAL ;
    ANTENNAGATEAREA 0.709800 ;
    PORT
      LAYER Metal2 ;
        RECT 555.160 53.360 555.560 53.760 ;
    END
  END Tile_X2Y0_S4END[8]
  PIN Tile_X2Y0_S4END[9]
    DIRECTION INPUT ;
    USE SIGNAL ;
    ANTENNAGATEAREA 0.709800 ;
    PORT
      LAYER Metal2 ;
        RECT 556.120 53.360 556.520 53.760 ;
    END
  END Tile_X2Y0_S4END[9]
  PIN Tile_X2Y0_SS4END[0]
    DIRECTION INPUT ;
    USE SIGNAL ;
    ANTENNAGATEAREA 0.422500 ;
    PORT
      LAYER Metal2 ;
        RECT 562.840 53.360 563.240 53.760 ;
    END
  END Tile_X2Y0_SS4END[0]
  PIN Tile_X2Y0_SS4END[10]
    DIRECTION INPUT ;
    USE SIGNAL ;
    ANTENNAGATEAREA 0.468000 ;
    PORT
      LAYER Metal2 ;
        RECT 572.440 53.360 572.840 53.760 ;
    END
  END Tile_X2Y0_SS4END[10]
  PIN Tile_X2Y0_SS4END[11]
    DIRECTION INPUT ;
    USE SIGNAL ;
    ANTENNAGATEAREA 0.468000 ;
    PORT
      LAYER Metal2 ;
        RECT 573.400 53.360 573.800 53.760 ;
    END
  END Tile_X2Y0_SS4END[11]
  PIN Tile_X2Y0_SS4END[12]
    DIRECTION INPUT ;
    USE SIGNAL ;
    ANTENNAGATEAREA 0.468000 ;
    PORT
      LAYER Metal2 ;
        RECT 574.360 53.360 574.760 53.760 ;
    END
  END Tile_X2Y0_SS4END[12]
  PIN Tile_X2Y0_SS4END[13]
    DIRECTION INPUT ;
    USE SIGNAL ;
    ANTENNAGATEAREA 0.468000 ;
    PORT
      LAYER Metal2 ;
        RECT 575.320 53.360 575.720 53.760 ;
    END
  END Tile_X2Y0_SS4END[13]
  PIN Tile_X2Y0_SS4END[14]
    DIRECTION INPUT ;
    USE SIGNAL ;
    ANTENNAGATEAREA 0.468000 ;
    PORT
      LAYER Metal2 ;
        RECT 576.280 53.360 576.680 53.760 ;
    END
  END Tile_X2Y0_SS4END[14]
  PIN Tile_X2Y0_SS4END[15]
    DIRECTION INPUT ;
    USE SIGNAL ;
    ANTENNAGATEAREA 0.468000 ;
    PORT
      LAYER Metal2 ;
        RECT 577.240 53.360 577.640 53.760 ;
    END
  END Tile_X2Y0_SS4END[15]
  PIN Tile_X2Y0_SS4END[1]
    DIRECTION INPUT ;
    USE SIGNAL ;
    ANTENNAGATEAREA 0.422500 ;
    PORT
      LAYER Metal2 ;
        RECT 563.800 53.360 564.200 53.760 ;
    END
  END Tile_X2Y0_SS4END[1]
  PIN Tile_X2Y0_SS4END[2]
    DIRECTION INPUT ;
    USE SIGNAL ;
    ANTENNAGATEAREA 0.422500 ;
    PORT
      LAYER Metal2 ;
        RECT 564.760 53.360 565.160 53.760 ;
    END
  END Tile_X2Y0_SS4END[2]
  PIN Tile_X2Y0_SS4END[3]
    DIRECTION INPUT ;
    USE SIGNAL ;
    ANTENNAGATEAREA 0.422500 ;
    PORT
      LAYER Metal2 ;
        RECT 565.720 53.360 566.120 53.760 ;
    END
  END Tile_X2Y0_SS4END[3]
  PIN Tile_X2Y0_SS4END[4]
    DIRECTION INPUT ;
    USE SIGNAL ;
    ANTENNAGATEAREA 0.422500 ;
    PORT
      LAYER Metal2 ;
        RECT 566.680 53.360 567.080 53.760 ;
    END
  END Tile_X2Y0_SS4END[4]
  PIN Tile_X2Y0_SS4END[5]
    DIRECTION INPUT ;
    USE SIGNAL ;
    ANTENNAGATEAREA 0.422500 ;
    PORT
      LAYER Metal2 ;
        RECT 567.640 53.360 568.040 53.760 ;
    END
  END Tile_X2Y0_SS4END[5]
  PIN Tile_X2Y0_SS4END[6]
    DIRECTION INPUT ;
    USE SIGNAL ;
    ANTENNAGATEAREA 0.483600 ;
    PORT
      LAYER Metal2 ;
        RECT 568.600 53.360 569.000 53.760 ;
    END
  END Tile_X2Y0_SS4END[6]
  PIN Tile_X2Y0_SS4END[7]
    DIRECTION INPUT ;
    USE SIGNAL ;
    ANTENNAGATEAREA 0.483600 ;
    PORT
      LAYER Metal2 ;
        RECT 569.560 53.360 569.960 53.760 ;
    END
  END Tile_X2Y0_SS4END[7]
  PIN Tile_X2Y0_SS4END[8]
    DIRECTION INPUT ;
    USE SIGNAL ;
    ANTENNAGATEAREA 0.483600 ;
    PORT
      LAYER Metal2 ;
        RECT 570.520 53.360 570.920 53.760 ;
    END
  END Tile_X2Y0_SS4END[8]
  PIN Tile_X2Y0_SS4END[9]
    DIRECTION INPUT ;
    USE SIGNAL ;
    ANTENNAGATEAREA 0.483600 ;
    PORT
      LAYER Metal2 ;
        RECT 571.480 53.360 571.880 53.760 ;
    END
  END Tile_X2Y0_SS4END[9]
  PIN Tile_X2Y0_UserCLK
    DIRECTION INPUT ;
    USE SIGNAL ;
    ANTENNAGATEAREA 0.180700 ;
    PORT
      LAYER Metal2 ;
        RECT 325.720 0.000 326.120 0.400 ;
    END
  END Tile_X2Y0_UserCLK
  PIN Tile_X2Y0_UserCLKo
    DIRECTION OUTPUT ;
    USE SIGNAL ;
    ANTENNADIFFAREA 0.708600 ;
    PORT
      LAYER Metal2 ;
        RECT 578.200 53.360 578.600 53.760 ;
    END
  END Tile_X2Y0_UserCLKo
  PIN VGND
    DIRECTION INOUT ;
    USE GROUND ;
    PORT
      LAYER TopMetal1 ;
        RECT 21.580 0.000 23.780 53.760 ;
    END
    PORT
      LAYER TopMetal1 ;
        RECT 97.180 0.000 99.380 53.760 ;
    END
    PORT
      LAYER TopMetal1 ;
        RECT 172.780 0.000 174.980 53.760 ;
    END
    PORT
      LAYER TopMetal1 ;
        RECT 236.620 0.000 238.820 53.760 ;
    END
    PORT
      LAYER TopMetal1 ;
        RECT 312.220 0.000 314.420 53.760 ;
    END
    PORT
      LAYER TopMetal1 ;
        RECT 387.820 0.000 390.020 53.760 ;
    END
    PORT
      LAYER TopMetal1 ;
        RECT 451.660 0.000 453.860 53.760 ;
    END
    PORT
      LAYER TopMetal1 ;
        RECT 527.260 0.000 529.460 53.760 ;
    END
    PORT
      LAYER TopMetal1 ;
        RECT 602.860 0.000 605.060 53.760 ;
    END
  END VGND
  PIN VPWR
    DIRECTION INOUT ;
    USE POWER ;
    PORT
      LAYER TopMetal1 ;
        RECT 15.380 0.000 17.580 53.760 ;
    END
    PORT
      LAYER TopMetal1 ;
        RECT 90.980 0.000 93.180 53.760 ;
    END
    PORT
      LAYER TopMetal1 ;
        RECT 166.580 0.000 168.780 53.760 ;
    END
    PORT
      LAYER TopMetal1 ;
        RECT 230.420 0.000 232.620 53.760 ;
    END
    PORT
      LAYER TopMetal1 ;
        RECT 306.020 0.000 308.220 53.760 ;
    END
    PORT
      LAYER TopMetal1 ;
        RECT 381.620 0.000 383.820 53.760 ;
    END
    PORT
      LAYER TopMetal1 ;
        RECT 445.460 0.000 447.660 53.760 ;
    END
    PORT
      LAYER TopMetal1 ;
        RECT 521.060 0.000 523.260 53.760 ;
    END
    PORT
      LAYER TopMetal1 ;
        RECT 596.660 0.000 598.860 53.760 ;
    END
  END VPWR
  PIN WDATA_top0
    DIRECTION INPUT ;
    USE SIGNAL ;
    ANTENNAGATEAREA 0.452400 ;
    PORT
      LAYER Metal2 ;
        RECT 547.480 0.000 547.880 0.400 ;
    END
  END WDATA_top0
  PIN WDATA_top1
    DIRECTION INPUT ;
    USE SIGNAL ;
    ANTENNAGATEAREA 0.452400 ;
    PORT
      LAYER Metal2 ;
        RECT 548.440 0.000 548.840 0.400 ;
    END
  END WDATA_top1
  PIN WDATA_top10
    DIRECTION INPUT ;
    USE SIGNAL ;
    ANTENNAGATEAREA 0.452400 ;
    PORT
      LAYER Metal2 ;
        RECT 557.080 0.000 557.480 0.400 ;
    END
  END WDATA_top10
  PIN WDATA_top11
    DIRECTION INPUT ;
    USE SIGNAL ;
    ANTENNAGATEAREA 0.452400 ;
    PORT
      LAYER Metal2 ;
        RECT 558.040 0.000 558.440 0.400 ;
    END
  END WDATA_top11
  PIN WDATA_top12
    DIRECTION INPUT ;
    USE SIGNAL ;
    ANTENNAGATEAREA 0.452400 ;
    PORT
      LAYER Metal2 ;
        RECT 559.000 0.000 559.400 0.400 ;
    END
  END WDATA_top12
  PIN WDATA_top13
    DIRECTION INPUT ;
    USE SIGNAL ;
    ANTENNAGATEAREA 0.452400 ;
    PORT
      LAYER Metal2 ;
        RECT 559.960 0.000 560.360 0.400 ;
    END
  END WDATA_top13
  PIN WDATA_top14
    DIRECTION INPUT ;
    USE SIGNAL ;
    ANTENNAGATEAREA 0.452400 ;
    PORT
      LAYER Metal2 ;
        RECT 560.920 0.000 561.320 0.400 ;
    END
  END WDATA_top14
  PIN WDATA_top15
    DIRECTION INPUT ;
    USE SIGNAL ;
    ANTENNAGATEAREA 0.452400 ;
    PORT
      LAYER Metal2 ;
        RECT 561.880 0.000 562.280 0.400 ;
    END
  END WDATA_top15
  PIN WDATA_top16
    DIRECTION INPUT ;
    USE SIGNAL ;
    ANTENNAGATEAREA 0.452400 ;
    PORT
      LAYER Metal2 ;
        RECT 562.840 0.000 563.240 0.400 ;
    END
  END WDATA_top16
  PIN WDATA_top17
    DIRECTION INPUT ;
    USE SIGNAL ;
    ANTENNAGATEAREA 0.452400 ;
    PORT
      LAYER Metal2 ;
        RECT 563.800 0.000 564.200 0.400 ;
    END
  END WDATA_top17
  PIN WDATA_top18
    DIRECTION INPUT ;
    USE SIGNAL ;
    ANTENNAGATEAREA 0.452400 ;
    PORT
      LAYER Metal2 ;
        RECT 564.760 0.000 565.160 0.400 ;
    END
  END WDATA_top18
  PIN WDATA_top19
    DIRECTION INPUT ;
    USE SIGNAL ;
    ANTENNAGATEAREA 0.452400 ;
    PORT
      LAYER Metal2 ;
        RECT 565.720 0.000 566.120 0.400 ;
    END
  END WDATA_top19
  PIN WDATA_top2
    DIRECTION INPUT ;
    USE SIGNAL ;
    ANTENNAGATEAREA 1.669200 ;
    ANTENNADIFFAREA 4.030800 ;
    PORT
      LAYER Metal2 ;
        RECT 549.400 0.000 549.800 0.400 ;
    END
  END WDATA_top2
  PIN WDATA_top20
    DIRECTION INPUT ;
    USE SIGNAL ;
    ANTENNAGATEAREA 0.452400 ;
    PORT
      LAYER Metal2 ;
        RECT 566.680 0.000 567.080 0.400 ;
    END
  END WDATA_top20
  PIN WDATA_top21
    DIRECTION INPUT ;
    USE SIGNAL ;
    ANTENNAGATEAREA 0.452400 ;
    PORT
      LAYER Metal2 ;
        RECT 567.640 0.000 568.040 0.400 ;
    END
  END WDATA_top21
  PIN WDATA_top22
    DIRECTION INPUT ;
    USE SIGNAL ;
    ANTENNAGATEAREA 0.452400 ;
    PORT
      LAYER Metal2 ;
        RECT 568.600 0.000 569.000 0.400 ;
    END
  END WDATA_top22
  PIN WDATA_top23
    DIRECTION INPUT ;
    USE SIGNAL ;
    ANTENNAGATEAREA 0.452400 ;
    PORT
      LAYER Metal2 ;
        RECT 569.560 0.000 569.960 0.400 ;
    END
  END WDATA_top23
  PIN WDATA_top24
    DIRECTION INPUT ;
    USE SIGNAL ;
    ANTENNAGATEAREA 0.452400 ;
    PORT
      LAYER Metal2 ;
        RECT 570.520 0.000 570.920 0.400 ;
    END
  END WDATA_top24
  PIN WDATA_top25
    DIRECTION INPUT ;
    USE SIGNAL ;
    ANTENNAGATEAREA 0.452400 ;
    PORT
      LAYER Metal2 ;
        RECT 571.480 0.000 571.880 0.400 ;
    END
  END WDATA_top25
  PIN WDATA_top26
    DIRECTION INPUT ;
    USE SIGNAL ;
    ANTENNAGATEAREA 0.452400 ;
    PORT
      LAYER Metal2 ;
        RECT 572.440 0.000 572.840 0.400 ;
    END
  END WDATA_top26
  PIN WDATA_top27
    DIRECTION INPUT ;
    USE SIGNAL ;
    ANTENNAGATEAREA 0.452400 ;
    PORT
      LAYER Metal2 ;
        RECT 573.400 0.000 573.800 0.400 ;
    END
  END WDATA_top27
  PIN WDATA_top28
    DIRECTION INPUT ;
    USE SIGNAL ;
    ANTENNAGATEAREA 0.452400 ;
    PORT
      LAYER Metal2 ;
        RECT 574.360 0.000 574.760 0.400 ;
    END
  END WDATA_top28
  PIN WDATA_top29
    DIRECTION INPUT ;
    USE SIGNAL ;
    ANTENNAGATEAREA 0.452400 ;
    PORT
      LAYER Metal2 ;
        RECT 575.320 0.000 575.720 0.400 ;
    END
  END WDATA_top29
  PIN WDATA_top3
    DIRECTION INPUT ;
    USE SIGNAL ;
    ANTENNAGATEAREA 0.452400 ;
    PORT
      LAYER Metal2 ;
        RECT 550.360 0.000 550.760 0.400 ;
    END
  END WDATA_top3
  PIN WDATA_top30
    DIRECTION INPUT ;
    USE SIGNAL ;
    ANTENNAGATEAREA 0.452400 ;
    PORT
      LAYER Metal2 ;
        RECT 576.280 0.000 576.680 0.400 ;
    END
  END WDATA_top30
  PIN WDATA_top31
    DIRECTION INPUT ;
    USE SIGNAL ;
    ANTENNAGATEAREA 0.452400 ;
    PORT
      LAYER Metal2 ;
        RECT 577.240 0.000 577.640 0.400 ;
    END
  END WDATA_top31
  PIN WDATA_top4
    DIRECTION INPUT ;
    USE SIGNAL ;
    ANTENNAGATEAREA 2.886000 ;
    ANTENNADIFFAREA 8.061600 ;
    PORT
      LAYER Metal2 ;
        RECT 551.320 0.000 551.720 0.400 ;
    END
  END WDATA_top4
  PIN WDATA_top5
    DIRECTION INPUT ;
    USE SIGNAL ;
    ANTENNAGATEAREA 1.669200 ;
    ANTENNADIFFAREA 4.030800 ;
    PORT
      LAYER Metal2 ;
        RECT 552.280 0.000 552.680 0.400 ;
    END
  END WDATA_top5
  PIN WDATA_top6
    DIRECTION INPUT ;
    USE SIGNAL ;
    ANTENNAGATEAREA 1.669200 ;
    ANTENNADIFFAREA 4.030800 ;
    PORT
      LAYER Metal2 ;
        RECT 553.240 0.000 553.640 0.400 ;
    END
  END WDATA_top6
  PIN WDATA_top7
    DIRECTION INPUT ;
    USE SIGNAL ;
    ANTENNAGATEAREA 0.452400 ;
    PORT
      LAYER Metal2 ;
        RECT 554.200 0.000 554.600 0.400 ;
    END
  END WDATA_top7
  PIN WDATA_top8
    DIRECTION INPUT ;
    USE SIGNAL ;
    ANTENNAGATEAREA 0.452400 ;
    PORT
      LAYER Metal2 ;
        RECT 555.160 0.000 555.560 0.400 ;
    END
  END WDATA_top8
  PIN WDATA_top9
    DIRECTION INPUT ;
    USE SIGNAL ;
    ANTENNAGATEAREA 1.669200 ;
    ANTENNADIFFAREA 4.030800 ;
    PORT
      LAYER Metal2 ;
        RECT 556.120 0.000 556.520 0.400 ;
    END
  END WDATA_top9
  PIN WE_top
    DIRECTION INPUT ;
    USE SIGNAL ;
    ANTENNAGATEAREA 0.852800 ;
    PORT
      LAYER Metal2 ;
        RECT 519.640 0.000 520.040 0.400 ;
    END
  END WE_top
  OBS
      LAYER GatPoly ;
        RECT 2.880 3.630 642.240 49.290 ;
      LAYER Metal1 ;
        RECT 2.880 3.560 642.240 49.360 ;
      LAYER Metal2 ;
        RECT 3.255 53.150 47.110 53.660 ;
        RECT 47.930 53.150 48.070 53.660 ;
        RECT 48.890 53.150 49.030 53.660 ;
        RECT 49.850 53.150 49.990 53.660 ;
        RECT 50.810 53.150 50.950 53.660 ;
        RECT 51.770 53.150 51.910 53.660 ;
        RECT 52.730 53.150 52.870 53.660 ;
        RECT 53.690 53.150 53.830 53.660 ;
        RECT 54.650 53.150 54.790 53.660 ;
        RECT 55.610 53.150 55.750 53.660 ;
        RECT 56.570 53.150 56.710 53.660 ;
        RECT 57.530 53.150 57.670 53.660 ;
        RECT 58.490 53.150 58.630 53.660 ;
        RECT 59.450 53.150 59.590 53.660 ;
        RECT 60.410 53.150 60.550 53.660 ;
        RECT 61.370 53.150 61.510 53.660 ;
        RECT 62.330 53.150 62.470 53.660 ;
        RECT 63.290 53.150 63.430 53.660 ;
        RECT 64.250 53.150 64.390 53.660 ;
        RECT 65.210 53.150 65.350 53.660 ;
        RECT 66.170 53.150 66.310 53.660 ;
        RECT 67.130 53.150 67.270 53.660 ;
        RECT 68.090 53.150 68.230 53.660 ;
        RECT 69.050 53.150 69.190 53.660 ;
        RECT 70.010 53.150 70.150 53.660 ;
        RECT 70.970 53.150 71.110 53.660 ;
        RECT 71.930 53.150 72.070 53.660 ;
        RECT 72.890 53.150 73.030 53.660 ;
        RECT 73.850 53.150 73.990 53.660 ;
        RECT 74.810 53.150 74.950 53.660 ;
        RECT 75.770 53.150 75.910 53.660 ;
        RECT 76.730 53.150 76.870 53.660 ;
        RECT 77.690 53.150 77.830 53.660 ;
        RECT 78.650 53.150 78.790 53.660 ;
        RECT 79.610 53.150 79.750 53.660 ;
        RECT 80.570 53.150 80.710 53.660 ;
        RECT 81.530 53.150 81.670 53.660 ;
        RECT 82.490 53.150 82.630 53.660 ;
        RECT 83.450 53.150 83.590 53.660 ;
        RECT 84.410 53.150 84.550 53.660 ;
        RECT 85.370 53.150 85.510 53.660 ;
        RECT 86.330 53.150 86.470 53.660 ;
        RECT 87.290 53.150 87.430 53.660 ;
        RECT 88.250 53.150 88.390 53.660 ;
        RECT 89.210 53.150 89.350 53.660 ;
        RECT 90.170 53.150 90.310 53.660 ;
        RECT 91.130 53.150 91.270 53.660 ;
        RECT 92.090 53.150 92.230 53.660 ;
        RECT 93.050 53.150 93.190 53.660 ;
        RECT 94.010 53.150 94.150 53.660 ;
        RECT 94.970 53.150 95.110 53.660 ;
        RECT 95.930 53.150 96.070 53.660 ;
        RECT 96.890 53.150 97.030 53.660 ;
        RECT 97.850 53.150 97.990 53.660 ;
        RECT 98.810 53.150 98.950 53.660 ;
        RECT 99.770 53.150 99.910 53.660 ;
        RECT 100.730 53.150 100.870 53.660 ;
        RECT 101.690 53.150 101.830 53.660 ;
        RECT 102.650 53.150 102.790 53.660 ;
        RECT 103.610 53.150 103.750 53.660 ;
        RECT 104.570 53.150 104.710 53.660 ;
        RECT 105.530 53.150 105.670 53.660 ;
        RECT 106.490 53.150 106.630 53.660 ;
        RECT 107.450 53.150 107.590 53.660 ;
        RECT 108.410 53.150 108.550 53.660 ;
        RECT 109.370 53.150 109.510 53.660 ;
        RECT 110.330 53.150 110.470 53.660 ;
        RECT 111.290 53.150 111.430 53.660 ;
        RECT 112.250 53.150 112.390 53.660 ;
        RECT 113.210 53.150 113.350 53.660 ;
        RECT 114.170 53.150 114.310 53.660 ;
        RECT 115.130 53.150 115.270 53.660 ;
        RECT 116.090 53.150 116.230 53.660 ;
        RECT 117.050 53.150 117.190 53.660 ;
        RECT 118.010 53.150 118.150 53.660 ;
        RECT 118.970 53.150 119.110 53.660 ;
        RECT 119.930 53.150 120.070 53.660 ;
        RECT 120.890 53.150 121.030 53.660 ;
        RECT 121.850 53.150 121.990 53.660 ;
        RECT 122.810 53.150 122.950 53.660 ;
        RECT 123.770 53.150 123.910 53.660 ;
        RECT 124.730 53.150 124.870 53.660 ;
        RECT 125.690 53.150 125.830 53.660 ;
        RECT 126.650 53.150 126.790 53.660 ;
        RECT 127.610 53.150 127.750 53.660 ;
        RECT 128.570 53.150 128.710 53.660 ;
        RECT 129.530 53.150 129.670 53.660 ;
        RECT 130.490 53.150 130.630 53.660 ;
        RECT 131.450 53.150 131.590 53.660 ;
        RECT 132.410 53.150 132.550 53.660 ;
        RECT 133.370 53.150 133.510 53.660 ;
        RECT 134.330 53.150 134.470 53.660 ;
        RECT 135.290 53.150 135.430 53.660 ;
        RECT 136.250 53.150 136.390 53.660 ;
        RECT 137.210 53.150 137.350 53.660 ;
        RECT 138.170 53.150 138.310 53.660 ;
        RECT 139.130 53.150 139.270 53.660 ;
        RECT 140.090 53.150 140.230 53.660 ;
        RECT 141.050 53.150 141.190 53.660 ;
        RECT 142.010 53.150 142.150 53.660 ;
        RECT 142.970 53.150 143.110 53.660 ;
        RECT 143.930 53.150 144.070 53.660 ;
        RECT 144.890 53.150 145.030 53.660 ;
        RECT 145.850 53.150 145.990 53.660 ;
        RECT 146.810 53.150 146.950 53.660 ;
        RECT 147.770 53.150 147.910 53.660 ;
        RECT 148.730 53.150 148.870 53.660 ;
        RECT 149.690 53.150 149.830 53.660 ;
        RECT 150.650 53.150 150.790 53.660 ;
        RECT 151.610 53.150 151.750 53.660 ;
        RECT 152.570 53.150 152.710 53.660 ;
        RECT 153.530 53.150 153.670 53.660 ;
        RECT 154.490 53.150 154.630 53.660 ;
        RECT 155.450 53.150 155.590 53.660 ;
        RECT 156.410 53.150 156.550 53.660 ;
        RECT 157.370 53.150 157.510 53.660 ;
        RECT 158.330 53.150 158.470 53.660 ;
        RECT 159.290 53.150 159.430 53.660 ;
        RECT 160.250 53.150 160.390 53.660 ;
        RECT 161.210 53.150 161.350 53.660 ;
        RECT 162.170 53.150 162.310 53.660 ;
        RECT 163.130 53.150 163.270 53.660 ;
        RECT 164.090 53.150 164.230 53.660 ;
        RECT 165.050 53.150 165.190 53.660 ;
        RECT 166.010 53.150 166.150 53.660 ;
        RECT 166.970 53.150 167.110 53.660 ;
        RECT 167.930 53.150 262.150 53.660 ;
        RECT 262.970 53.150 263.110 53.660 ;
        RECT 263.930 53.150 264.070 53.660 ;
        RECT 264.890 53.150 265.030 53.660 ;
        RECT 265.850 53.150 265.990 53.660 ;
        RECT 266.810 53.150 266.950 53.660 ;
        RECT 267.770 53.150 267.910 53.660 ;
        RECT 268.730 53.150 268.870 53.660 ;
        RECT 269.690 53.150 269.830 53.660 ;
        RECT 270.650 53.150 270.790 53.660 ;
        RECT 271.610 53.150 271.750 53.660 ;
        RECT 272.570 53.150 272.710 53.660 ;
        RECT 273.530 53.150 273.670 53.660 ;
        RECT 274.490 53.150 274.630 53.660 ;
        RECT 275.450 53.150 275.590 53.660 ;
        RECT 276.410 53.150 276.550 53.660 ;
        RECT 277.370 53.150 277.510 53.660 ;
        RECT 278.330 53.150 278.470 53.660 ;
        RECT 279.290 53.150 279.430 53.660 ;
        RECT 280.250 53.150 280.390 53.660 ;
        RECT 281.210 53.150 281.350 53.660 ;
        RECT 282.170 53.150 282.310 53.660 ;
        RECT 283.130 53.150 283.270 53.660 ;
        RECT 284.090 53.150 284.230 53.660 ;
        RECT 285.050 53.150 285.190 53.660 ;
        RECT 286.010 53.150 286.150 53.660 ;
        RECT 286.970 53.150 287.110 53.660 ;
        RECT 287.930 53.150 288.070 53.660 ;
        RECT 288.890 53.150 289.030 53.660 ;
        RECT 289.850 53.150 289.990 53.660 ;
        RECT 290.810 53.150 290.950 53.660 ;
        RECT 291.770 53.150 291.910 53.660 ;
        RECT 292.730 53.150 292.870 53.660 ;
        RECT 293.690 53.150 293.830 53.660 ;
        RECT 294.650 53.150 294.790 53.660 ;
        RECT 295.610 53.150 295.750 53.660 ;
        RECT 296.570 53.150 296.710 53.660 ;
        RECT 297.530 53.150 297.670 53.660 ;
        RECT 298.490 53.150 298.630 53.660 ;
        RECT 299.450 53.150 299.590 53.660 ;
        RECT 300.410 53.150 300.550 53.660 ;
        RECT 301.370 53.150 301.510 53.660 ;
        RECT 302.330 53.150 302.470 53.660 ;
        RECT 303.290 53.150 303.430 53.660 ;
        RECT 304.250 53.150 304.390 53.660 ;
        RECT 305.210 53.150 305.350 53.660 ;
        RECT 306.170 53.150 306.310 53.660 ;
        RECT 307.130 53.150 307.270 53.660 ;
        RECT 308.090 53.150 308.230 53.660 ;
        RECT 309.050 53.150 309.190 53.660 ;
        RECT 310.010 53.150 310.150 53.660 ;
        RECT 310.970 53.150 311.110 53.660 ;
        RECT 311.930 53.150 312.070 53.660 ;
        RECT 312.890 53.150 313.030 53.660 ;
        RECT 313.850 53.150 313.990 53.660 ;
        RECT 314.810 53.150 314.950 53.660 ;
        RECT 315.770 53.150 315.910 53.660 ;
        RECT 316.730 53.150 316.870 53.660 ;
        RECT 317.690 53.150 317.830 53.660 ;
        RECT 318.650 53.150 318.790 53.660 ;
        RECT 319.610 53.150 319.750 53.660 ;
        RECT 320.570 53.150 320.710 53.660 ;
        RECT 321.530 53.150 321.670 53.660 ;
        RECT 322.490 53.150 322.630 53.660 ;
        RECT 323.450 53.150 323.590 53.660 ;
        RECT 324.410 53.150 324.550 53.660 ;
        RECT 325.370 53.150 325.510 53.660 ;
        RECT 326.330 53.150 326.470 53.660 ;
        RECT 327.290 53.150 327.430 53.660 ;
        RECT 328.250 53.150 328.390 53.660 ;
        RECT 329.210 53.150 329.350 53.660 ;
        RECT 330.170 53.150 330.310 53.660 ;
        RECT 331.130 53.150 331.270 53.660 ;
        RECT 332.090 53.150 332.230 53.660 ;
        RECT 333.050 53.150 333.190 53.660 ;
        RECT 334.010 53.150 334.150 53.660 ;
        RECT 334.970 53.150 335.110 53.660 ;
        RECT 335.930 53.150 336.070 53.660 ;
        RECT 336.890 53.150 337.030 53.660 ;
        RECT 337.850 53.150 337.990 53.660 ;
        RECT 338.810 53.150 338.950 53.660 ;
        RECT 339.770 53.150 339.910 53.660 ;
        RECT 340.730 53.150 340.870 53.660 ;
        RECT 341.690 53.150 341.830 53.660 ;
        RECT 342.650 53.150 342.790 53.660 ;
        RECT 343.610 53.150 343.750 53.660 ;
        RECT 344.570 53.150 344.710 53.660 ;
        RECT 345.530 53.150 345.670 53.660 ;
        RECT 346.490 53.150 346.630 53.660 ;
        RECT 347.450 53.150 347.590 53.660 ;
        RECT 348.410 53.150 348.550 53.660 ;
        RECT 349.370 53.150 349.510 53.660 ;
        RECT 350.330 53.150 350.470 53.660 ;
        RECT 351.290 53.150 351.430 53.660 ;
        RECT 352.250 53.150 352.390 53.660 ;
        RECT 353.210 53.150 353.350 53.660 ;
        RECT 354.170 53.150 354.310 53.660 ;
        RECT 355.130 53.150 355.270 53.660 ;
        RECT 356.090 53.150 356.230 53.660 ;
        RECT 357.050 53.150 357.190 53.660 ;
        RECT 358.010 53.150 358.150 53.660 ;
        RECT 358.970 53.150 359.110 53.660 ;
        RECT 359.930 53.150 360.070 53.660 ;
        RECT 360.890 53.150 361.030 53.660 ;
        RECT 361.850 53.150 361.990 53.660 ;
        RECT 362.810 53.150 362.950 53.660 ;
        RECT 363.770 53.150 363.910 53.660 ;
        RECT 364.730 53.150 364.870 53.660 ;
        RECT 365.690 53.150 365.830 53.660 ;
        RECT 366.650 53.150 366.790 53.660 ;
        RECT 367.610 53.150 367.750 53.660 ;
        RECT 368.570 53.150 368.710 53.660 ;
        RECT 369.530 53.150 369.670 53.660 ;
        RECT 370.490 53.150 370.630 53.660 ;
        RECT 371.450 53.150 371.590 53.660 ;
        RECT 372.410 53.150 372.550 53.660 ;
        RECT 373.370 53.150 373.510 53.660 ;
        RECT 374.330 53.150 374.470 53.660 ;
        RECT 375.290 53.150 375.430 53.660 ;
        RECT 376.250 53.150 376.390 53.660 ;
        RECT 377.210 53.150 377.350 53.660 ;
        RECT 378.170 53.150 378.310 53.660 ;
        RECT 379.130 53.150 379.270 53.660 ;
        RECT 380.090 53.150 380.230 53.660 ;
        RECT 381.050 53.150 381.190 53.660 ;
        RECT 382.010 53.150 382.150 53.660 ;
        RECT 382.970 53.150 477.190 53.660 ;
        RECT 478.010 53.150 478.150 53.660 ;
        RECT 478.970 53.150 479.110 53.660 ;
        RECT 479.930 53.150 480.070 53.660 ;
        RECT 480.890 53.150 481.030 53.660 ;
        RECT 481.850 53.150 481.990 53.660 ;
        RECT 482.810 53.150 482.950 53.660 ;
        RECT 483.770 53.150 483.910 53.660 ;
        RECT 484.730 53.150 484.870 53.660 ;
        RECT 485.690 53.150 485.830 53.660 ;
        RECT 486.650 53.150 486.790 53.660 ;
        RECT 487.610 53.150 487.750 53.660 ;
        RECT 488.570 53.150 488.710 53.660 ;
        RECT 489.530 53.150 489.670 53.660 ;
        RECT 490.490 53.150 490.630 53.660 ;
        RECT 491.450 53.150 491.590 53.660 ;
        RECT 492.410 53.150 492.550 53.660 ;
        RECT 493.370 53.150 493.510 53.660 ;
        RECT 494.330 53.150 494.470 53.660 ;
        RECT 495.290 53.150 495.430 53.660 ;
        RECT 496.250 53.150 496.390 53.660 ;
        RECT 497.210 53.150 497.350 53.660 ;
        RECT 498.170 53.150 498.310 53.660 ;
        RECT 499.130 53.150 499.270 53.660 ;
        RECT 500.090 53.150 500.230 53.660 ;
        RECT 501.050 53.150 501.190 53.660 ;
        RECT 502.010 53.150 502.150 53.660 ;
        RECT 502.970 53.150 503.110 53.660 ;
        RECT 503.930 53.150 504.070 53.660 ;
        RECT 504.890 53.150 505.030 53.660 ;
        RECT 505.850 53.150 505.990 53.660 ;
        RECT 506.810 53.150 506.950 53.660 ;
        RECT 507.770 53.150 507.910 53.660 ;
        RECT 508.730 53.150 508.870 53.660 ;
        RECT 509.690 53.150 509.830 53.660 ;
        RECT 510.650 53.150 510.790 53.660 ;
        RECT 511.610 53.150 511.750 53.660 ;
        RECT 512.570 53.150 512.710 53.660 ;
        RECT 513.530 53.150 513.670 53.660 ;
        RECT 514.490 53.150 514.630 53.660 ;
        RECT 515.450 53.150 515.590 53.660 ;
        RECT 516.410 53.150 516.550 53.660 ;
        RECT 517.370 53.150 517.510 53.660 ;
        RECT 518.330 53.150 518.470 53.660 ;
        RECT 519.290 53.150 519.430 53.660 ;
        RECT 520.250 53.150 520.390 53.660 ;
        RECT 521.210 53.150 521.350 53.660 ;
        RECT 522.170 53.150 522.310 53.660 ;
        RECT 523.130 53.150 523.270 53.660 ;
        RECT 524.090 53.150 524.230 53.660 ;
        RECT 525.050 53.150 525.190 53.660 ;
        RECT 526.010 53.150 526.150 53.660 ;
        RECT 526.970 53.150 527.110 53.660 ;
        RECT 527.930 53.150 528.070 53.660 ;
        RECT 528.890 53.150 529.030 53.660 ;
        RECT 529.850 53.150 529.990 53.660 ;
        RECT 530.810 53.150 530.950 53.660 ;
        RECT 531.770 53.150 531.910 53.660 ;
        RECT 532.730 53.150 532.870 53.660 ;
        RECT 533.690 53.150 533.830 53.660 ;
        RECT 534.650 53.150 534.790 53.660 ;
        RECT 535.610 53.150 535.750 53.660 ;
        RECT 536.570 53.150 536.710 53.660 ;
        RECT 537.530 53.150 537.670 53.660 ;
        RECT 538.490 53.150 538.630 53.660 ;
        RECT 539.450 53.150 539.590 53.660 ;
        RECT 540.410 53.150 540.550 53.660 ;
        RECT 541.370 53.150 541.510 53.660 ;
        RECT 542.330 53.150 542.470 53.660 ;
        RECT 543.290 53.150 543.430 53.660 ;
        RECT 544.250 53.150 544.390 53.660 ;
        RECT 545.210 53.150 545.350 53.660 ;
        RECT 546.170 53.150 546.310 53.660 ;
        RECT 547.130 53.150 547.270 53.660 ;
        RECT 548.090 53.150 548.230 53.660 ;
        RECT 549.050 53.150 549.190 53.660 ;
        RECT 550.010 53.150 550.150 53.660 ;
        RECT 550.970 53.150 551.110 53.660 ;
        RECT 551.930 53.150 552.070 53.660 ;
        RECT 552.890 53.150 553.030 53.660 ;
        RECT 553.850 53.150 553.990 53.660 ;
        RECT 554.810 53.150 554.950 53.660 ;
        RECT 555.770 53.150 555.910 53.660 ;
        RECT 556.730 53.150 556.870 53.660 ;
        RECT 557.690 53.150 557.830 53.660 ;
        RECT 558.650 53.150 558.790 53.660 ;
        RECT 559.610 53.150 559.750 53.660 ;
        RECT 560.570 53.150 560.710 53.660 ;
        RECT 561.530 53.150 561.670 53.660 ;
        RECT 562.490 53.150 562.630 53.660 ;
        RECT 563.450 53.150 563.590 53.660 ;
        RECT 564.410 53.150 564.550 53.660 ;
        RECT 565.370 53.150 565.510 53.660 ;
        RECT 566.330 53.150 566.470 53.660 ;
        RECT 567.290 53.150 567.430 53.660 ;
        RECT 568.250 53.150 568.390 53.660 ;
        RECT 569.210 53.150 569.350 53.660 ;
        RECT 570.170 53.150 570.310 53.660 ;
        RECT 571.130 53.150 571.270 53.660 ;
        RECT 572.090 53.150 572.230 53.660 ;
        RECT 573.050 53.150 573.190 53.660 ;
        RECT 574.010 53.150 574.150 53.660 ;
        RECT 574.970 53.150 575.110 53.660 ;
        RECT 575.930 53.150 576.070 53.660 ;
        RECT 576.890 53.150 577.030 53.660 ;
        RECT 577.850 53.150 577.990 53.660 ;
        RECT 578.810 53.150 578.950 53.660 ;
        RECT 579.770 53.150 579.910 53.660 ;
        RECT 580.730 53.150 580.870 53.660 ;
        RECT 581.690 53.150 581.830 53.660 ;
        RECT 582.650 53.150 582.790 53.660 ;
        RECT 583.610 53.150 583.750 53.660 ;
        RECT 584.570 53.150 584.710 53.660 ;
        RECT 585.530 53.150 585.670 53.660 ;
        RECT 586.490 53.150 586.630 53.660 ;
        RECT 587.450 53.150 587.590 53.660 ;
        RECT 588.410 53.150 588.550 53.660 ;
        RECT 589.370 53.150 589.510 53.660 ;
        RECT 590.330 53.150 590.470 53.660 ;
        RECT 591.290 53.150 591.430 53.660 ;
        RECT 592.250 53.150 592.390 53.660 ;
        RECT 593.210 53.150 593.350 53.660 ;
        RECT 594.170 53.150 594.310 53.660 ;
        RECT 595.130 53.150 595.270 53.660 ;
        RECT 596.090 53.150 596.230 53.660 ;
        RECT 597.050 53.150 597.190 53.660 ;
        RECT 598.010 53.150 640.905 53.660 ;
        RECT 3.255 0.610 640.905 53.150 ;
        RECT 3.770 0.100 10.630 0.610 ;
        RECT 11.450 0.100 18.310 0.610 ;
        RECT 19.130 0.100 25.990 0.610 ;
        RECT 26.810 0.100 33.670 0.610 ;
        RECT 34.490 0.100 41.350 0.610 ;
        RECT 42.170 0.100 49.030 0.610 ;
        RECT 49.850 0.100 56.710 0.610 ;
        RECT 57.530 0.100 64.390 0.610 ;
        RECT 65.210 0.100 72.070 0.610 ;
        RECT 72.890 0.100 79.750 0.610 ;
        RECT 80.570 0.100 87.430 0.610 ;
        RECT 88.250 0.100 95.110 0.610 ;
        RECT 95.930 0.100 102.790 0.610 ;
        RECT 103.610 0.100 110.470 0.610 ;
        RECT 111.290 0.100 118.150 0.610 ;
        RECT 118.970 0.100 125.830 0.610 ;
        RECT 126.650 0.100 133.510 0.610 ;
        RECT 134.330 0.100 141.190 0.610 ;
        RECT 142.010 0.100 148.870 0.610 ;
        RECT 149.690 0.100 156.550 0.610 ;
        RECT 157.370 0.100 164.230 0.610 ;
        RECT 165.050 0.100 171.910 0.610 ;
        RECT 172.730 0.100 179.590 0.610 ;
        RECT 180.410 0.100 187.270 0.610 ;
        RECT 188.090 0.100 194.950 0.610 ;
        RECT 195.770 0.100 202.630 0.610 ;
        RECT 203.450 0.100 210.310 0.610 ;
        RECT 211.130 0.100 217.990 0.610 ;
        RECT 218.810 0.100 225.670 0.610 ;
        RECT 226.490 0.100 233.350 0.610 ;
        RECT 234.170 0.100 241.030 0.610 ;
        RECT 241.850 0.100 248.710 0.610 ;
        RECT 249.530 0.100 256.390 0.610 ;
        RECT 257.210 0.100 264.070 0.610 ;
        RECT 264.890 0.100 271.750 0.610 ;
        RECT 272.570 0.100 279.430 0.610 ;
        RECT 280.250 0.100 287.110 0.610 ;
        RECT 287.930 0.100 294.790 0.610 ;
        RECT 295.610 0.100 302.470 0.610 ;
        RECT 303.290 0.100 310.150 0.610 ;
        RECT 310.970 0.100 317.830 0.610 ;
        RECT 318.650 0.100 325.510 0.610 ;
        RECT 326.330 0.100 333.190 0.610 ;
        RECT 334.010 0.100 340.870 0.610 ;
        RECT 341.690 0.100 348.550 0.610 ;
        RECT 349.370 0.100 356.230 0.610 ;
        RECT 357.050 0.100 363.910 0.610 ;
        RECT 364.730 0.100 371.590 0.610 ;
        RECT 372.410 0.100 379.270 0.610 ;
        RECT 380.090 0.100 386.950 0.610 ;
        RECT 387.770 0.100 394.630 0.610 ;
        RECT 395.450 0.100 402.310 0.610 ;
        RECT 403.130 0.100 409.990 0.610 ;
        RECT 410.810 0.100 417.670 0.610 ;
        RECT 418.490 0.100 425.350 0.610 ;
        RECT 426.170 0.100 433.030 0.610 ;
        RECT 433.850 0.100 440.710 0.610 ;
        RECT 441.530 0.100 448.390 0.610 ;
        RECT 449.210 0.100 456.070 0.610 ;
        RECT 456.890 0.100 463.750 0.610 ;
        RECT 464.570 0.100 471.430 0.610 ;
        RECT 472.250 0.100 479.110 0.610 ;
        RECT 479.930 0.100 518.470 0.610 ;
        RECT 519.290 0.100 519.430 0.610 ;
        RECT 520.250 0.100 520.390 0.610 ;
        RECT 521.210 0.100 521.350 0.610 ;
        RECT 522.170 0.100 522.310 0.610 ;
        RECT 523.130 0.100 523.270 0.610 ;
        RECT 524.090 0.100 524.230 0.610 ;
        RECT 525.050 0.100 525.190 0.610 ;
        RECT 526.010 0.100 526.150 0.610 ;
        RECT 526.970 0.100 527.110 0.610 ;
        RECT 527.930 0.100 528.070 0.610 ;
        RECT 528.890 0.100 529.030 0.610 ;
        RECT 529.850 0.100 529.990 0.610 ;
        RECT 530.810 0.100 530.950 0.610 ;
        RECT 531.770 0.100 531.910 0.610 ;
        RECT 532.730 0.100 532.870 0.610 ;
        RECT 533.690 0.100 533.830 0.610 ;
        RECT 534.650 0.100 534.790 0.610 ;
        RECT 535.610 0.100 535.750 0.610 ;
        RECT 536.570 0.100 536.710 0.610 ;
        RECT 537.530 0.100 537.670 0.610 ;
        RECT 538.490 0.100 538.630 0.610 ;
        RECT 539.450 0.100 539.590 0.610 ;
        RECT 540.410 0.100 540.550 0.610 ;
        RECT 541.370 0.100 541.510 0.610 ;
        RECT 542.330 0.100 542.470 0.610 ;
        RECT 543.290 0.100 543.430 0.610 ;
        RECT 544.250 0.100 544.390 0.610 ;
        RECT 545.210 0.100 545.350 0.610 ;
        RECT 546.170 0.100 546.310 0.610 ;
        RECT 547.130 0.100 547.270 0.610 ;
        RECT 548.090 0.100 548.230 0.610 ;
        RECT 549.050 0.100 549.190 0.610 ;
        RECT 550.010 0.100 550.150 0.610 ;
        RECT 550.970 0.100 551.110 0.610 ;
        RECT 551.930 0.100 552.070 0.610 ;
        RECT 552.890 0.100 553.030 0.610 ;
        RECT 553.850 0.100 553.990 0.610 ;
        RECT 554.810 0.100 554.950 0.610 ;
        RECT 555.770 0.100 555.910 0.610 ;
        RECT 556.730 0.100 556.870 0.610 ;
        RECT 557.690 0.100 557.830 0.610 ;
        RECT 558.650 0.100 558.790 0.610 ;
        RECT 559.610 0.100 559.750 0.610 ;
        RECT 560.570 0.100 560.710 0.610 ;
        RECT 561.530 0.100 561.670 0.610 ;
        RECT 562.490 0.100 562.630 0.610 ;
        RECT 563.450 0.100 563.590 0.610 ;
        RECT 564.410 0.100 564.550 0.610 ;
        RECT 565.370 0.100 565.510 0.610 ;
        RECT 566.330 0.100 566.470 0.610 ;
        RECT 567.290 0.100 567.430 0.610 ;
        RECT 568.250 0.100 568.390 0.610 ;
        RECT 569.210 0.100 569.350 0.610 ;
        RECT 570.170 0.100 570.310 0.610 ;
        RECT 571.130 0.100 571.270 0.610 ;
        RECT 572.090 0.100 572.230 0.610 ;
        RECT 573.050 0.100 573.190 0.610 ;
        RECT 574.010 0.100 574.150 0.610 ;
        RECT 574.970 0.100 575.110 0.610 ;
        RECT 575.930 0.100 576.070 0.610 ;
        RECT 576.890 0.100 577.030 0.610 ;
        RECT 577.850 0.100 577.990 0.610 ;
        RECT 578.810 0.100 578.950 0.610 ;
        RECT 579.770 0.100 579.910 0.610 ;
        RECT 580.730 0.100 580.870 0.610 ;
        RECT 581.690 0.100 581.830 0.610 ;
        RECT 582.650 0.100 582.790 0.610 ;
        RECT 583.610 0.100 583.750 0.610 ;
        RECT 584.570 0.100 584.710 0.610 ;
        RECT 585.530 0.100 585.670 0.610 ;
        RECT 586.490 0.100 586.630 0.610 ;
        RECT 587.450 0.100 587.590 0.610 ;
        RECT 588.410 0.100 588.550 0.610 ;
        RECT 589.370 0.100 589.510 0.610 ;
        RECT 590.330 0.100 590.470 0.610 ;
        RECT 591.290 0.100 591.430 0.610 ;
        RECT 592.250 0.100 592.390 0.610 ;
        RECT 593.210 0.100 593.350 0.610 ;
        RECT 594.170 0.100 594.310 0.610 ;
        RECT 595.130 0.100 595.270 0.610 ;
        RECT 596.090 0.100 596.230 0.610 ;
        RECT 597.050 0.100 597.190 0.610 ;
        RECT 598.010 0.100 598.150 0.610 ;
        RECT 598.970 0.100 599.110 0.610 ;
        RECT 599.930 0.100 600.070 0.610 ;
        RECT 600.890 0.100 601.030 0.610 ;
        RECT 601.850 0.100 601.990 0.610 ;
        RECT 602.810 0.100 602.950 0.610 ;
        RECT 603.770 0.100 603.910 0.610 ;
        RECT 604.730 0.100 604.870 0.610 ;
        RECT 605.690 0.100 605.830 0.610 ;
        RECT 606.650 0.100 606.790 0.610 ;
        RECT 607.610 0.100 607.750 0.610 ;
        RECT 608.570 0.100 608.710 0.610 ;
        RECT 609.530 0.100 609.670 0.610 ;
        RECT 610.490 0.100 640.905 0.610 ;
      LAYER Metal3 ;
        RECT 0.400 52.910 644.720 53.445 ;
        RECT 0.610 52.090 644.510 52.910 ;
        RECT 0.400 51.230 644.720 52.090 ;
        RECT 0.610 50.410 644.510 51.230 ;
        RECT 0.400 49.550 644.720 50.410 ;
        RECT 0.610 48.730 644.510 49.550 ;
        RECT 0.400 47.870 644.720 48.730 ;
        RECT 0.610 47.050 644.510 47.870 ;
        RECT 0.400 46.190 644.720 47.050 ;
        RECT 0.610 45.370 644.510 46.190 ;
        RECT 0.400 44.510 644.720 45.370 ;
        RECT 0.610 43.690 644.510 44.510 ;
        RECT 0.400 42.830 644.720 43.690 ;
        RECT 0.610 42.010 644.510 42.830 ;
        RECT 0.400 41.150 644.720 42.010 ;
        RECT 0.610 40.330 644.510 41.150 ;
        RECT 0.400 39.470 644.720 40.330 ;
        RECT 0.610 38.650 644.510 39.470 ;
        RECT 0.400 37.790 644.720 38.650 ;
        RECT 0.610 36.970 644.510 37.790 ;
        RECT 0.400 36.110 644.720 36.970 ;
        RECT 0.610 35.290 644.510 36.110 ;
        RECT 0.400 34.430 644.720 35.290 ;
        RECT 0.610 33.610 644.510 34.430 ;
        RECT 0.400 32.750 644.720 33.610 ;
        RECT 0.610 31.930 644.510 32.750 ;
        RECT 0.400 31.070 644.720 31.930 ;
        RECT 0.610 30.250 644.510 31.070 ;
        RECT 0.400 29.390 644.720 30.250 ;
        RECT 0.610 28.570 644.510 29.390 ;
        RECT 0.400 27.710 644.720 28.570 ;
        RECT 0.610 26.890 644.510 27.710 ;
        RECT 0.400 26.030 644.720 26.890 ;
        RECT 0.610 25.210 644.510 26.030 ;
        RECT 0.400 24.350 644.720 25.210 ;
        RECT 0.610 23.530 644.510 24.350 ;
        RECT 0.400 22.670 644.720 23.530 ;
        RECT 0.610 21.850 644.510 22.670 ;
        RECT 0.400 20.990 644.720 21.850 ;
        RECT 0.610 20.170 644.510 20.990 ;
        RECT 0.400 19.310 644.720 20.170 ;
        RECT 0.610 18.490 644.510 19.310 ;
        RECT 0.400 17.630 644.720 18.490 ;
        RECT 0.610 16.810 644.510 17.630 ;
        RECT 0.400 15.950 644.720 16.810 ;
        RECT 0.610 15.130 644.510 15.950 ;
        RECT 0.400 14.270 644.720 15.130 ;
        RECT 0.610 13.450 644.510 14.270 ;
        RECT 0.400 12.590 644.720 13.450 ;
        RECT 0.610 11.770 644.510 12.590 ;
        RECT 0.400 10.910 644.720 11.770 ;
        RECT 0.610 10.090 644.510 10.910 ;
        RECT 0.400 9.230 644.720 10.090 ;
        RECT 0.610 8.410 644.510 9.230 ;
        RECT 0.400 7.550 644.720 8.410 ;
        RECT 0.610 6.730 644.510 7.550 ;
        RECT 0.400 5.870 644.720 6.730 ;
        RECT 0.610 5.050 644.510 5.870 ;
        RECT 0.400 4.190 644.720 5.050 ;
        RECT 0.610 3.370 644.510 4.190 ;
        RECT 0.400 2.510 644.720 3.370 ;
        RECT 0.610 1.690 644.510 2.510 ;
        RECT 0.400 0.830 644.720 1.690 ;
        RECT 0.610 0.315 644.510 0.830 ;
      LAYER Metal4 ;
        RECT 2.295 0.275 634.665 53.485 ;
      LAYER Metal5 ;
        RECT 2.255 0.320 634.705 53.440 ;
      LAYER TopMetal1 ;
        RECT 335.980 2.540 379.980 35.680 ;
        RECT 385.460 2.540 386.180 35.680 ;
        RECT 391.660 2.540 443.820 35.680 ;
        RECT 449.300 2.540 450.020 35.680 ;
        RECT 455.500 2.540 519.420 35.680 ;
        RECT 524.900 2.540 525.620 35.680 ;
        RECT 531.100 2.540 572.460 35.680 ;
  END
END S_OBI
END LIBRARY

